VERSION 5.8 ;
BUSBITCHARS "[]" ;
DIVIDERCHAR "/" ;
UNITS
    DATABASE MICRONS 1000 ;
END UNITS

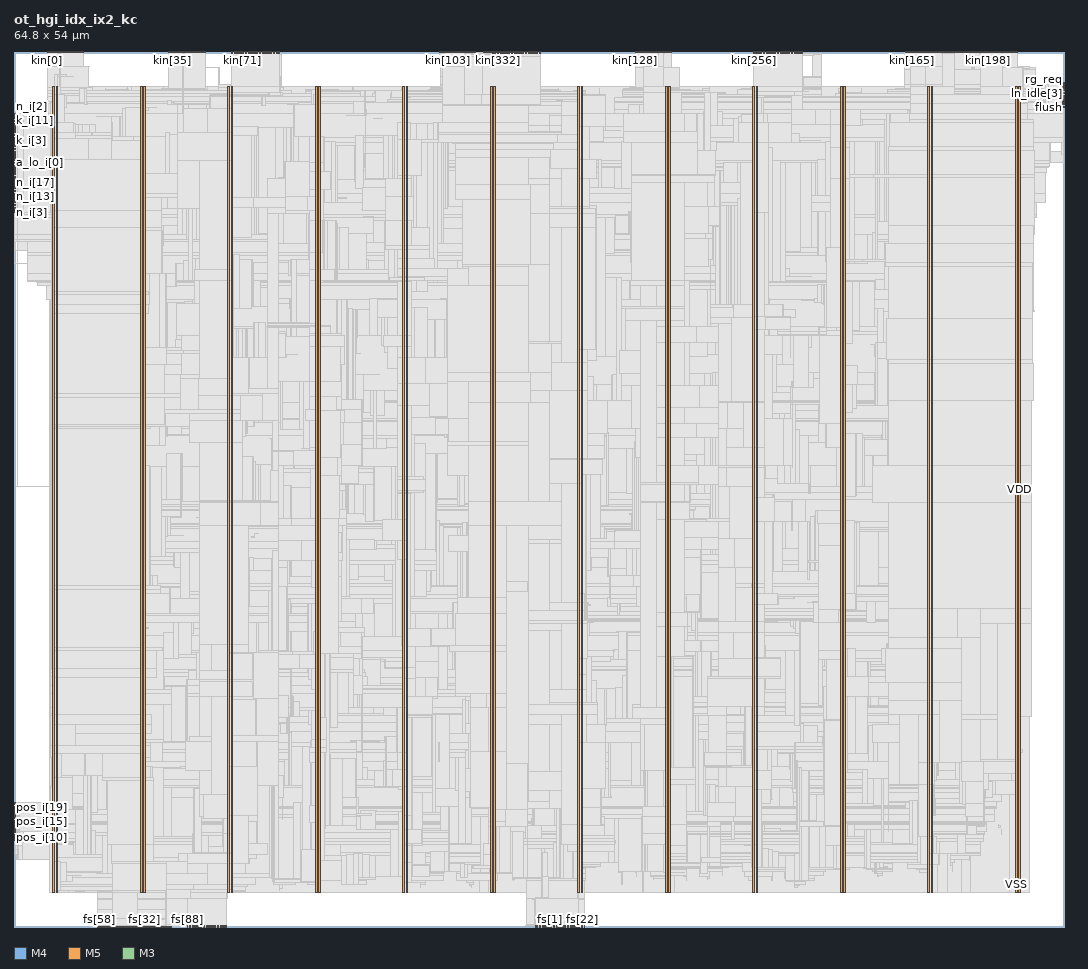
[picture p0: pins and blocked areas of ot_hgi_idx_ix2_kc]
MACRO ot_hgi_idx_ix2_kc
  FOREIGN ot_hgi_idx_ix2_kc 0 0 ;
  CLASS BLOCK ;
  SIZE 64.8 BY 54 ;
  PIN a_lo_i[0]
    DIRECTION INPUT ;
    USE SIGNAL ;
    PORT
      LAYER M4 ;
        RECT  0 47.184 0.084 47.208 ;
    END
  END a_lo_i[0]
  PIN a_lo_i[1]
    DIRECTION INPUT ;
    USE SIGNAL ;
    PORT
      LAYER M4 ;
        RECT  0 47.28 0.084 47.304 ;
    END
  END a_lo_i[1]
  PIN a_lo_i[2]
    DIRECTION INPUT ;
    USE SIGNAL ;
    PORT
      LAYER M4 ;
        RECT  0 47.376 0.084 47.4 ;
    END
  END a_lo_i[2]
  PIN c_done[0]
    DIRECTION INPUT ;
    USE SIGNAL ;
    PORT
      LAYER M5 ;
        RECT  32.208 0 32.232 0.084 ;
    END
  END c_done[0]
  PIN c_done[1]
    DIRECTION INPUT ;
    USE SIGNAL ;
    PORT
      LAYER M5 ;
        RECT  32.304 0 32.328 0.084 ;
    END
  END c_done[1]
  PIN c_done[2]
    DIRECTION INPUT ;
    USE SIGNAL ;
    PORT
      LAYER M5 ;
        RECT  32.4 0 32.424 0.084 ;
    END
  END c_done[2]
  PIN c_done[3]
    DIRECTION INPUT ;
    USE SIGNAL ;
    PORT
      LAYER M5 ;
        RECT  32.496 0 32.52 0.084 ;
    END
  END c_done[3]
  PIN c_done[4]
    DIRECTION INPUT ;
    USE SIGNAL ;
    PORT
      LAYER M5 ;
        RECT  32.592 0 32.616 0.084 ;
    END
  END c_done[4]
  PIN c_done[5]
    DIRECTION INPUT ;
    USE SIGNAL ;
    PORT
      LAYER M5 ;
        RECT  32.688 0 32.712 0.084 ;
    END
  END c_done[5]
  PIN c_done[6]
    DIRECTION INPUT ;
    USE SIGNAL ;
    PORT
      LAYER M5 ;
        RECT  32.784 0 32.808 0.084 ;
    END
  END c_done[6]
  PIN c_done[7]
    DIRECTION INPUT ;
    USE SIGNAL ;
    PORT
      LAYER M5 ;
        RECT  32.88 0 32.904 0.084 ;
    END
  END c_done[7]
  PIN cand_en_i
    DIRECTION INPUT ;
    USE SIGNAL ;
    PORT
      LAYER M4 ;
        RECT  0 47.472 0.084 47.496 ;
    END
  END cand_en_i
  PIN clk
    DIRECTION INPUT ;
    USE SIGNAL ;
    PORT
      LAYER M4 ;
        RECT  0 47.568 0.084 47.592 ;
    END
  END clk
  PIN cs_lo_i[0]
    DIRECTION INPUT ;
    USE SIGNAL ;
    PORT
      LAYER M4 ;
        RECT  0 47.664 0.084 47.688 ;
    END
  END cs_lo_i[0]
  PIN cs_lo_i[1]
    DIRECTION INPUT ;
    USE SIGNAL ;
    PORT
      LAYER M4 ;
        RECT  0 47.76 0.084 47.784 ;
    END
  END cs_lo_i[1]
  PIN cs_lo_i[2]
    DIRECTION INPUT ;
    USE SIGNAL ;
    PORT
      LAYER M4 ;
        RECT  0 47.856 0.084 47.88 ;
    END
  END cs_lo_i[2]
  PIN cs_lo_i[3]
    DIRECTION INPUT ;
    USE SIGNAL ;
    PORT
      LAYER M4 ;
        RECT  0 47.952 0.084 47.976 ;
    END
  END cs_lo_i[3]
  PIN cs_lo_i[4]
    DIRECTION INPUT ;
    USE SIGNAL ;
    PORT
      LAYER M4 ;
        RECT  0 48.048 0.084 48.072 ;
    END
  END cs_lo_i[4]
  PIN cs_lo_i[5]
    DIRECTION INPUT ;
    USE SIGNAL ;
    PORT
      LAYER M4 ;
        RECT  0 48.144 0.084 48.168 ;
    END
  END cs_lo_i[5]
  PIN done
    DIRECTION OUTPUT ;
    USE SIGNAL ;
    PORT
      LAYER M4 ;
        RECT  0 48.24 0.084 48.264 ;
    END
  END done
  PIN ev[0]
    DIRECTION INPUT ;
    USE SIGNAL ;
    PORT
      LAYER M4 ;
        RECT  0 48.336 0.084 48.36 ;
    END
  END ev[0]
  PIN ev[1]
    DIRECTION INPUT ;
    USE SIGNAL ;
    PORT
      LAYER M4 ;
        RECT  0 48.432 0.084 48.456 ;
    END
  END ev[1]
  PIN fault
    DIRECTION OUTPUT ;
    USE SIGNAL ;
    PORT
      LAYER M4 ;
        RECT  0 48.528 0.084 48.552 ;
    END
  END fault
  PIN flush
    DIRECTION OUTPUT ;
    USE SIGNAL ;
    PORT
      LAYER M4 ;
        RECT  64.716 50.544 64.8 50.568 ;
    END
  END flush
  PIN fs[0]
    DIRECTION OUTPUT ;
    USE SIGNAL ;
    PORT
      LAYER M5 ;
        RECT  32.976 0 33 0.084 ;
    END
  END fs[0]
  PIN fs[10]
    DIRECTION OUTPUT ;
    USE SIGNAL ;
    PORT
      LAYER M5 ;
        RECT  33.936 0 33.96 0.084 ;
    END
  END fs[10]
  PIN fs[11]
    DIRECTION OUTPUT ;
    USE SIGNAL ;
    PORT
      LAYER M5 ;
        RECT  34.032 0 34.056 0.084 ;
    END
  END fs[11]
  PIN fs[12]
    DIRECTION OUTPUT ;
    USE SIGNAL ;
    PORT
      LAYER M5 ;
        RECT  34.128 0 34.152 0.084 ;
    END
  END fs[12]
  PIN fs[13]
    DIRECTION OUTPUT ;
    USE SIGNAL ;
    PORT
      LAYER M5 ;
        RECT  34.224 0 34.248 0.084 ;
    END
  END fs[13]
  PIN fs[14]
    DIRECTION OUTPUT ;
    USE SIGNAL ;
    PORT
      LAYER M5 ;
        RECT  34.32 0 34.344 0.084 ;
    END
  END fs[14]
  PIN fs[15]
    DIRECTION OUTPUT ;
    USE SIGNAL ;
    PORT
      LAYER M5 ;
        RECT  34.416 0 34.44 0.084 ;
    END
  END fs[15]
  PIN fs[16]
    DIRECTION OUTPUT ;
    USE SIGNAL ;
    PORT
      LAYER M5 ;
        RECT  34.512 0 34.536 0.084 ;
    END
  END fs[16]
  PIN fs[17]
    DIRECTION OUTPUT ;
    USE SIGNAL ;
    PORT
      LAYER M5 ;
        RECT  34.608 0 34.632 0.084 ;
    END
  END fs[17]
  PIN fs[18]
    DIRECTION OUTPUT ;
    USE SIGNAL ;
    PORT
      LAYER M5 ;
        RECT  34.704 0 34.728 0.084 ;
    END
  END fs[18]
  PIN fs[19]
    DIRECTION OUTPUT ;
    USE SIGNAL ;
    PORT
      LAYER M5 ;
        RECT  34.8 0 34.824 0.084 ;
    END
  END fs[19]
  PIN fs[1]
    DIRECTION OUTPUT ;
    USE SIGNAL ;
    PORT
      LAYER M5 ;
        RECT  33.072 0 33.096 0.084 ;
    END
  END fs[1]
  PIN fs[20]
    DIRECTION OUTPUT ;
    USE SIGNAL ;
    PORT
      LAYER M5 ;
        RECT  34.896 0 34.92 0.084 ;
    END
  END fs[20]
  PIN fs[21]
    DIRECTION OUTPUT ;
    USE SIGNAL ;
    PORT
      LAYER M5 ;
        RECT  34.992 0 35.016 0.084 ;
    END
  END fs[21]
  PIN fs[22]
    DIRECTION OUTPUT ;
    USE SIGNAL ;
    PORT
      LAYER M5 ;
        RECT  35.088 0 35.112 0.084 ;
    END
  END fs[22]
  PIN fs[23]
    DIRECTION OUTPUT ;
    USE SIGNAL ;
    PORT
      LAYER M5 ;
        RECT  35.184 0 35.208 0.084 ;
    END
  END fs[23]
  PIN fs[24]
    DIRECTION OUTPUT ;
    USE SIGNAL ;
    PORT
      LAYER M3 ;
        RECT  7.452 0 7.47 0.037 ;
    END
  END fs[24]
  PIN fs[25]
    DIRECTION OUTPUT ;
    USE SIGNAL ;
    PORT
      LAYER M3 ;
        RECT  7.524 0 7.542 0.037 ;
    END
  END fs[25]
  PIN fs[26]
    DIRECTION OUTPUT ;
    USE SIGNAL ;
    PORT
      LAYER M3 ;
        RECT  7.596 0 7.614 0.037 ;
    END
  END fs[26]
  PIN fs[27]
    DIRECTION OUTPUT ;
    USE SIGNAL ;
    PORT
      LAYER M3 ;
        RECT  7.668 0 7.686 0.037 ;
    END
  END fs[27]
  PIN fs[28]
    DIRECTION OUTPUT ;
    USE SIGNAL ;
    PORT
      LAYER M3 ;
        RECT  7.74 0 7.758 0.037 ;
    END
  END fs[28]
  PIN fs[29]
    DIRECTION OUTPUT ;
    USE SIGNAL ;
    PORT
      LAYER M3 ;
        RECT  7.812 0 7.83 0.037 ;
    END
  END fs[29]
  PIN fs[2]
    DIRECTION OUTPUT ;
    USE SIGNAL ;
    PORT
      LAYER M5 ;
        RECT  33.168 0 33.192 0.084 ;
    END
  END fs[2]
  PIN fs[30]
    DIRECTION OUTPUT ;
    USE SIGNAL ;
    PORT
      LAYER M3 ;
        RECT  7.884 0 7.902 0.037 ;
    END
  END fs[30]
  PIN fs[31]
    DIRECTION OUTPUT ;
    USE SIGNAL ;
    PORT
      LAYER M3 ;
        RECT  7.956 0 7.974 0.037 ;
    END
  END fs[31]
  PIN fs[32]
    DIRECTION OUTPUT ;
    USE SIGNAL ;
    PORT
      LAYER M3 ;
        RECT  8.028 0 8.046 0.037 ;
    END
  END fs[32]
  PIN fs[33]
    DIRECTION OUTPUT ;
    USE SIGNAL ;
    PORT
      LAYER M3 ;
        RECT  8.1 0 8.118 0.037 ;
    END
  END fs[33]
  PIN fs[34]
    DIRECTION OUTPUT ;
    USE SIGNAL ;
    PORT
      LAYER M3 ;
        RECT  8.172 0 8.19 0.037 ;
    END
  END fs[34]
  PIN fs[35]
    DIRECTION OUTPUT ;
    USE SIGNAL ;
    PORT
      LAYER M3 ;
        RECT  8.244 0 8.262 0.037 ;
    END
  END fs[35]
  PIN fs[36]
    DIRECTION OUTPUT ;
    USE SIGNAL ;
    PORT
      LAYER M3 ;
        RECT  8.316 0 8.334 0.037 ;
    END
  END fs[36]
  PIN fs[37]
    DIRECTION OUTPUT ;
    USE SIGNAL ;
    PORT
      LAYER M3 ;
        RECT  8.388 0 8.406 0.037 ;
    END
  END fs[37]
  PIN fs[38]
    DIRECTION OUTPUT ;
    USE SIGNAL ;
    PORT
      LAYER M3 ;
        RECT  8.46 0 8.478 0.037 ;
    END
  END fs[38]
  PIN fs[39]
    DIRECTION OUTPUT ;
    USE SIGNAL ;
    PORT
      LAYER M3 ;
        RECT  8.532 0 8.55 0.037 ;
    END
  END fs[39]
  PIN fs[3]
    DIRECTION OUTPUT ;
    USE SIGNAL ;
    PORT
      LAYER M5 ;
        RECT  33.264 0 33.288 0.084 ;
    END
  END fs[3]
  PIN fs[40]
    DIRECTION OUTPUT ;
    USE SIGNAL ;
    PORT
      LAYER M3 ;
        RECT  8.604 0 8.622 0.037 ;
    END
  END fs[40]
  PIN fs[41]
    DIRECTION OUTPUT ;
    USE SIGNAL ;
    PORT
      LAYER M3 ;
        RECT  8.676 0 8.694 0.037 ;
    END
  END fs[41]
  PIN fs[42]
    DIRECTION OUTPUT ;
    USE SIGNAL ;
    PORT
      LAYER M3 ;
        RECT  8.748 0 8.766 0.037 ;
    END
  END fs[42]
  PIN fs[43]
    DIRECTION OUTPUT ;
    USE SIGNAL ;
    PORT
      LAYER M3 ;
        RECT  8.82 0 8.838 0.037 ;
    END
  END fs[43]
  PIN fs[44]
    DIRECTION OUTPUT ;
    USE SIGNAL ;
    PORT
      LAYER M3 ;
        RECT  8.892 0 8.91 0.037 ;
    END
  END fs[44]
  PIN fs[45]
    DIRECTION OUTPUT ;
    USE SIGNAL ;
    PORT
      LAYER M3 ;
        RECT  8.964 0 8.982 0.037 ;
    END
  END fs[45]
  PIN fs[46]
    DIRECTION OUTPUT ;
    USE SIGNAL ;
    PORT
      LAYER M3 ;
        RECT  9.036 0 9.054 0.037 ;
    END
  END fs[46]
  PIN fs[47]
    DIRECTION OUTPUT ;
    USE SIGNAL ;
    PORT
      LAYER M3 ;
        RECT  9.108 0 9.126 0.037 ;
    END
  END fs[47]
  PIN fs[48]
    DIRECTION OUTPUT ;
    USE SIGNAL ;
    PORT
      LAYER M3 ;
        RECT  9.18 0 9.198 0.037 ;
    END
  END fs[48]
  PIN fs[49]
    DIRECTION OUTPUT ;
    USE SIGNAL ;
    PORT
      LAYER M3 ;
        RECT  9.252 0 9.27 0.037 ;
    END
  END fs[49]
  PIN fs[4]
    DIRECTION OUTPUT ;
    USE SIGNAL ;
    PORT
      LAYER M5 ;
        RECT  33.36 0 33.384 0.084 ;
    END
  END fs[4]
  PIN fs[50]
    DIRECTION OUTPUT ;
    USE SIGNAL ;
    PORT
      LAYER M3 ;
        RECT  9.324 0 9.342 0.037 ;
    END
  END fs[50]
  PIN fs[51]
    DIRECTION OUTPUT ;
    USE SIGNAL ;
    PORT
      LAYER M3 ;
        RECT  9.396 0 9.414 0.037 ;
    END
  END fs[51]
  PIN fs[52]
    DIRECTION OUTPUT ;
    USE SIGNAL ;
    PORT
      LAYER M3 ;
        RECT  9.468 0 9.486 0.037 ;
    END
  END fs[52]
  PIN fs[53]
    DIRECTION OUTPUT ;
    USE SIGNAL ;
    PORT
      LAYER M3 ;
        RECT  9.54 0 9.558 0.037 ;
    END
  END fs[53]
  PIN fs[54]
    DIRECTION OUTPUT ;
    USE SIGNAL ;
    PORT
      LAYER M3 ;
        RECT  9.612 0 9.63 0.037 ;
    END
  END fs[54]
  PIN fs[55]
    DIRECTION OUTPUT ;
    USE SIGNAL ;
    PORT
      LAYER M3 ;
        RECT  9.684 0 9.702 0.037 ;
    END
  END fs[55]
  PIN fs[56]
    DIRECTION OUTPUT ;
    USE SIGNAL ;
    PORT
      LAYER M3 ;
        RECT  5.148 0 5.166 0.037 ;
    END
  END fs[56]
  PIN fs[57]
    DIRECTION OUTPUT ;
    USE SIGNAL ;
    PORT
      LAYER M3 ;
        RECT  5.22 0 5.238 0.037 ;
    END
  END fs[57]
  PIN fs[58]
    DIRECTION OUTPUT ;
    USE SIGNAL ;
    PORT
      LAYER M3 ;
        RECT  5.292 0 5.31 0.037 ;
    END
  END fs[58]
  PIN fs[59]
    DIRECTION OUTPUT ;
    USE SIGNAL ;
    PORT
      LAYER M3 ;
        RECT  5.364 0 5.382 0.037 ;
    END
  END fs[59]
  PIN fs[5]
    DIRECTION OUTPUT ;
    USE SIGNAL ;
    PORT
      LAYER M5 ;
        RECT  33.456 0 33.48 0.084 ;
    END
  END fs[5]
  PIN fs[60]
    DIRECTION OUTPUT ;
    USE SIGNAL ;
    PORT
      LAYER M3 ;
        RECT  5.436 0 5.454 0.037 ;
    END
  END fs[60]
  PIN fs[61]
    DIRECTION OUTPUT ;
    USE SIGNAL ;
    PORT
      LAYER M3 ;
        RECT  5.508 0 5.526 0.037 ;
    END
  END fs[61]
  PIN fs[62]
    DIRECTION OUTPUT ;
    USE SIGNAL ;
    PORT
      LAYER M3 ;
        RECT  5.58 0 5.598 0.037 ;
    END
  END fs[62]
  PIN fs[63]
    DIRECTION OUTPUT ;
    USE SIGNAL ;
    PORT
      LAYER M3 ;
        RECT  5.652 0 5.67 0.037 ;
    END
  END fs[63]
  PIN fs[64]
    DIRECTION OUTPUT ;
    USE SIGNAL ;
    PORT
      LAYER M3 ;
        RECT  5.724 0 5.742 0.037 ;
    END
  END fs[64]
  PIN fs[65]
    DIRECTION OUTPUT ;
    USE SIGNAL ;
    PORT
      LAYER M3 ;
        RECT  5.796 0 5.814 0.037 ;
    END
  END fs[65]
  PIN fs[66]
    DIRECTION OUTPUT ;
    USE SIGNAL ;
    PORT
      LAYER M3 ;
        RECT  5.868 0 5.886 0.037 ;
    END
  END fs[66]
  PIN fs[67]
    DIRECTION OUTPUT ;
    USE SIGNAL ;
    PORT
      LAYER M3 ;
        RECT  5.94 0 5.958 0.037 ;
    END
  END fs[67]
  PIN fs[68]
    DIRECTION OUTPUT ;
    USE SIGNAL ;
    PORT
      LAYER M3 ;
        RECT  6.012 0 6.03 0.037 ;
    END
  END fs[68]
  PIN fs[69]
    DIRECTION OUTPUT ;
    USE SIGNAL ;
    PORT
      LAYER M3 ;
        RECT  6.084 0 6.102 0.037 ;
    END
  END fs[69]
  PIN fs[6]
    DIRECTION OUTPUT ;
    USE SIGNAL ;
    PORT
      LAYER M5 ;
        RECT  33.552 0 33.576 0.084 ;
    END
  END fs[6]
  PIN fs[70]
    DIRECTION OUTPUT ;
    USE SIGNAL ;
    PORT
      LAYER M3 ;
        RECT  6.156 0 6.174 0.037 ;
    END
  END fs[70]
  PIN fs[71]
    DIRECTION OUTPUT ;
    USE SIGNAL ;
    PORT
      LAYER M3 ;
        RECT  6.228 0 6.246 0.037 ;
    END
  END fs[71]
  PIN fs[72]
    DIRECTION OUTPUT ;
    USE SIGNAL ;
    PORT
      LAYER M3 ;
        RECT  6.3 0 6.318 0.037 ;
    END
  END fs[72]
  PIN fs[73]
    DIRECTION OUTPUT ;
    USE SIGNAL ;
    PORT
      LAYER M3 ;
        RECT  6.372 0 6.39 0.037 ;
    END
  END fs[73]
  PIN fs[74]
    DIRECTION OUTPUT ;
    USE SIGNAL ;
    PORT
      LAYER M3 ;
        RECT  6.444 0 6.462 0.037 ;
    END
  END fs[74]
  PIN fs[75]
    DIRECTION OUTPUT ;
    USE SIGNAL ;
    PORT
      LAYER M3 ;
        RECT  6.516 0 6.534 0.037 ;
    END
  END fs[75]
  PIN fs[76]
    DIRECTION OUTPUT ;
    USE SIGNAL ;
    PORT
      LAYER M3 ;
        RECT  6.588 0 6.606 0.037 ;
    END
  END fs[76]
  PIN fs[77]
    DIRECTION OUTPUT ;
    USE SIGNAL ;
    PORT
      LAYER M3 ;
        RECT  6.66 0 6.678 0.037 ;
    END
  END fs[77]
  PIN fs[78]
    DIRECTION OUTPUT ;
    USE SIGNAL ;
    PORT
      LAYER M3 ;
        RECT  6.732 0 6.75 0.037 ;
    END
  END fs[78]
  PIN fs[79]
    DIRECTION OUTPUT ;
    USE SIGNAL ;
    PORT
      LAYER M3 ;
        RECT  6.804 0 6.822 0.037 ;
    END
  END fs[79]
  PIN fs[7]
    DIRECTION OUTPUT ;
    USE SIGNAL ;
    PORT
      LAYER M5 ;
        RECT  33.648 0 33.672 0.084 ;
    END
  END fs[7]
  PIN fs[80]
    DIRECTION OUTPUT ;
    USE SIGNAL ;
    PORT
      LAYER M3 ;
        RECT  6.876 0 6.894 0.037 ;
    END
  END fs[80]
  PIN fs[81]
    DIRECTION OUTPUT ;
    USE SIGNAL ;
    PORT
      LAYER M3 ;
        RECT  6.948 0 6.966 0.037 ;
    END
  END fs[81]
  PIN fs[82]
    DIRECTION OUTPUT ;
    USE SIGNAL ;
    PORT
      LAYER M3 ;
        RECT  7.02 0 7.038 0.037 ;
    END
  END fs[82]
  PIN fs[83]
    DIRECTION OUTPUT ;
    USE SIGNAL ;
    PORT
      LAYER M3 ;
        RECT  7.092 0 7.11 0.037 ;
    END
  END fs[83]
  PIN fs[84]
    DIRECTION OUTPUT ;
    USE SIGNAL ;
    PORT
      LAYER M3 ;
        RECT  7.164 0 7.182 0.037 ;
    END
  END fs[84]
  PIN fs[85]
    DIRECTION OUTPUT ;
    USE SIGNAL ;
    PORT
      LAYER M3 ;
        RECT  7.236 0 7.254 0.037 ;
    END
  END fs[85]
  PIN fs[86]
    DIRECTION OUTPUT ;
    USE SIGNAL ;
    PORT
      LAYER M3 ;
        RECT  7.308 0 7.326 0.037 ;
    END
  END fs[86]
  PIN fs[87]
    DIRECTION OUTPUT ;
    USE SIGNAL ;
    PORT
      LAYER M3 ;
        RECT  7.38 0 7.398 0.037 ;
    END
  END fs[87]
  PIN fs[88]
    DIRECTION OUTPUT ;
    USE SIGNAL ;
    PORT
      LAYER M5 ;
        RECT  10.704 0 10.728 0.084 ;
    END
  END fs[88]
  PIN fs[89]
    DIRECTION OUTPUT ;
    USE SIGNAL ;
    PORT
      LAYER M5 ;
        RECT  10.8 0 10.824 0.084 ;
    END
  END fs[89]
  PIN fs[8]
    DIRECTION OUTPUT ;
    USE SIGNAL ;
    PORT
      LAYER M5 ;
        RECT  33.744 0 33.768 0.084 ;
    END
  END fs[8]
  PIN fs[9]
    DIRECTION OUTPUT ;
    USE SIGNAL ;
    PORT
      LAYER M5 ;
        RECT  33.84 0 33.864 0.084 ;
    END
  END fs[9]
  PIN go_i
    DIRECTION INPUT ;
    USE SIGNAL ;
    PORT
      LAYER M4 ;
        RECT  0 48.624 0.084 48.648 ;
    END
  END go_i
  PIN k_i[0]
    DIRECTION INPUT ;
    USE SIGNAL ;
    PORT
      LAYER M4 ;
        RECT  0 48.72 0.084 48.744 ;
    END
  END k_i[0]
  PIN k_i[10]
    DIRECTION INPUT ;
    USE SIGNAL ;
    PORT
      LAYER M4 ;
        RECT  0 49.68 0.084 49.704 ;
    END
  END k_i[10]
  PIN k_i[11]
    DIRECTION INPUT ;
    USE SIGNAL ;
    PORT
      LAYER M4 ;
        RECT  0 49.776 0.084 49.8 ;
    END
  END k_i[11]
  PIN k_i[1]
    DIRECTION INPUT ;
    USE SIGNAL ;
    PORT
      LAYER M4 ;
        RECT  0 48.816 0.084 48.84 ;
    END
  END k_i[1]
  PIN k_i[2]
    DIRECTION INPUT ;
    USE SIGNAL ;
    PORT
      LAYER M4 ;
        RECT  0 48.912 0.084 48.936 ;
    END
  END k_i[2]
  PIN k_i[3]
    DIRECTION INPUT ;
    USE SIGNAL ;
    PORT
      LAYER M4 ;
        RECT  0 49.008 0.084 49.032 ;
    END
  END k_i[3]
  PIN k_i[4]
    DIRECTION INPUT ;
    USE SIGNAL ;
    PORT
      LAYER M4 ;
        RECT  0 49.104 0.084 49.128 ;
    END
  END k_i[4]
  PIN k_i[5]
    DIRECTION INPUT ;
    USE SIGNAL ;
    PORT
      LAYER M4 ;
        RECT  0 49.2 0.084 49.224 ;
    END
  END k_i[5]
  PIN k_i[6]
    DIRECTION INPUT ;
    USE SIGNAL ;
    PORT
      LAYER M4 ;
        RECT  0 49.296 0.084 49.32 ;
    END
  END k_i[6]
  PIN k_i[7]
    DIRECTION INPUT ;
    USE SIGNAL ;
    PORT
      LAYER M4 ;
        RECT  0 49.392 0.084 49.416 ;
    END
  END k_i[7]
  PIN k_i[8]
    DIRECTION INPUT ;
    USE SIGNAL ;
    PORT
      LAYER M4 ;
        RECT  0 49.488 0.084 49.512 ;
    END
  END k_i[8]
  PIN k_i[9]
    DIRECTION INPUT ;
    USE SIGNAL ;
    PORT
      LAYER M4 ;
        RECT  0 49.584 0.084 49.608 ;
    END
  END k_i[9]
  PIN keep_en_i
    DIRECTION INPUT ;
    USE SIGNAL ;
    PORT
      LAYER M4 ;
        RECT  0 49.872 0.084 49.896 ;
    END
  END keep_en_i
  PIN kin[0]
    DIRECTION OUTPUT ;
    USE SIGNAL ;
    PORT
      LAYER M3 ;
        RECT  2.052 53.963 2.07 54 ;
    END
  END kin[0]
  PIN kin[100]
    DIRECTION OUTPUT ;
    USE SIGNAL ;
    PORT
      LAYER M3 ;
        RECT  26.532 53.963 26.55 54 ;
    END
  END kin[100]
  PIN kin[101]
    DIRECTION OUTPUT ;
    USE SIGNAL ;
    PORT
      LAYER M3 ;
        RECT  26.604 53.963 26.622 54 ;
    END
  END kin[101]
  PIN kin[102]
    DIRECTION OUTPUT ;
    USE SIGNAL ;
    PORT
      LAYER M3 ;
        RECT  26.676 53.963 26.694 54 ;
    END
  END kin[102]
  PIN kin[103]
    DIRECTION OUTPUT ;
    USE SIGNAL ;
    PORT
      LAYER M3 ;
        RECT  26.748 53.963 26.766 54 ;
    END
  END kin[103]
  PIN kin[104]
    DIRECTION OUTPUT ;
    USE SIGNAL ;
    PORT
      LAYER M3 ;
        RECT  26.82 53.963 26.838 54 ;
    END
  END kin[104]
  PIN kin[105]
    DIRECTION OUTPUT ;
    USE SIGNAL ;
    PORT
      LAYER M3 ;
        RECT  26.892 53.963 26.91 54 ;
    END
  END kin[105]
  PIN kin[106]
    DIRECTION OUTPUT ;
    USE SIGNAL ;
    PORT
      LAYER M3 ;
        RECT  26.964 53.963 26.982 54 ;
    END
  END kin[106]
  PIN kin[107]
    DIRECTION OUTPUT ;
    USE SIGNAL ;
    PORT
      LAYER M3 ;
        RECT  27.036 53.963 27.054 54 ;
    END
  END kin[107]
  PIN kin[108]
    DIRECTION OUTPUT ;
    USE SIGNAL ;
    PORT
      LAYER M3 ;
        RECT  27.108 53.963 27.126 54 ;
    END
  END kin[108]
  PIN kin[109]
    DIRECTION OUTPUT ;
    USE SIGNAL ;
    PORT
      LAYER M3 ;
        RECT  27.18 53.963 27.198 54 ;
    END
  END kin[109]
  PIN kin[10]
    DIRECTION OUTPUT ;
    USE SIGNAL ;
    PORT
      LAYER M3 ;
        RECT  2.772 53.963 2.79 54 ;
    END
  END kin[10]
  PIN kin[110]
    DIRECTION OUTPUT ;
    USE SIGNAL ;
    PORT
      LAYER M3 ;
        RECT  27.252 53.963 27.27 54 ;
    END
  END kin[110]
  PIN kin[111]
    DIRECTION OUTPUT ;
    USE SIGNAL ;
    PORT
      LAYER M3 ;
        RECT  27.324 53.963 27.342 54 ;
    END
  END kin[111]
  PIN kin[112]
    DIRECTION OUTPUT ;
    USE SIGNAL ;
    PORT
      LAYER M3 ;
        RECT  27.396 53.963 27.414 54 ;
    END
  END kin[112]
  PIN kin[113]
    DIRECTION OUTPUT ;
    USE SIGNAL ;
    PORT
      LAYER M3 ;
        RECT  27.468 53.963 27.486 54 ;
    END
  END kin[113]
  PIN kin[114]
    DIRECTION OUTPUT ;
    USE SIGNAL ;
    PORT
      LAYER M3 ;
        RECT  27.54 53.963 27.558 54 ;
    END
  END kin[114]
  PIN kin[115]
    DIRECTION OUTPUT ;
    USE SIGNAL ;
    PORT
      LAYER M3 ;
        RECT  27.612 53.963 27.63 54 ;
    END
  END kin[115]
  PIN kin[116]
    DIRECTION OUTPUT ;
    USE SIGNAL ;
    PORT
      LAYER M3 ;
        RECT  27.684 53.963 27.702 54 ;
    END
  END kin[116]
  PIN kin[117]
    DIRECTION OUTPUT ;
    USE SIGNAL ;
    PORT
      LAYER M3 ;
        RECT  27.756 53.963 27.774 54 ;
    END
  END kin[117]
  PIN kin[118]
    DIRECTION OUTPUT ;
    USE SIGNAL ;
    PORT
      LAYER M3 ;
        RECT  27.828 53.963 27.846 54 ;
    END
  END kin[118]
  PIN kin[119]
    DIRECTION OUTPUT ;
    USE SIGNAL ;
    PORT
      LAYER M3 ;
        RECT  27.9 53.963 27.918 54 ;
    END
  END kin[119]
  PIN kin[11]
    DIRECTION OUTPUT ;
    USE SIGNAL ;
    PORT
      LAYER M3 ;
        RECT  2.844 53.963 2.862 54 ;
    END
  END kin[11]
  PIN kin[120]
    DIRECTION OUTPUT ;
    USE SIGNAL ;
    PORT
      LAYER M3 ;
        RECT  27.972 53.963 27.99 54 ;
    END
  END kin[120]
  PIN kin[121]
    DIRECTION OUTPUT ;
    USE SIGNAL ;
    PORT
      LAYER M3 ;
        RECT  28.044 53.963 28.062 54 ;
    END
  END kin[121]
  PIN kin[122]
    DIRECTION OUTPUT ;
    USE SIGNAL ;
    PORT
      LAYER M3 ;
        RECT  28.116 53.963 28.134 54 ;
    END
  END kin[122]
  PIN kin[123]
    DIRECTION OUTPUT ;
    USE SIGNAL ;
    PORT
      LAYER M3 ;
        RECT  28.188 53.963 28.206 54 ;
    END
  END kin[123]
  PIN kin[124]
    DIRECTION OUTPUT ;
    USE SIGNAL ;
    PORT
      LAYER M3 ;
        RECT  28.26 53.963 28.278 54 ;
    END
  END kin[124]
  PIN kin[125]
    DIRECTION OUTPUT ;
    USE SIGNAL ;
    PORT
      LAYER M3 ;
        RECT  28.332 53.963 28.35 54 ;
    END
  END kin[125]
  PIN kin[126]
    DIRECTION OUTPUT ;
    USE SIGNAL ;
    PORT
      LAYER M3 ;
        RECT  28.404 53.963 28.422 54 ;
    END
  END kin[126]
  PIN kin[127]
    DIRECTION OUTPUT ;
    USE SIGNAL ;
    PORT
      LAYER M3 ;
        RECT  28.476 53.963 28.494 54 ;
    END
  END kin[127]
  PIN kin[128]
    DIRECTION OUTPUT ;
    USE SIGNAL ;
    PORT
      LAYER M3 ;
        RECT  38.34 53.963 38.358 54 ;
    END
  END kin[128]
  PIN kin[129]
    DIRECTION OUTPUT ;
    USE SIGNAL ;
    PORT
      LAYER M3 ;
        RECT  38.412 53.963 38.43 54 ;
    END
  END kin[129]
  PIN kin[12]
    DIRECTION OUTPUT ;
    USE SIGNAL ;
    PORT
      LAYER M3 ;
        RECT  2.916 53.963 2.934 54 ;
    END
  END kin[12]
  PIN kin[130]
    DIRECTION OUTPUT ;
    USE SIGNAL ;
    PORT
      LAYER M3 ;
        RECT  38.484 53.963 38.502 54 ;
    END
  END kin[130]
  PIN kin[131]
    DIRECTION OUTPUT ;
    USE SIGNAL ;
    PORT
      LAYER M3 ;
        RECT  38.556 53.963 38.574 54 ;
    END
  END kin[131]
  PIN kin[132]
    DIRECTION OUTPUT ;
    USE SIGNAL ;
    PORT
      LAYER M3 ;
        RECT  38.628 53.963 38.646 54 ;
    END
  END kin[132]
  PIN kin[133]
    DIRECTION OUTPUT ;
    USE SIGNAL ;
    PORT
      LAYER M3 ;
        RECT  38.7 53.963 38.718 54 ;
    END
  END kin[133]
  PIN kin[134]
    DIRECTION OUTPUT ;
    USE SIGNAL ;
    PORT
      LAYER M3 ;
        RECT  38.772 53.963 38.79 54 ;
    END
  END kin[134]
  PIN kin[135]
    DIRECTION OUTPUT ;
    USE SIGNAL ;
    PORT
      LAYER M3 ;
        RECT  38.844 53.963 38.862 54 ;
    END
  END kin[135]
  PIN kin[136]
    DIRECTION OUTPUT ;
    USE SIGNAL ;
    PORT
      LAYER M3 ;
        RECT  38.916 53.963 38.934 54 ;
    END
  END kin[136]
  PIN kin[137]
    DIRECTION OUTPUT ;
    USE SIGNAL ;
    PORT
      LAYER M3 ;
        RECT  38.988 53.963 39.006 54 ;
    END
  END kin[137]
  PIN kin[138]
    DIRECTION OUTPUT ;
    USE SIGNAL ;
    PORT
      LAYER M3 ;
        RECT  39.06 53.963 39.078 54 ;
    END
  END kin[138]
  PIN kin[139]
    DIRECTION OUTPUT ;
    USE SIGNAL ;
    PORT
      LAYER M3 ;
        RECT  39.132 53.963 39.15 54 ;
    END
  END kin[139]
  PIN kin[13]
    DIRECTION OUTPUT ;
    USE SIGNAL ;
    PORT
      LAYER M3 ;
        RECT  2.988 53.963 3.006 54 ;
    END
  END kin[13]
  PIN kin[140]
    DIRECTION OUTPUT ;
    USE SIGNAL ;
    PORT
      LAYER M3 ;
        RECT  39.204 53.963 39.222 54 ;
    END
  END kin[140]
  PIN kin[141]
    DIRECTION OUTPUT ;
    USE SIGNAL ;
    PORT
      LAYER M3 ;
        RECT  39.276 53.963 39.294 54 ;
    END
  END kin[141]
  PIN kin[142]
    DIRECTION OUTPUT ;
    USE SIGNAL ;
    PORT
      LAYER M3 ;
        RECT  39.348 53.963 39.366 54 ;
    END
  END kin[142]
  PIN kin[143]
    DIRECTION OUTPUT ;
    USE SIGNAL ;
    PORT
      LAYER M3 ;
        RECT  39.42 53.963 39.438 54 ;
    END
  END kin[143]
  PIN kin[144]
    DIRECTION OUTPUT ;
    USE SIGNAL ;
    PORT
      LAYER M3 ;
        RECT  39.492 53.963 39.51 54 ;
    END
  END kin[144]
  PIN kin[145]
    DIRECTION OUTPUT ;
    USE SIGNAL ;
    PORT
      LAYER M3 ;
        RECT  39.564 53.963 39.582 54 ;
    END
  END kin[145]
  PIN kin[146]
    DIRECTION OUTPUT ;
    USE SIGNAL ;
    PORT
      LAYER M3 ;
        RECT  39.636 53.963 39.654 54 ;
    END
  END kin[146]
  PIN kin[147]
    DIRECTION OUTPUT ;
    USE SIGNAL ;
    PORT
      LAYER M3 ;
        RECT  39.708 53.963 39.726 54 ;
    END
  END kin[147]
  PIN kin[148]
    DIRECTION OUTPUT ;
    USE SIGNAL ;
    PORT
      LAYER M3 ;
        RECT  39.78 53.963 39.798 54 ;
    END
  END kin[148]
  PIN kin[149]
    DIRECTION OUTPUT ;
    USE SIGNAL ;
    PORT
      LAYER M3 ;
        RECT  39.852 53.963 39.87 54 ;
    END
  END kin[149]
  PIN kin[14]
    DIRECTION OUTPUT ;
    USE SIGNAL ;
    PORT
      LAYER M3 ;
        RECT  3.06 53.963 3.078 54 ;
    END
  END kin[14]
  PIN kin[150]
    DIRECTION OUTPUT ;
    USE SIGNAL ;
    PORT
      LAYER M3 ;
        RECT  39.924 53.963 39.942 54 ;
    END
  END kin[150]
  PIN kin[151]
    DIRECTION OUTPUT ;
    USE SIGNAL ;
    PORT
      LAYER M3 ;
        RECT  39.996 53.963 40.014 54 ;
    END
  END kin[151]
  PIN kin[152]
    DIRECTION OUTPUT ;
    USE SIGNAL ;
    PORT
      LAYER M3 ;
        RECT  40.068 53.963 40.086 54 ;
    END
  END kin[152]
  PIN kin[153]
    DIRECTION OUTPUT ;
    USE SIGNAL ;
    PORT
      LAYER M3 ;
        RECT  40.14 53.963 40.158 54 ;
    END
  END kin[153]
  PIN kin[154]
    DIRECTION OUTPUT ;
    USE SIGNAL ;
    PORT
      LAYER M3 ;
        RECT  40.212 53.963 40.23 54 ;
    END
  END kin[154]
  PIN kin[155]
    DIRECTION OUTPUT ;
    USE SIGNAL ;
    PORT
      LAYER M3 ;
        RECT  40.284 53.963 40.302 54 ;
    END
  END kin[155]
  PIN kin[156]
    DIRECTION OUTPUT ;
    USE SIGNAL ;
    PORT
      LAYER M3 ;
        RECT  40.356 53.963 40.374 54 ;
    END
  END kin[156]
  PIN kin[157]
    DIRECTION OUTPUT ;
    USE SIGNAL ;
    PORT
      LAYER M3 ;
        RECT  40.428 53.963 40.446 54 ;
    END
  END kin[157]
  PIN kin[158]
    DIRECTION OUTPUT ;
    USE SIGNAL ;
    PORT
      LAYER M3 ;
        RECT  40.5 53.963 40.518 54 ;
    END
  END kin[158]
  PIN kin[159]
    DIRECTION OUTPUT ;
    USE SIGNAL ;
    PORT
      LAYER M3 ;
        RECT  40.572 53.963 40.59 54 ;
    END
  END kin[159]
  PIN kin[15]
    DIRECTION OUTPUT ;
    USE SIGNAL ;
    PORT
      LAYER M3 ;
        RECT  3.132 53.963 3.15 54 ;
    END
  END kin[15]
  PIN kin[160]
    DIRECTION OUTPUT ;
    USE SIGNAL ;
    PORT
      LAYER M3 ;
        RECT  55.044 53.963 55.062 54 ;
    END
  END kin[160]
  PIN kin[161]
    DIRECTION OUTPUT ;
    USE SIGNAL ;
    PORT
      LAYER M3 ;
        RECT  55.116 53.963 55.134 54 ;
    END
  END kin[161]
  PIN kin[162]
    DIRECTION OUTPUT ;
    USE SIGNAL ;
    PORT
      LAYER M3 ;
        RECT  55.188 53.963 55.206 54 ;
    END
  END kin[162]
  PIN kin[163]
    DIRECTION OUTPUT ;
    USE SIGNAL ;
    PORT
      LAYER M3 ;
        RECT  55.26 53.963 55.278 54 ;
    END
  END kin[163]
  PIN kin[164]
    DIRECTION OUTPUT ;
    USE SIGNAL ;
    PORT
      LAYER M3 ;
        RECT  55.332 53.963 55.35 54 ;
    END
  END kin[164]
  PIN kin[165]
    DIRECTION OUTPUT ;
    USE SIGNAL ;
    PORT
      LAYER M3 ;
        RECT  55.404 53.963 55.422 54 ;
    END
  END kin[165]
  PIN kin[166]
    DIRECTION OUTPUT ;
    USE SIGNAL ;
    PORT
      LAYER M3 ;
        RECT  55.476 53.963 55.494 54 ;
    END
  END kin[166]
  PIN kin[167]
    DIRECTION OUTPUT ;
    USE SIGNAL ;
    PORT
      LAYER M3 ;
        RECT  55.548 53.963 55.566 54 ;
    END
  END kin[167]
  PIN kin[168]
    DIRECTION OUTPUT ;
    USE SIGNAL ;
    PORT
      LAYER M3 ;
        RECT  55.62 53.963 55.638 54 ;
    END
  END kin[168]
  PIN kin[169]
    DIRECTION OUTPUT ;
    USE SIGNAL ;
    PORT
      LAYER M3 ;
        RECT  55.692 53.963 55.71 54 ;
    END
  END kin[169]
  PIN kin[16]
    DIRECTION OUTPUT ;
    USE SIGNAL ;
    PORT
      LAYER M3 ;
        RECT  3.204 53.963 3.222 54 ;
    END
  END kin[16]
  PIN kin[170]
    DIRECTION OUTPUT ;
    USE SIGNAL ;
    PORT
      LAYER M3 ;
        RECT  55.764 53.963 55.782 54 ;
    END
  END kin[170]
  PIN kin[171]
    DIRECTION OUTPUT ;
    USE SIGNAL ;
    PORT
      LAYER M3 ;
        RECT  55.836 53.963 55.854 54 ;
    END
  END kin[171]
  PIN kin[172]
    DIRECTION OUTPUT ;
    USE SIGNAL ;
    PORT
      LAYER M3 ;
        RECT  55.908 53.963 55.926 54 ;
    END
  END kin[172]
  PIN kin[173]
    DIRECTION OUTPUT ;
    USE SIGNAL ;
    PORT
      LAYER M3 ;
        RECT  55.98 53.963 55.998 54 ;
    END
  END kin[173]
  PIN kin[174]
    DIRECTION OUTPUT ;
    USE SIGNAL ;
    PORT
      LAYER M3 ;
        RECT  56.052 53.963 56.07 54 ;
    END
  END kin[174]
  PIN kin[175]
    DIRECTION OUTPUT ;
    USE SIGNAL ;
    PORT
      LAYER M3 ;
        RECT  56.124 53.963 56.142 54 ;
    END
  END kin[175]
  PIN kin[176]
    DIRECTION OUTPUT ;
    USE SIGNAL ;
    PORT
      LAYER M3 ;
        RECT  56.196 53.963 56.214 54 ;
    END
  END kin[176]
  PIN kin[177]
    DIRECTION OUTPUT ;
    USE SIGNAL ;
    PORT
      LAYER M3 ;
        RECT  56.268 53.963 56.286 54 ;
    END
  END kin[177]
  PIN kin[178]
    DIRECTION OUTPUT ;
    USE SIGNAL ;
    PORT
      LAYER M3 ;
        RECT  56.34 53.963 56.358 54 ;
    END
  END kin[178]
  PIN kin[179]
    DIRECTION OUTPUT ;
    USE SIGNAL ;
    PORT
      LAYER M3 ;
        RECT  56.412 53.963 56.43 54 ;
    END
  END kin[179]
  PIN kin[17]
    DIRECTION OUTPUT ;
    USE SIGNAL ;
    PORT
      LAYER M3 ;
        RECT  3.276 53.963 3.294 54 ;
    END
  END kin[17]
  PIN kin[180]
    DIRECTION OUTPUT ;
    USE SIGNAL ;
    PORT
      LAYER M3 ;
        RECT  56.484 53.963 56.502 54 ;
    END
  END kin[180]
  PIN kin[181]
    DIRECTION OUTPUT ;
    USE SIGNAL ;
    PORT
      LAYER M3 ;
        RECT  56.556 53.963 56.574 54 ;
    END
  END kin[181]
  PIN kin[182]
    DIRECTION OUTPUT ;
    USE SIGNAL ;
    PORT
      LAYER M3 ;
        RECT  56.628 53.963 56.646 54 ;
    END
  END kin[182]
  PIN kin[183]
    DIRECTION OUTPUT ;
    USE SIGNAL ;
    PORT
      LAYER M3 ;
        RECT  56.7 53.963 56.718 54 ;
    END
  END kin[183]
  PIN kin[184]
    DIRECTION OUTPUT ;
    USE SIGNAL ;
    PORT
      LAYER M3 ;
        RECT  56.772 53.963 56.79 54 ;
    END
  END kin[184]
  PIN kin[185]
    DIRECTION OUTPUT ;
    USE SIGNAL ;
    PORT
      LAYER M3 ;
        RECT  56.844 53.963 56.862 54 ;
    END
  END kin[185]
  PIN kin[186]
    DIRECTION OUTPUT ;
    USE SIGNAL ;
    PORT
      LAYER M3 ;
        RECT  56.916 53.963 56.934 54 ;
    END
  END kin[186]
  PIN kin[187]
    DIRECTION OUTPUT ;
    USE SIGNAL ;
    PORT
      LAYER M3 ;
        RECT  56.988 53.963 57.006 54 ;
    END
  END kin[187]
  PIN kin[188]
    DIRECTION OUTPUT ;
    USE SIGNAL ;
    PORT
      LAYER M3 ;
        RECT  57.06 53.963 57.078 54 ;
    END
  END kin[188]
  PIN kin[189]
    DIRECTION OUTPUT ;
    USE SIGNAL ;
    PORT
      LAYER M3 ;
        RECT  57.132 53.963 57.15 54 ;
    END
  END kin[189]
  PIN kin[18]
    DIRECTION OUTPUT ;
    USE SIGNAL ;
    PORT
      LAYER M3 ;
        RECT  3.348 53.963 3.366 54 ;
    END
  END kin[18]
  PIN kin[190]
    DIRECTION OUTPUT ;
    USE SIGNAL ;
    PORT
      LAYER M3 ;
        RECT  57.204 53.963 57.222 54 ;
    END
  END kin[190]
  PIN kin[191]
    DIRECTION OUTPUT ;
    USE SIGNAL ;
    PORT
      LAYER M3 ;
        RECT  57.276 53.963 57.294 54 ;
    END
  END kin[191]
  PIN kin[192]
    DIRECTION OUTPUT ;
    USE SIGNAL ;
    PORT
      LAYER M3 ;
        RECT  59.652 53.963 59.67 54 ;
    END
  END kin[192]
  PIN kin[193]
    DIRECTION OUTPUT ;
    USE SIGNAL ;
    PORT
      LAYER M3 ;
        RECT  59.724 53.963 59.742 54 ;
    END
  END kin[193]
  PIN kin[194]
    DIRECTION OUTPUT ;
    USE SIGNAL ;
    PORT
      LAYER M3 ;
        RECT  59.796 53.963 59.814 54 ;
    END
  END kin[194]
  PIN kin[195]
    DIRECTION OUTPUT ;
    USE SIGNAL ;
    PORT
      LAYER M3 ;
        RECT  59.868 53.963 59.886 54 ;
    END
  END kin[195]
  PIN kin[196]
    DIRECTION OUTPUT ;
    USE SIGNAL ;
    PORT
      LAYER M3 ;
        RECT  59.94 53.963 59.958 54 ;
    END
  END kin[196]
  PIN kin[197]
    DIRECTION OUTPUT ;
    USE SIGNAL ;
    PORT
      LAYER M3 ;
        RECT  60.012 53.963 60.03 54 ;
    END
  END kin[197]
  PIN kin[198]
    DIRECTION OUTPUT ;
    USE SIGNAL ;
    PORT
      LAYER M3 ;
        RECT  60.084 53.963 60.102 54 ;
    END
  END kin[198]
  PIN kin[199]
    DIRECTION OUTPUT ;
    USE SIGNAL ;
    PORT
      LAYER M3 ;
        RECT  60.156 53.963 60.174 54 ;
    END
  END kin[199]
  PIN kin[19]
    DIRECTION OUTPUT ;
    USE SIGNAL ;
    PORT
      LAYER M3 ;
        RECT  3.42 53.963 3.438 54 ;
    END
  END kin[19]
  PIN kin[1]
    DIRECTION OUTPUT ;
    USE SIGNAL ;
    PORT
      LAYER M3 ;
        RECT  2.124 53.963 2.142 54 ;
    END
  END kin[1]
  PIN kin[200]
    DIRECTION OUTPUT ;
    USE SIGNAL ;
    PORT
      LAYER M3 ;
        RECT  60.228 53.963 60.246 54 ;
    END
  END kin[200]
  PIN kin[201]
    DIRECTION OUTPUT ;
    USE SIGNAL ;
    PORT
      LAYER M3 ;
        RECT  60.3 53.963 60.318 54 ;
    END
  END kin[201]
  PIN kin[202]
    DIRECTION OUTPUT ;
    USE SIGNAL ;
    PORT
      LAYER M3 ;
        RECT  60.372 53.963 60.39 54 ;
    END
  END kin[202]
  PIN kin[203]
    DIRECTION OUTPUT ;
    USE SIGNAL ;
    PORT
      LAYER M3 ;
        RECT  60.444 53.963 60.462 54 ;
    END
  END kin[203]
  PIN kin[204]
    DIRECTION OUTPUT ;
    USE SIGNAL ;
    PORT
      LAYER M3 ;
        RECT  60.516 53.963 60.534 54 ;
    END
  END kin[204]
  PIN kin[205]
    DIRECTION OUTPUT ;
    USE SIGNAL ;
    PORT
      LAYER M3 ;
        RECT  60.588 53.963 60.606 54 ;
    END
  END kin[205]
  PIN kin[206]
    DIRECTION OUTPUT ;
    USE SIGNAL ;
    PORT
      LAYER M3 ;
        RECT  60.66 53.963 60.678 54 ;
    END
  END kin[206]
  PIN kin[207]
    DIRECTION OUTPUT ;
    USE SIGNAL ;
    PORT
      LAYER M3 ;
        RECT  60.732 53.963 60.75 54 ;
    END
  END kin[207]
  PIN kin[208]
    DIRECTION OUTPUT ;
    USE SIGNAL ;
    PORT
      LAYER M3 ;
        RECT  60.804 53.963 60.822 54 ;
    END
  END kin[208]
  PIN kin[209]
    DIRECTION OUTPUT ;
    USE SIGNAL ;
    PORT
      LAYER M3 ;
        RECT  60.876 53.963 60.894 54 ;
    END
  END kin[209]
  PIN kin[20]
    DIRECTION OUTPUT ;
    USE SIGNAL ;
    PORT
      LAYER M3 ;
        RECT  3.492 53.963 3.51 54 ;
    END
  END kin[20]
  PIN kin[210]
    DIRECTION OUTPUT ;
    USE SIGNAL ;
    PORT
      LAYER M3 ;
        RECT  60.948 53.963 60.966 54 ;
    END
  END kin[210]
  PIN kin[211]
    DIRECTION OUTPUT ;
    USE SIGNAL ;
    PORT
      LAYER M3 ;
        RECT  61.02 53.963 61.038 54 ;
    END
  END kin[211]
  PIN kin[212]
    DIRECTION OUTPUT ;
    USE SIGNAL ;
    PORT
      LAYER M3 ;
        RECT  61.092 53.963 61.11 54 ;
    END
  END kin[212]
  PIN kin[213]
    DIRECTION OUTPUT ;
    USE SIGNAL ;
    PORT
      LAYER M3 ;
        RECT  61.164 53.963 61.182 54 ;
    END
  END kin[213]
  PIN kin[214]
    DIRECTION OUTPUT ;
    USE SIGNAL ;
    PORT
      LAYER M3 ;
        RECT  61.236 53.963 61.254 54 ;
    END
  END kin[214]
  PIN kin[215]
    DIRECTION OUTPUT ;
    USE SIGNAL ;
    PORT
      LAYER M3 ;
        RECT  61.308 53.963 61.326 54 ;
    END
  END kin[215]
  PIN kin[216]
    DIRECTION OUTPUT ;
    USE SIGNAL ;
    PORT
      LAYER M3 ;
        RECT  61.38 53.963 61.398 54 ;
    END
  END kin[216]
  PIN kin[217]
    DIRECTION OUTPUT ;
    USE SIGNAL ;
    PORT
      LAYER M3 ;
        RECT  61.452 53.963 61.47 54 ;
    END
  END kin[217]
  PIN kin[218]
    DIRECTION OUTPUT ;
    USE SIGNAL ;
    PORT
      LAYER M3 ;
        RECT  61.524 53.963 61.542 54 ;
    END
  END kin[218]
  PIN kin[219]
    DIRECTION OUTPUT ;
    USE SIGNAL ;
    PORT
      LAYER M3 ;
        RECT  61.596 53.963 61.614 54 ;
    END
  END kin[219]
  PIN kin[21]
    DIRECTION OUTPUT ;
    USE SIGNAL ;
    PORT
      LAYER M3 ;
        RECT  3.564 53.963 3.582 54 ;
    END
  END kin[21]
  PIN kin[220]
    DIRECTION OUTPUT ;
    USE SIGNAL ;
    PORT
      LAYER M3 ;
        RECT  61.668 53.963 61.686 54 ;
    END
  END kin[220]
  PIN kin[221]
    DIRECTION OUTPUT ;
    USE SIGNAL ;
    PORT
      LAYER M3 ;
        RECT  61.74 53.963 61.758 54 ;
    END
  END kin[221]
  PIN kin[222]
    DIRECTION OUTPUT ;
    USE SIGNAL ;
    PORT
      LAYER M3 ;
        RECT  61.812 53.963 61.83 54 ;
    END
  END kin[222]
  PIN kin[223]
    DIRECTION OUTPUT ;
    USE SIGNAL ;
    PORT
      LAYER M3 ;
        RECT  61.884 53.963 61.902 54 ;
    END
  END kin[223]
  PIN kin[224]
    DIRECTION OUTPUT ;
    USE SIGNAL ;
    PORT
      LAYER M3 ;
        RECT  57.348 53.963 57.366 54 ;
    END
  END kin[224]
  PIN kin[225]
    DIRECTION OUTPUT ;
    USE SIGNAL ;
    PORT
      LAYER M3 ;
        RECT  57.42 53.963 57.438 54 ;
    END
  END kin[225]
  PIN kin[226]
    DIRECTION OUTPUT ;
    USE SIGNAL ;
    PORT
      LAYER M3 ;
        RECT  57.492 53.963 57.51 54 ;
    END
  END kin[226]
  PIN kin[227]
    DIRECTION OUTPUT ;
    USE SIGNAL ;
    PORT
      LAYER M3 ;
        RECT  57.564 53.963 57.582 54 ;
    END
  END kin[227]
  PIN kin[228]
    DIRECTION OUTPUT ;
    USE SIGNAL ;
    PORT
      LAYER M3 ;
        RECT  57.636 53.963 57.654 54 ;
    END
  END kin[228]
  PIN kin[229]
    DIRECTION OUTPUT ;
    USE SIGNAL ;
    PORT
      LAYER M3 ;
        RECT  57.708 53.963 57.726 54 ;
    END
  END kin[229]
  PIN kin[22]
    DIRECTION OUTPUT ;
    USE SIGNAL ;
    PORT
      LAYER M3 ;
        RECT  3.636 53.963 3.654 54 ;
    END
  END kin[22]
  PIN kin[230]
    DIRECTION OUTPUT ;
    USE SIGNAL ;
    PORT
      LAYER M3 ;
        RECT  57.78 53.963 57.798 54 ;
    END
  END kin[230]
  PIN kin[231]
    DIRECTION OUTPUT ;
    USE SIGNAL ;
    PORT
      LAYER M3 ;
        RECT  57.852 53.963 57.87 54 ;
    END
  END kin[231]
  PIN kin[232]
    DIRECTION OUTPUT ;
    USE SIGNAL ;
    PORT
      LAYER M3 ;
        RECT  57.924 53.963 57.942 54 ;
    END
  END kin[232]
  PIN kin[233]
    DIRECTION OUTPUT ;
    USE SIGNAL ;
    PORT
      LAYER M3 ;
        RECT  57.996 53.963 58.014 54 ;
    END
  END kin[233]
  PIN kin[234]
    DIRECTION OUTPUT ;
    USE SIGNAL ;
    PORT
      LAYER M3 ;
        RECT  58.068 53.963 58.086 54 ;
    END
  END kin[234]
  PIN kin[235]
    DIRECTION OUTPUT ;
    USE SIGNAL ;
    PORT
      LAYER M3 ;
        RECT  58.14 53.963 58.158 54 ;
    END
  END kin[235]
  PIN kin[236]
    DIRECTION OUTPUT ;
    USE SIGNAL ;
    PORT
      LAYER M3 ;
        RECT  58.212 53.963 58.23 54 ;
    END
  END kin[236]
  PIN kin[237]
    DIRECTION OUTPUT ;
    USE SIGNAL ;
    PORT
      LAYER M3 ;
        RECT  58.284 53.963 58.302 54 ;
    END
  END kin[237]
  PIN kin[238]
    DIRECTION OUTPUT ;
    USE SIGNAL ;
    PORT
      LAYER M3 ;
        RECT  58.356 53.963 58.374 54 ;
    END
  END kin[238]
  PIN kin[239]
    DIRECTION OUTPUT ;
    USE SIGNAL ;
    PORT
      LAYER M3 ;
        RECT  58.428 53.963 58.446 54 ;
    END
  END kin[239]
  PIN kin[23]
    DIRECTION OUTPUT ;
    USE SIGNAL ;
    PORT
      LAYER M3 ;
        RECT  3.708 53.963 3.726 54 ;
    END
  END kin[23]
  PIN kin[240]
    DIRECTION OUTPUT ;
    USE SIGNAL ;
    PORT
      LAYER M3 ;
        RECT  58.5 53.963 58.518 54 ;
    END
  END kin[240]
  PIN kin[241]
    DIRECTION OUTPUT ;
    USE SIGNAL ;
    PORT
      LAYER M3 ;
        RECT  58.572 53.963 58.59 54 ;
    END
  END kin[241]
  PIN kin[242]
    DIRECTION OUTPUT ;
    USE SIGNAL ;
    PORT
      LAYER M3 ;
        RECT  58.644 53.963 58.662 54 ;
    END
  END kin[242]
  PIN kin[243]
    DIRECTION OUTPUT ;
    USE SIGNAL ;
    PORT
      LAYER M3 ;
        RECT  58.716 53.963 58.734 54 ;
    END
  END kin[243]
  PIN kin[244]
    DIRECTION OUTPUT ;
    USE SIGNAL ;
    PORT
      LAYER M3 ;
        RECT  58.788 53.963 58.806 54 ;
    END
  END kin[244]
  PIN kin[245]
    DIRECTION OUTPUT ;
    USE SIGNAL ;
    PORT
      LAYER M3 ;
        RECT  58.86 53.963 58.878 54 ;
    END
  END kin[245]
  PIN kin[246]
    DIRECTION OUTPUT ;
    USE SIGNAL ;
    PORT
      LAYER M3 ;
        RECT  58.932 53.963 58.95 54 ;
    END
  END kin[246]
  PIN kin[247]
    DIRECTION OUTPUT ;
    USE SIGNAL ;
    PORT
      LAYER M3 ;
        RECT  59.004 53.963 59.022 54 ;
    END
  END kin[247]
  PIN kin[248]
    DIRECTION OUTPUT ;
    USE SIGNAL ;
    PORT
      LAYER M3 ;
        RECT  59.076 53.963 59.094 54 ;
    END
  END kin[248]
  PIN kin[249]
    DIRECTION OUTPUT ;
    USE SIGNAL ;
    PORT
      LAYER M3 ;
        RECT  59.148 53.963 59.166 54 ;
    END
  END kin[249]
  PIN kin[24]
    DIRECTION OUTPUT ;
    USE SIGNAL ;
    PORT
      LAYER M3 ;
        RECT  3.78 53.963 3.798 54 ;
    END
  END kin[24]
  PIN kin[250]
    DIRECTION OUTPUT ;
    USE SIGNAL ;
    PORT
      LAYER M3 ;
        RECT  59.22 53.963 59.238 54 ;
    END
  END kin[250]
  PIN kin[251]
    DIRECTION OUTPUT ;
    USE SIGNAL ;
    PORT
      LAYER M3 ;
        RECT  59.292 53.963 59.31 54 ;
    END
  END kin[251]
  PIN kin[252]
    DIRECTION OUTPUT ;
    USE SIGNAL ;
    PORT
      LAYER M3 ;
        RECT  59.364 53.963 59.382 54 ;
    END
  END kin[252]
  PIN kin[253]
    DIRECTION OUTPUT ;
    USE SIGNAL ;
    PORT
      LAYER M3 ;
        RECT  59.436 53.963 59.454 54 ;
    END
  END kin[253]
  PIN kin[254]
    DIRECTION OUTPUT ;
    USE SIGNAL ;
    PORT
      LAYER M3 ;
        RECT  59.508 53.963 59.526 54 ;
    END
  END kin[254]
  PIN kin[255]
    DIRECTION OUTPUT ;
    USE SIGNAL ;
    PORT
      LAYER M3 ;
        RECT  59.58 53.963 59.598 54 ;
    END
  END kin[255]
  PIN kin[256]
    DIRECTION OUTPUT ;
    USE SIGNAL ;
    PORT
      LAYER M5 ;
        RECT  45.648 53.916 45.672 54 ;
    END
  END kin[256]
  PIN kin[257]
    DIRECTION OUTPUT ;
    USE SIGNAL ;
    PORT
      LAYER M5 ;
        RECT  45.744 53.916 45.768 54 ;
    END
  END kin[257]
  PIN kin[258]
    DIRECTION OUTPUT ;
    USE SIGNAL ;
    PORT
      LAYER M5 ;
        RECT  45.84 53.916 45.864 54 ;
    END
  END kin[258]
  PIN kin[259]
    DIRECTION OUTPUT ;
    USE SIGNAL ;
    PORT
      LAYER M5 ;
        RECT  45.936 53.916 45.96 54 ;
    END
  END kin[259]
  PIN kin[25]
    DIRECTION OUTPUT ;
    USE SIGNAL ;
    PORT
      LAYER M3 ;
        RECT  3.852 53.963 3.87 54 ;
    END
  END kin[25]
  PIN kin[260]
    DIRECTION OUTPUT ;
    USE SIGNAL ;
    PORT
      LAYER M5 ;
        RECT  46.032 53.916 46.056 54 ;
    END
  END kin[260]
  PIN kin[261]
    DIRECTION OUTPUT ;
    USE SIGNAL ;
    PORT
      LAYER M5 ;
        RECT  46.128 53.916 46.152 54 ;
    END
  END kin[261]
  PIN kin[262]
    DIRECTION OUTPUT ;
    USE SIGNAL ;
    PORT
      LAYER M5 ;
        RECT  46.224 53.916 46.248 54 ;
    END
  END kin[262]
  PIN kin[263]
    DIRECTION OUTPUT ;
    USE SIGNAL ;
    PORT
      LAYER M5 ;
        RECT  46.32 53.916 46.344 54 ;
    END
  END kin[263]
  PIN kin[264]
    DIRECTION OUTPUT ;
    USE SIGNAL ;
    PORT
      LAYER M5 ;
        RECT  46.416 53.916 46.44 54 ;
    END
  END kin[264]
  PIN kin[265]
    DIRECTION OUTPUT ;
    USE SIGNAL ;
    PORT
      LAYER M5 ;
        RECT  46.512 53.916 46.536 54 ;
    END
  END kin[265]
  PIN kin[266]
    DIRECTION OUTPUT ;
    USE SIGNAL ;
    PORT
      LAYER M5 ;
        RECT  46.608 53.916 46.632 54 ;
    END
  END kin[266]
  PIN kin[267]
    DIRECTION OUTPUT ;
    USE SIGNAL ;
    PORT
      LAYER M5 ;
        RECT  46.704 53.916 46.728 54 ;
    END
  END kin[267]
  PIN kin[268]
    DIRECTION OUTPUT ;
    USE SIGNAL ;
    PORT
      LAYER M5 ;
        RECT  46.8 53.916 46.824 54 ;
    END
  END kin[268]
  PIN kin[269]
    DIRECTION OUTPUT ;
    USE SIGNAL ;
    PORT
      LAYER M5 ;
        RECT  46.896 53.916 46.92 54 ;
    END
  END kin[269]
  PIN kin[26]
    DIRECTION OUTPUT ;
    USE SIGNAL ;
    PORT
      LAYER M3 ;
        RECT  3.924 53.963 3.942 54 ;
    END
  END kin[26]
  PIN kin[270]
    DIRECTION OUTPUT ;
    USE SIGNAL ;
    PORT
      LAYER M5 ;
        RECT  46.992 53.916 47.016 54 ;
    END
  END kin[270]
  PIN kin[271]
    DIRECTION OUTPUT ;
    USE SIGNAL ;
    PORT
      LAYER M5 ;
        RECT  47.088 53.916 47.112 54 ;
    END
  END kin[271]
  PIN kin[272]
    DIRECTION OUTPUT ;
    USE SIGNAL ;
    PORT
      LAYER M5 ;
        RECT  47.184 53.916 47.208 54 ;
    END
  END kin[272]
  PIN kin[273]
    DIRECTION OUTPUT ;
    USE SIGNAL ;
    PORT
      LAYER M5 ;
        RECT  47.28 53.916 47.304 54 ;
    END
  END kin[273]
  PIN kin[274]
    DIRECTION OUTPUT ;
    USE SIGNAL ;
    PORT
      LAYER M5 ;
        RECT  47.376 53.916 47.4 54 ;
    END
  END kin[274]
  PIN kin[275]
    DIRECTION OUTPUT ;
    USE SIGNAL ;
    PORT
      LAYER M5 ;
        RECT  47.472 53.916 47.496 54 ;
    END
  END kin[275]
  PIN kin[276]
    DIRECTION OUTPUT ;
    USE SIGNAL ;
    PORT
      LAYER M5 ;
        RECT  47.568 53.916 47.592 54 ;
    END
  END kin[276]
  PIN kin[277]
    DIRECTION OUTPUT ;
    USE SIGNAL ;
    PORT
      LAYER M5 ;
        RECT  47.664 53.916 47.688 54 ;
    END
  END kin[277]
  PIN kin[278]
    DIRECTION OUTPUT ;
    USE SIGNAL ;
    PORT
      LAYER M5 ;
        RECT  47.76 53.916 47.784 54 ;
    END
  END kin[278]
  PIN kin[279]
    DIRECTION OUTPUT ;
    USE SIGNAL ;
    PORT
      LAYER M5 ;
        RECT  47.856 53.916 47.88 54 ;
    END
  END kin[279]
  PIN kin[27]
    DIRECTION OUTPUT ;
    USE SIGNAL ;
    PORT
      LAYER M3 ;
        RECT  3.996 53.963 4.014 54 ;
    END
  END kin[27]
  PIN kin[280]
    DIRECTION OUTPUT ;
    USE SIGNAL ;
    PORT
      LAYER M5 ;
        RECT  47.952 53.916 47.976 54 ;
    END
  END kin[280]
  PIN kin[281]
    DIRECTION OUTPUT ;
    USE SIGNAL ;
    PORT
      LAYER M5 ;
        RECT  48.048 53.916 48.072 54 ;
    END
  END kin[281]
  PIN kin[282]
    DIRECTION OUTPUT ;
    USE SIGNAL ;
    PORT
      LAYER M5 ;
        RECT  48.144 53.916 48.168 54 ;
    END
  END kin[282]
  PIN kin[283]
    DIRECTION OUTPUT ;
    USE SIGNAL ;
    PORT
      LAYER M5 ;
        RECT  48.24 53.916 48.264 54 ;
    END
  END kin[283]
  PIN kin[284]
    DIRECTION OUTPUT ;
    USE SIGNAL ;
    PORT
      LAYER M5 ;
        RECT  48.336 53.916 48.36 54 ;
    END
  END kin[284]
  PIN kin[285]
    DIRECTION OUTPUT ;
    USE SIGNAL ;
    PORT
      LAYER M5 ;
        RECT  48.432 53.916 48.456 54 ;
    END
  END kin[285]
  PIN kin[286]
    DIRECTION OUTPUT ;
    USE SIGNAL ;
    PORT
      LAYER M5 ;
        RECT  48.528 53.916 48.552 54 ;
    END
  END kin[286]
  PIN kin[287]
    DIRECTION OUTPUT ;
    USE SIGNAL ;
    PORT
      LAYER M5 ;
        RECT  48.624 53.916 48.648 54 ;
    END
  END kin[287]
  PIN kin[288]
    DIRECTION OUTPUT ;
    USE SIGNAL ;
    PORT
      LAYER M5 ;
        RECT  29.52 53.916 29.544 54 ;
    END
  END kin[288]
  PIN kin[289]
    DIRECTION OUTPUT ;
    USE SIGNAL ;
    PORT
      LAYER M5 ;
        RECT  29.616 53.916 29.64 54 ;
    END
  END kin[289]
  PIN kin[28]
    DIRECTION OUTPUT ;
    USE SIGNAL ;
    PORT
      LAYER M3 ;
        RECT  4.068 53.963 4.086 54 ;
    END
  END kin[28]
  PIN kin[290]
    DIRECTION OUTPUT ;
    USE SIGNAL ;
    PORT
      LAYER M5 ;
        RECT  29.712 53.916 29.736 54 ;
    END
  END kin[290]
  PIN kin[291]
    DIRECTION OUTPUT ;
    USE SIGNAL ;
    PORT
      LAYER M5 ;
        RECT  29.808 53.916 29.832 54 ;
    END
  END kin[291]
  PIN kin[292]
    DIRECTION OUTPUT ;
    USE SIGNAL ;
    PORT
      LAYER M5 ;
        RECT  29.904 53.916 29.928 54 ;
    END
  END kin[292]
  PIN kin[293]
    DIRECTION OUTPUT ;
    USE SIGNAL ;
    PORT
      LAYER M5 ;
        RECT  30 53.916 30.024 54 ;
    END
  END kin[293]
  PIN kin[294]
    DIRECTION OUTPUT ;
    USE SIGNAL ;
    PORT
      LAYER M5 ;
        RECT  30.096 53.916 30.12 54 ;
    END
  END kin[294]
  PIN kin[295]
    DIRECTION OUTPUT ;
    USE SIGNAL ;
    PORT
      LAYER M5 ;
        RECT  30.192 53.916 30.216 54 ;
    END
  END kin[295]
  PIN kin[296]
    DIRECTION OUTPUT ;
    USE SIGNAL ;
    PORT
      LAYER M5 ;
        RECT  30.288 53.916 30.312 54 ;
    END
  END kin[296]
  PIN kin[297]
    DIRECTION OUTPUT ;
    USE SIGNAL ;
    PORT
      LAYER M5 ;
        RECT  30.384 53.916 30.408 54 ;
    END
  END kin[297]
  PIN kin[298]
    DIRECTION OUTPUT ;
    USE SIGNAL ;
    PORT
      LAYER M5 ;
        RECT  30.48 53.916 30.504 54 ;
    END
  END kin[298]
  PIN kin[299]
    DIRECTION OUTPUT ;
    USE SIGNAL ;
    PORT
      LAYER M5 ;
        RECT  30.576 53.916 30.6 54 ;
    END
  END kin[299]
  PIN kin[29]
    DIRECTION OUTPUT ;
    USE SIGNAL ;
    PORT
      LAYER M3 ;
        RECT  4.14 53.963 4.158 54 ;
    END
  END kin[29]
  PIN kin[2]
    DIRECTION OUTPUT ;
    USE SIGNAL ;
    PORT
      LAYER M3 ;
        RECT  2.196 53.963 2.214 54 ;
    END
  END kin[2]
  PIN kin[300]
    DIRECTION OUTPUT ;
    USE SIGNAL ;
    PORT
      LAYER M5 ;
        RECT  30.672 53.916 30.696 54 ;
    END
  END kin[300]
  PIN kin[301]
    DIRECTION OUTPUT ;
    USE SIGNAL ;
    PORT
      LAYER M5 ;
        RECT  30.768 53.916 30.792 54 ;
    END
  END kin[301]
  PIN kin[302]
    DIRECTION OUTPUT ;
    USE SIGNAL ;
    PORT
      LAYER M5 ;
        RECT  30.864 53.916 30.888 54 ;
    END
  END kin[302]
  PIN kin[303]
    DIRECTION OUTPUT ;
    USE SIGNAL ;
    PORT
      LAYER M5 ;
        RECT  30.96 53.916 30.984 54 ;
    END
  END kin[303]
  PIN kin[304]
    DIRECTION OUTPUT ;
    USE SIGNAL ;
    PORT
      LAYER M5 ;
        RECT  31.056 53.916 31.08 54 ;
    END
  END kin[304]
  PIN kin[305]
    DIRECTION OUTPUT ;
    USE SIGNAL ;
    PORT
      LAYER M5 ;
        RECT  31.152 53.916 31.176 54 ;
    END
  END kin[305]
  PIN kin[306]
    DIRECTION OUTPUT ;
    USE SIGNAL ;
    PORT
      LAYER M5 ;
        RECT  31.248 53.916 31.272 54 ;
    END
  END kin[306]
  PIN kin[307]
    DIRECTION OUTPUT ;
    USE SIGNAL ;
    PORT
      LAYER M5 ;
        RECT  31.344 53.916 31.368 54 ;
    END
  END kin[307]
  PIN kin[308]
    DIRECTION OUTPUT ;
    USE SIGNAL ;
    PORT
      LAYER M5 ;
        RECT  31.44 53.916 31.464 54 ;
    END
  END kin[308]
  PIN kin[309]
    DIRECTION OUTPUT ;
    USE SIGNAL ;
    PORT
      LAYER M5 ;
        RECT  31.536 53.916 31.56 54 ;
    END
  END kin[309]
  PIN kin[30]
    DIRECTION OUTPUT ;
    USE SIGNAL ;
    PORT
      LAYER M3 ;
        RECT  4.212 53.963 4.23 54 ;
    END
  END kin[30]
  PIN kin[310]
    DIRECTION OUTPUT ;
    USE SIGNAL ;
    PORT
      LAYER M5 ;
        RECT  31.632 53.916 31.656 54 ;
    END
  END kin[310]
  PIN kin[311]
    DIRECTION OUTPUT ;
    USE SIGNAL ;
    PORT
      LAYER M5 ;
        RECT  31.728 53.916 31.752 54 ;
    END
  END kin[311]
  PIN kin[312]
    DIRECTION OUTPUT ;
    USE SIGNAL ;
    PORT
      LAYER M5 ;
        RECT  31.824 53.916 31.848 54 ;
    END
  END kin[312]
  PIN kin[313]
    DIRECTION OUTPUT ;
    USE SIGNAL ;
    PORT
      LAYER M5 ;
        RECT  31.92 53.916 31.944 54 ;
    END
  END kin[313]
  PIN kin[314]
    DIRECTION OUTPUT ;
    USE SIGNAL ;
    PORT
      LAYER M5 ;
        RECT  32.016 53.916 32.04 54 ;
    END
  END kin[314]
  PIN kin[315]
    DIRECTION OUTPUT ;
    USE SIGNAL ;
    PORT
      LAYER M5 ;
        RECT  32.112 53.916 32.136 54 ;
    END
  END kin[315]
  PIN kin[316]
    DIRECTION OUTPUT ;
    USE SIGNAL ;
    PORT
      LAYER M5 ;
        RECT  32.208 53.916 32.232 54 ;
    END
  END kin[316]
  PIN kin[317]
    DIRECTION OUTPUT ;
    USE SIGNAL ;
    PORT
      LAYER M5 ;
        RECT  32.304 53.916 32.328 54 ;
    END
  END kin[317]
  PIN kin[318]
    DIRECTION OUTPUT ;
    USE SIGNAL ;
    PORT
      LAYER M5 ;
        RECT  32.4 53.916 32.424 54 ;
    END
  END kin[318]
  PIN kin[319]
    DIRECTION OUTPUT ;
    USE SIGNAL ;
    PORT
      LAYER M5 ;
        RECT  32.496 53.916 32.52 54 ;
    END
  END kin[319]
  PIN kin[31]
    DIRECTION OUTPUT ;
    USE SIGNAL ;
    PORT
      LAYER M3 ;
        RECT  4.284 53.963 4.302 54 ;
    END
  END kin[31]
  PIN kin[320]
    DIRECTION OUTPUT ;
    USE SIGNAL ;
    PORT
      LAYER M3 ;
        RECT  28.98 53.963 28.998 54 ;
    END
  END kin[320]
  PIN kin[321]
    DIRECTION OUTPUT ;
    USE SIGNAL ;
    PORT
      LAYER M3 ;
        RECT  29.052 53.963 29.07 54 ;
    END
  END kin[321]
  PIN kin[322]
    DIRECTION OUTPUT ;
    USE SIGNAL ;
    PORT
      LAYER M3 ;
        RECT  29.124 53.963 29.142 54 ;
    END
  END kin[322]
  PIN kin[323]
    DIRECTION OUTPUT ;
    USE SIGNAL ;
    PORT
      LAYER M3 ;
        RECT  29.196 53.963 29.214 54 ;
    END
  END kin[323]
  PIN kin[324]
    DIRECTION OUTPUT ;
    USE SIGNAL ;
    PORT
      LAYER M3 ;
        RECT  29.268 53.963 29.286 54 ;
    END
  END kin[324]
  PIN kin[325]
    DIRECTION OUTPUT ;
    USE SIGNAL ;
    PORT
      LAYER M3 ;
        RECT  29.34 53.963 29.358 54 ;
    END
  END kin[325]
  PIN kin[326]
    DIRECTION OUTPUT ;
    USE SIGNAL ;
    PORT
      LAYER M3 ;
        RECT  29.412 53.963 29.43 54 ;
    END
  END kin[326]
  PIN kin[327]
    DIRECTION OUTPUT ;
    USE SIGNAL ;
    PORT
      LAYER M3 ;
        RECT  29.484 53.963 29.502 54 ;
    END
  END kin[327]
  PIN kin[328]
    DIRECTION OUTPUT ;
    USE SIGNAL ;
    PORT
      LAYER M3 ;
        RECT  29.556 53.963 29.574 54 ;
    END
  END kin[328]
  PIN kin[329]
    DIRECTION OUTPUT ;
    USE SIGNAL ;
    PORT
      LAYER M3 ;
        RECT  29.628 53.963 29.646 54 ;
    END
  END kin[329]
  PIN kin[32]
    DIRECTION OUTPUT ;
    USE SIGNAL ;
    PORT
      LAYER M3 ;
        RECT  9.54 53.963 9.558 54 ;
    END
  END kin[32]
  PIN kin[330]
    DIRECTION OUTPUT ;
    USE SIGNAL ;
    PORT
      LAYER M3 ;
        RECT  29.7 53.963 29.718 54 ;
    END
  END kin[330]
  PIN kin[331]
    DIRECTION OUTPUT ;
    USE SIGNAL ;
    PORT
      LAYER M3 ;
        RECT  29.772 53.963 29.79 54 ;
    END
  END kin[331]
  PIN kin[332]
    DIRECTION OUTPUT ;
    USE SIGNAL ;
    PORT
      LAYER M3 ;
        RECT  29.844 53.963 29.862 54 ;
    END
  END kin[332]
  PIN kin[333]
    DIRECTION OUTPUT ;
    USE SIGNAL ;
    PORT
      LAYER M3 ;
        RECT  29.916 53.963 29.934 54 ;
    END
  END kin[333]
  PIN kin[334]
    DIRECTION OUTPUT ;
    USE SIGNAL ;
    PORT
      LAYER M3 ;
        RECT  29.988 53.963 30.006 54 ;
    END
  END kin[334]
  PIN kin[335]
    DIRECTION OUTPUT ;
    USE SIGNAL ;
    PORT
      LAYER M3 ;
        RECT  30.06 53.963 30.078 54 ;
    END
  END kin[335]
  PIN kin[336]
    DIRECTION OUTPUT ;
    USE SIGNAL ;
    PORT
      LAYER M3 ;
        RECT  30.132 53.963 30.15 54 ;
    END
  END kin[336]
  PIN kin[337]
    DIRECTION OUTPUT ;
    USE SIGNAL ;
    PORT
      LAYER M3 ;
        RECT  30.204 53.963 30.222 54 ;
    END
  END kin[337]
  PIN kin[338]
    DIRECTION OUTPUT ;
    USE SIGNAL ;
    PORT
      LAYER M3 ;
        RECT  30.276 53.963 30.294 54 ;
    END
  END kin[338]
  PIN kin[339]
    DIRECTION OUTPUT ;
    USE SIGNAL ;
    PORT
      LAYER M3 ;
        RECT  30.348 53.963 30.366 54 ;
    END
  END kin[339]
  PIN kin[33]
    DIRECTION OUTPUT ;
    USE SIGNAL ;
    PORT
      LAYER M3 ;
        RECT  9.612 53.963 9.63 54 ;
    END
  END kin[33]
  PIN kin[340]
    DIRECTION OUTPUT ;
    USE SIGNAL ;
    PORT
      LAYER M3 ;
        RECT  30.42 53.963 30.438 54 ;
    END
  END kin[340]
  PIN kin[341]
    DIRECTION OUTPUT ;
    USE SIGNAL ;
    PORT
      LAYER M3 ;
        RECT  30.492 53.963 30.51 54 ;
    END
  END kin[341]
  PIN kin[342]
    DIRECTION OUTPUT ;
    USE SIGNAL ;
    PORT
      LAYER M3 ;
        RECT  30.564 53.963 30.582 54 ;
    END
  END kin[342]
  PIN kin[343]
    DIRECTION OUTPUT ;
    USE SIGNAL ;
    PORT
      LAYER M3 ;
        RECT  30.636 53.963 30.654 54 ;
    END
  END kin[343]
  PIN kin[344]
    DIRECTION OUTPUT ;
    USE SIGNAL ;
    PORT
      LAYER M3 ;
        RECT  30.708 53.963 30.726 54 ;
    END
  END kin[344]
  PIN kin[34]
    DIRECTION OUTPUT ;
    USE SIGNAL ;
    PORT
      LAYER M3 ;
        RECT  9.684 53.963 9.702 54 ;
    END
  END kin[34]
  PIN kin[35]
    DIRECTION OUTPUT ;
    USE SIGNAL ;
    PORT
      LAYER M3 ;
        RECT  9.756 53.963 9.774 54 ;
    END
  END kin[35]
  PIN kin[36]
    DIRECTION OUTPUT ;
    USE SIGNAL ;
    PORT
      LAYER M3 ;
        RECT  9.828 53.963 9.846 54 ;
    END
  END kin[36]
  PIN kin[37]
    DIRECTION OUTPUT ;
    USE SIGNAL ;
    PORT
      LAYER M3 ;
        RECT  9.9 53.963 9.918 54 ;
    END
  END kin[37]
  PIN kin[38]
    DIRECTION OUTPUT ;
    USE SIGNAL ;
    PORT
      LAYER M3 ;
        RECT  9.972 53.963 9.99 54 ;
    END
  END kin[38]
  PIN kin[39]
    DIRECTION OUTPUT ;
    USE SIGNAL ;
    PORT
      LAYER M3 ;
        RECT  10.044 53.963 10.062 54 ;
    END
  END kin[39]
  PIN kin[3]
    DIRECTION OUTPUT ;
    USE SIGNAL ;
    PORT
      LAYER M3 ;
        RECT  2.268 53.963 2.286 54 ;
    END
  END kin[3]
  PIN kin[40]
    DIRECTION OUTPUT ;
    USE SIGNAL ;
    PORT
      LAYER M3 ;
        RECT  10.116 53.963 10.134 54 ;
    END
  END kin[40]
  PIN kin[41]
    DIRECTION OUTPUT ;
    USE SIGNAL ;
    PORT
      LAYER M3 ;
        RECT  10.188 53.963 10.206 54 ;
    END
  END kin[41]
  PIN kin[42]
    DIRECTION OUTPUT ;
    USE SIGNAL ;
    PORT
      LAYER M3 ;
        RECT  10.26 53.963 10.278 54 ;
    END
  END kin[42]
  PIN kin[43]
    DIRECTION OUTPUT ;
    USE SIGNAL ;
    PORT
      LAYER M3 ;
        RECT  10.332 53.963 10.35 54 ;
    END
  END kin[43]
  PIN kin[44]
    DIRECTION OUTPUT ;
    USE SIGNAL ;
    PORT
      LAYER M3 ;
        RECT  10.404 53.963 10.422 54 ;
    END
  END kin[44]
  PIN kin[45]
    DIRECTION OUTPUT ;
    USE SIGNAL ;
    PORT
      LAYER M3 ;
        RECT  10.476 53.963 10.494 54 ;
    END
  END kin[45]
  PIN kin[46]
    DIRECTION OUTPUT ;
    USE SIGNAL ;
    PORT
      LAYER M3 ;
        RECT  10.548 53.963 10.566 54 ;
    END
  END kin[46]
  PIN kin[47]
    DIRECTION OUTPUT ;
    USE SIGNAL ;
    PORT
      LAYER M3 ;
        RECT  10.62 53.963 10.638 54 ;
    END
  END kin[47]
  PIN kin[48]
    DIRECTION OUTPUT ;
    USE SIGNAL ;
    PORT
      LAYER M3 ;
        RECT  10.692 53.963 10.71 54 ;
    END
  END kin[48]
  PIN kin[49]
    DIRECTION OUTPUT ;
    USE SIGNAL ;
    PORT
      LAYER M3 ;
        RECT  10.764 53.963 10.782 54 ;
    END
  END kin[49]
  PIN kin[4]
    DIRECTION OUTPUT ;
    USE SIGNAL ;
    PORT
      LAYER M3 ;
        RECT  2.34 53.963 2.358 54 ;
    END
  END kin[4]
  PIN kin[50]
    DIRECTION OUTPUT ;
    USE SIGNAL ;
    PORT
      LAYER M3 ;
        RECT  10.836 53.963 10.854 54 ;
    END
  END kin[50]
  PIN kin[51]
    DIRECTION OUTPUT ;
    USE SIGNAL ;
    PORT
      LAYER M3 ;
        RECT  10.908 53.963 10.926 54 ;
    END
  END kin[51]
  PIN kin[52]
    DIRECTION OUTPUT ;
    USE SIGNAL ;
    PORT
      LAYER M3 ;
        RECT  10.98 53.963 10.998 54 ;
    END
  END kin[52]
  PIN kin[53]
    DIRECTION OUTPUT ;
    USE SIGNAL ;
    PORT
      LAYER M3 ;
        RECT  11.052 53.963 11.07 54 ;
    END
  END kin[53]
  PIN kin[54]
    DIRECTION OUTPUT ;
    USE SIGNAL ;
    PORT
      LAYER M3 ;
        RECT  11.124 53.963 11.142 54 ;
    END
  END kin[54]
  PIN kin[55]
    DIRECTION OUTPUT ;
    USE SIGNAL ;
    PORT
      LAYER M3 ;
        RECT  11.196 53.963 11.214 54 ;
    END
  END kin[55]
  PIN kin[56]
    DIRECTION OUTPUT ;
    USE SIGNAL ;
    PORT
      LAYER M3 ;
        RECT  11.268 53.963 11.286 54 ;
    END
  END kin[56]
  PIN kin[57]
    DIRECTION OUTPUT ;
    USE SIGNAL ;
    PORT
      LAYER M3 ;
        RECT  11.34 53.963 11.358 54 ;
    END
  END kin[57]
  PIN kin[58]
    DIRECTION OUTPUT ;
    USE SIGNAL ;
    PORT
      LAYER M3 ;
        RECT  11.412 53.963 11.43 54 ;
    END
  END kin[58]
  PIN kin[59]
    DIRECTION OUTPUT ;
    USE SIGNAL ;
    PORT
      LAYER M3 ;
        RECT  11.484 53.963 11.502 54 ;
    END
  END kin[59]
  PIN kin[5]
    DIRECTION OUTPUT ;
    USE SIGNAL ;
    PORT
      LAYER M3 ;
        RECT  2.412 53.963 2.43 54 ;
    END
  END kin[5]
  PIN kin[60]
    DIRECTION OUTPUT ;
    USE SIGNAL ;
    PORT
      LAYER M3 ;
        RECT  11.556 53.963 11.574 54 ;
    END
  END kin[60]
  PIN kin[61]
    DIRECTION OUTPUT ;
    USE SIGNAL ;
    PORT
      LAYER M3 ;
        RECT  11.628 53.963 11.646 54 ;
    END
  END kin[61]
  PIN kin[62]
    DIRECTION OUTPUT ;
    USE SIGNAL ;
    PORT
      LAYER M3 ;
        RECT  11.7 53.963 11.718 54 ;
    END
  END kin[62]
  PIN kin[63]
    DIRECTION OUTPUT ;
    USE SIGNAL ;
    PORT
      LAYER M3 ;
        RECT  11.772 53.963 11.79 54 ;
    END
  END kin[63]
  PIN kin[64]
    DIRECTION OUTPUT ;
    USE SIGNAL ;
    PORT
      LAYER M5 ;
        RECT  13.392 53.916 13.416 54 ;
    END
  END kin[64]
  PIN kin[65]
    DIRECTION OUTPUT ;
    USE SIGNAL ;
    PORT
      LAYER M5 ;
        RECT  13.488 53.916 13.512 54 ;
    END
  END kin[65]
  PIN kin[66]
    DIRECTION OUTPUT ;
    USE SIGNAL ;
    PORT
      LAYER M5 ;
        RECT  13.584 53.916 13.608 54 ;
    END
  END kin[66]
  PIN kin[67]
    DIRECTION OUTPUT ;
    USE SIGNAL ;
    PORT
      LAYER M5 ;
        RECT  13.68 53.916 13.704 54 ;
    END
  END kin[67]
  PIN kin[68]
    DIRECTION OUTPUT ;
    USE SIGNAL ;
    PORT
      LAYER M5 ;
        RECT  13.776 53.916 13.8 54 ;
    END
  END kin[68]
  PIN kin[69]
    DIRECTION OUTPUT ;
    USE SIGNAL ;
    PORT
      LAYER M5 ;
        RECT  13.872 53.916 13.896 54 ;
    END
  END kin[69]
  PIN kin[6]
    DIRECTION OUTPUT ;
    USE SIGNAL ;
    PORT
      LAYER M3 ;
        RECT  2.484 53.963 2.502 54 ;
    END
  END kin[6]
  PIN kin[70]
    DIRECTION OUTPUT ;
    USE SIGNAL ;
    PORT
      LAYER M5 ;
        RECT  13.968 53.916 13.992 54 ;
    END
  END kin[70]
  PIN kin[71]
    DIRECTION OUTPUT ;
    USE SIGNAL ;
    PORT
      LAYER M5 ;
        RECT  14.064 53.916 14.088 54 ;
    END
  END kin[71]
  PIN kin[72]
    DIRECTION OUTPUT ;
    USE SIGNAL ;
    PORT
      LAYER M5 ;
        RECT  14.16 53.916 14.184 54 ;
    END
  END kin[72]
  PIN kin[73]
    DIRECTION OUTPUT ;
    USE SIGNAL ;
    PORT
      LAYER M5 ;
        RECT  14.256 53.916 14.28 54 ;
    END
  END kin[73]
  PIN kin[74]
    DIRECTION OUTPUT ;
    USE SIGNAL ;
    PORT
      LAYER M5 ;
        RECT  14.352 53.916 14.376 54 ;
    END
  END kin[74]
  PIN kin[75]
    DIRECTION OUTPUT ;
    USE SIGNAL ;
    PORT
      LAYER M5 ;
        RECT  14.448 53.916 14.472 54 ;
    END
  END kin[75]
  PIN kin[76]
    DIRECTION OUTPUT ;
    USE SIGNAL ;
    PORT
      LAYER M5 ;
        RECT  14.544 53.916 14.568 54 ;
    END
  END kin[76]
  PIN kin[77]
    DIRECTION OUTPUT ;
    USE SIGNAL ;
    PORT
      LAYER M5 ;
        RECT  14.64 53.916 14.664 54 ;
    END
  END kin[77]
  PIN kin[78]
    DIRECTION OUTPUT ;
    USE SIGNAL ;
    PORT
      LAYER M5 ;
        RECT  14.736 53.916 14.76 54 ;
    END
  END kin[78]
  PIN kin[79]
    DIRECTION OUTPUT ;
    USE SIGNAL ;
    PORT
      LAYER M5 ;
        RECT  14.832 53.916 14.856 54 ;
    END
  END kin[79]
  PIN kin[7]
    DIRECTION OUTPUT ;
    USE SIGNAL ;
    PORT
      LAYER M3 ;
        RECT  2.556 53.963 2.574 54 ;
    END
  END kin[7]
  PIN kin[80]
    DIRECTION OUTPUT ;
    USE SIGNAL ;
    PORT
      LAYER M5 ;
        RECT  14.928 53.916 14.952 54 ;
    END
  END kin[80]
  PIN kin[81]
    DIRECTION OUTPUT ;
    USE SIGNAL ;
    PORT
      LAYER M5 ;
        RECT  15.024 53.916 15.048 54 ;
    END
  END kin[81]
  PIN kin[82]
    DIRECTION OUTPUT ;
    USE SIGNAL ;
    PORT
      LAYER M5 ;
        RECT  15.12 53.916 15.144 54 ;
    END
  END kin[82]
  PIN kin[83]
    DIRECTION OUTPUT ;
    USE SIGNAL ;
    PORT
      LAYER M5 ;
        RECT  15.216 53.916 15.24 54 ;
    END
  END kin[83]
  PIN kin[84]
    DIRECTION OUTPUT ;
    USE SIGNAL ;
    PORT
      LAYER M5 ;
        RECT  15.312 53.916 15.336 54 ;
    END
  END kin[84]
  PIN kin[85]
    DIRECTION OUTPUT ;
    USE SIGNAL ;
    PORT
      LAYER M5 ;
        RECT  15.408 53.916 15.432 54 ;
    END
  END kin[85]
  PIN kin[86]
    DIRECTION OUTPUT ;
    USE SIGNAL ;
    PORT
      LAYER M5 ;
        RECT  15.504 53.916 15.528 54 ;
    END
  END kin[86]
  PIN kin[87]
    DIRECTION OUTPUT ;
    USE SIGNAL ;
    PORT
      LAYER M5 ;
        RECT  15.6 53.916 15.624 54 ;
    END
  END kin[87]
  PIN kin[88]
    DIRECTION OUTPUT ;
    USE SIGNAL ;
    PORT
      LAYER M5 ;
        RECT  15.696 53.916 15.72 54 ;
    END
  END kin[88]
  PIN kin[89]
    DIRECTION OUTPUT ;
    USE SIGNAL ;
    PORT
      LAYER M5 ;
        RECT  15.792 53.916 15.816 54 ;
    END
  END kin[89]
  PIN kin[8]
    DIRECTION OUTPUT ;
    USE SIGNAL ;
    PORT
      LAYER M3 ;
        RECT  2.628 53.963 2.646 54 ;
    END
  END kin[8]
  PIN kin[90]
    DIRECTION OUTPUT ;
    USE SIGNAL ;
    PORT
      LAYER M5 ;
        RECT  15.888 53.916 15.912 54 ;
    END
  END kin[90]
  PIN kin[91]
    DIRECTION OUTPUT ;
    USE SIGNAL ;
    PORT
      LAYER M5 ;
        RECT  15.984 53.916 16.008 54 ;
    END
  END kin[91]
  PIN kin[92]
    DIRECTION OUTPUT ;
    USE SIGNAL ;
    PORT
      LAYER M5 ;
        RECT  16.08 53.916 16.104 54 ;
    END
  END kin[92]
  PIN kin[93]
    DIRECTION OUTPUT ;
    USE SIGNAL ;
    PORT
      LAYER M5 ;
        RECT  16.176 53.916 16.2 54 ;
    END
  END kin[93]
  PIN kin[94]
    DIRECTION OUTPUT ;
    USE SIGNAL ;
    PORT
      LAYER M5 ;
        RECT  16.272 53.916 16.296 54 ;
    END
  END kin[94]
  PIN kin[95]
    DIRECTION OUTPUT ;
    USE SIGNAL ;
    PORT
      LAYER M5 ;
        RECT  16.368 53.916 16.392 54 ;
    END
  END kin[95]
  PIN kin[96]
    DIRECTION OUTPUT ;
    USE SIGNAL ;
    PORT
      LAYER M3 ;
        RECT  26.244 53.963 26.262 54 ;
    END
  END kin[96]
  PIN kin[97]
    DIRECTION OUTPUT ;
    USE SIGNAL ;
    PORT
      LAYER M3 ;
        RECT  26.316 53.963 26.334 54 ;
    END
  END kin[97]
  PIN kin[98]
    DIRECTION OUTPUT ;
    USE SIGNAL ;
    PORT
      LAYER M3 ;
        RECT  26.388 53.963 26.406 54 ;
    END
  END kin[98]
  PIN kin[99]
    DIRECTION OUTPUT ;
    USE SIGNAL ;
    PORT
      LAYER M3 ;
        RECT  26.46 53.963 26.478 54 ;
    END
  END kin[99]
  PIN kin[9]
    DIRECTION OUTPUT ;
    USE SIGNAL ;
    PORT
      LAYER M3 ;
        RECT  2.7 53.963 2.718 54 ;
    END
  END kin[9]
  PIN kin_sent
    DIRECTION OUTPUT ;
    USE SIGNAL ;
    PORT
      LAYER M3 ;
        RECT  30.78 53.963 30.798 54 ;
    END
  END kin_sent
  PIN ks_ord[0]
    DIRECTION INPUT ;
    USE SIGNAL ;
    PORT
      LAYER M5 ;
        RECT  10.896 0 10.92 0.084 ;
    END
  END ks_ord[0]
  PIN ks_ord[10]
    DIRECTION INPUT ;
    USE SIGNAL ;
    PORT
      LAYER M5 ;
        RECT  11.856 0 11.88 0.084 ;
    END
  END ks_ord[10]
  PIN ks_ord[11]
    DIRECTION INPUT ;
    USE SIGNAL ;
    PORT
      LAYER M5 ;
        RECT  11.952 0 11.976 0.084 ;
    END
  END ks_ord[11]
  PIN ks_ord[12]
    DIRECTION INPUT ;
    USE SIGNAL ;
    PORT
      LAYER M5 ;
        RECT  12.048 0 12.072 0.084 ;
    END
  END ks_ord[12]
  PIN ks_ord[13]
    DIRECTION INPUT ;
    USE SIGNAL ;
    PORT
      LAYER M5 ;
        RECT  12.144 0 12.168 0.084 ;
    END
  END ks_ord[13]
  PIN ks_ord[14]
    DIRECTION INPUT ;
    USE SIGNAL ;
    PORT
      LAYER M5 ;
        RECT  12.24 0 12.264 0.084 ;
    END
  END ks_ord[14]
  PIN ks_ord[15]
    DIRECTION INPUT ;
    USE SIGNAL ;
    PORT
      LAYER M5 ;
        RECT  12.336 0 12.36 0.084 ;
    END
  END ks_ord[15]
  PIN ks_ord[16]
    DIRECTION INPUT ;
    USE SIGNAL ;
    PORT
      LAYER M5 ;
        RECT  12.432 0 12.456 0.084 ;
    END
  END ks_ord[16]
  PIN ks_ord[17]
    DIRECTION INPUT ;
    USE SIGNAL ;
    PORT
      LAYER M5 ;
        RECT  12.528 0 12.552 0.084 ;
    END
  END ks_ord[17]
  PIN ks_ord[18]
    DIRECTION INPUT ;
    USE SIGNAL ;
    PORT
      LAYER M5 ;
        RECT  12.624 0 12.648 0.084 ;
    END
  END ks_ord[18]
  PIN ks_ord[19]
    DIRECTION INPUT ;
    USE SIGNAL ;
    PORT
      LAYER M5 ;
        RECT  12.72 0 12.744 0.084 ;
    END
  END ks_ord[19]
  PIN ks_ord[1]
    DIRECTION INPUT ;
    USE SIGNAL ;
    PORT
      LAYER M5 ;
        RECT  10.992 0 11.016 0.084 ;
    END
  END ks_ord[1]
  PIN ks_ord[20]
    DIRECTION INPUT ;
    USE SIGNAL ;
    PORT
      LAYER M5 ;
        RECT  12.816 0 12.84 0.084 ;
    END
  END ks_ord[20]
  PIN ks_ord[21]
    DIRECTION INPUT ;
    USE SIGNAL ;
    PORT
      LAYER M5 ;
        RECT  12.912 0 12.936 0.084 ;
    END
  END ks_ord[21]
  PIN ks_ord[2]
    DIRECTION INPUT ;
    USE SIGNAL ;
    PORT
      LAYER M5 ;
        RECT  11.088 0 11.112 0.084 ;
    END
  END ks_ord[2]
  PIN ks_ord[3]
    DIRECTION INPUT ;
    USE SIGNAL ;
    PORT
      LAYER M5 ;
        RECT  11.184 0 11.208 0.084 ;
    END
  END ks_ord[3]
  PIN ks_ord[4]
    DIRECTION INPUT ;
    USE SIGNAL ;
    PORT
      LAYER M5 ;
        RECT  11.28 0 11.304 0.084 ;
    END
  END ks_ord[4]
  PIN ks_ord[5]
    DIRECTION INPUT ;
    USE SIGNAL ;
    PORT
      LAYER M5 ;
        RECT  11.376 0 11.4 0.084 ;
    END
  END ks_ord[5]
  PIN ks_ord[6]
    DIRECTION INPUT ;
    USE SIGNAL ;
    PORT
      LAYER M5 ;
        RECT  11.472 0 11.496 0.084 ;
    END
  END ks_ord[6]
  PIN ks_ord[7]
    DIRECTION INPUT ;
    USE SIGNAL ;
    PORT
      LAYER M5 ;
        RECT  11.568 0 11.592 0.084 ;
    END
  END ks_ord[7]
  PIN ks_ord[8]
    DIRECTION INPUT ;
    USE SIGNAL ;
    PORT
      LAYER M5 ;
        RECT  11.664 0 11.688 0.084 ;
    END
  END ks_ord[8]
  PIN ks_ord[9]
    DIRECTION INPUT ;
    USE SIGNAL ;
    PORT
      LAYER M5 ;
        RECT  11.76 0 11.784 0.084 ;
    END
  END ks_ord[9]
  PIN ks_v[0]
    DIRECTION INPUT ;
    USE SIGNAL ;
    PORT
      LAYER M5 ;
        RECT  13.008 0 13.032 0.084 ;
    END
  END ks_v[0]
  PIN ks_v[1]
    DIRECTION INPUT ;
    USE SIGNAL ;
    PORT
      LAYER M5 ;
        RECT  13.104 0 13.128 0.084 ;
    END
  END ks_v[1]
  PIN ln_idle[0]
    DIRECTION INPUT ;
    USE SIGNAL ;
    PORT
      LAYER M4 ;
        RECT  64.716 50.64 64.8 50.664 ;
    END
  END ln_idle[0]
  PIN ln_idle[1]
    DIRECTION INPUT ;
    USE SIGNAL ;
    PORT
      LAYER M4 ;
        RECT  64.716 50.736 64.8 50.76 ;
    END
  END ln_idle[1]
  PIN ln_idle[2]
    DIRECTION INPUT ;
    USE SIGNAL ;
    PORT
      LAYER M4 ;
        RECT  64.716 50.832 64.8 50.856 ;
    END
  END ln_idle[2]
  PIN ln_idle[3]
    DIRECTION INPUT ;
    USE SIGNAL ;
    PORT
      LAYER M4 ;
        RECT  64.716 50.928 64.8 50.952 ;
    END
  END ln_idle[3]
  PIN ln_idle[4]
    DIRECTION INPUT ;
    USE SIGNAL ;
    PORT
      LAYER M4 ;
        RECT  64.716 51.024 64.8 51.048 ;
    END
  END ln_idle[4]
  PIN ln_idle[5]
    DIRECTION INPUT ;
    USE SIGNAL ;
    PORT
      LAYER M4 ;
        RECT  64.716 51.12 64.8 51.144 ;
    END
  END ln_idle[5]
  PIN ln_idle[6]
    DIRECTION INPUT ;
    USE SIGNAL ;
    PORT
      LAYER M4 ;
        RECT  64.716 51.216 64.8 51.24 ;
    END
  END ln_idle[6]
  PIN ln_idle[7]
    DIRECTION INPUT ;
    USE SIGNAL ;
    PORT
      LAYER M4 ;
        RECT  64.716 51.312 64.8 51.336 ;
    END
  END ln_idle[7]
  PIN n_i[0]
    DIRECTION INPUT ;
    USE SIGNAL ;
    PORT
      LAYER M4 ;
        RECT  0 49.968 0.084 49.992 ;
    END
  END n_i[0]
  PIN n_i[10]
    DIRECTION INPUT ;
    USE SIGNAL ;
    PORT
      LAYER M4 ;
        RECT  0 44.784 0.084 44.808 ;
    END
  END n_i[10]
  PIN n_i[11]
    DIRECTION INPUT ;
    USE SIGNAL ;
    PORT
      LAYER M4 ;
        RECT  0 44.88 0.084 44.904 ;
    END
  END n_i[11]
  PIN n_i[12]
    DIRECTION INPUT ;
    USE SIGNAL ;
    PORT
      LAYER M4 ;
        RECT  0 44.976 0.084 45 ;
    END
  END n_i[12]
  PIN n_i[13]
    DIRECTION INPUT ;
    USE SIGNAL ;
    PORT
      LAYER M4 ;
        RECT  0 45.072 0.084 45.096 ;
    END
  END n_i[13]
  PIN n_i[14]
    DIRECTION INPUT ;
    USE SIGNAL ;
    PORT
      LAYER M4 ;
        RECT  0 45.168 0.084 45.192 ;
    END
  END n_i[14]
  PIN n_i[15]
    DIRECTION INPUT ;
    USE SIGNAL ;
    PORT
      LAYER M4 ;
        RECT  0 45.264 0.084 45.288 ;
    END
  END n_i[15]
  PIN n_i[16]
    DIRECTION INPUT ;
    USE SIGNAL ;
    PORT
      LAYER M4 ;
        RECT  0 45.36 0.084 45.384 ;
    END
  END n_i[16]
  PIN n_i[17]
    DIRECTION INPUT ;
    USE SIGNAL ;
    PORT
      LAYER M4 ;
        RECT  0 45.456 0.084 45.48 ;
    END
  END n_i[17]
  PIN n_i[18]
    DIRECTION INPUT ;
    USE SIGNAL ;
    PORT
      LAYER M4 ;
        RECT  0 45.552 0.084 45.576 ;
    END
  END n_i[18]
  PIN n_i[19]
    DIRECTION INPUT ;
    USE SIGNAL ;
    PORT
      LAYER M4 ;
        RECT  0 45.648 0.084 45.672 ;
    END
  END n_i[19]
  PIN n_i[1]
    DIRECTION INPUT ;
    USE SIGNAL ;
    PORT
      LAYER M4 ;
        RECT  0 50.064 0.084 50.088 ;
    END
  END n_i[1]
  PIN n_i[20]
    DIRECTION INPUT ;
    USE SIGNAL ;
    PORT
      LAYER M4 ;
        RECT  0 45.744 0.084 45.768 ;
    END
  END n_i[20]
  PIN n_i[21]
    DIRECTION INPUT ;
    USE SIGNAL ;
    PORT
      LAYER M4 ;
        RECT  0 45.84 0.084 45.864 ;
    END
  END n_i[21]
  PIN n_i[22]
    DIRECTION INPUT ;
    USE SIGNAL ;
    PORT
      LAYER M4 ;
        RECT  0 45.936 0.084 45.96 ;
    END
  END n_i[22]
  PIN n_i[23]
    DIRECTION INPUT ;
    USE SIGNAL ;
    PORT
      LAYER M4 ;
        RECT  0 46.032 0.084 46.056 ;
    END
  END n_i[23]
  PIN n_i[24]
    DIRECTION INPUT ;
    USE SIGNAL ;
    PORT
      LAYER M4 ;
        RECT  0 46.128 0.084 46.152 ;
    END
  END n_i[24]
  PIN n_i[25]
    DIRECTION INPUT ;
    USE SIGNAL ;
    PORT
      LAYER M4 ;
        RECT  0 46.224 0.084 46.248 ;
    END
  END n_i[25]
  PIN n_i[26]
    DIRECTION INPUT ;
    USE SIGNAL ;
    PORT
      LAYER M4 ;
        RECT  0 46.32 0.084 46.344 ;
    END
  END n_i[26]
  PIN n_i[27]
    DIRECTION INPUT ;
    USE SIGNAL ;
    PORT
      LAYER M4 ;
        RECT  0 46.416 0.084 46.44 ;
    END
  END n_i[27]
  PIN n_i[28]
    DIRECTION INPUT ;
    USE SIGNAL ;
    PORT
      LAYER M4 ;
        RECT  0 46.512 0.084 46.536 ;
    END
  END n_i[28]
  PIN n_i[29]
    DIRECTION INPUT ;
    USE SIGNAL ;
    PORT
      LAYER M4 ;
        RECT  0 46.608 0.084 46.632 ;
    END
  END n_i[29]
  PIN n_i[2]
    DIRECTION INPUT ;
    USE SIGNAL ;
    PORT
      LAYER M4 ;
        RECT  0 50.16 0.084 50.184 ;
    END
  END n_i[2]
  PIN n_i[30]
    DIRECTION INPUT ;
    USE SIGNAL ;
    PORT
      LAYER M4 ;
        RECT  0 46.704 0.084 46.728 ;
    END
  END n_i[30]
  PIN n_i[31]
    DIRECTION INPUT ;
    USE SIGNAL ;
    PORT
      LAYER M4 ;
        RECT  0 46.8 0.084 46.824 ;
    END
  END n_i[31]
  PIN n_i[3]
    DIRECTION INPUT ;
    USE SIGNAL ;
    PORT
      LAYER M4 ;
        RECT  0 44.112 0.084 44.136 ;
    END
  END n_i[3]
  PIN n_i[4]
    DIRECTION INPUT ;
    USE SIGNAL ;
    PORT
      LAYER M4 ;
        RECT  0 44.208 0.084 44.232 ;
    END
  END n_i[4]
  PIN n_i[5]
    DIRECTION INPUT ;
    USE SIGNAL ;
    PORT
      LAYER M4 ;
        RECT  0 44.304 0.084 44.328 ;
    END
  END n_i[5]
  PIN n_i[6]
    DIRECTION INPUT ;
    USE SIGNAL ;
    PORT
      LAYER M4 ;
        RECT  0 44.4 0.084 44.424 ;
    END
  END n_i[6]
  PIN n_i[7]
    DIRECTION INPUT ;
    USE SIGNAL ;
    PORT
      LAYER M4 ;
        RECT  0 44.496 0.084 44.52 ;
    END
  END n_i[7]
  PIN n_i[8]
    DIRECTION INPUT ;
    USE SIGNAL ;
    PORT
      LAYER M4 ;
        RECT  0 44.592 0.084 44.616 ;
    END
  END n_i[8]
  PIN n_i[9]
    DIRECTION INPUT ;
    USE SIGNAL ;
    PORT
      LAYER M4 ;
        RECT  0 44.688 0.084 44.712 ;
    END
  END n_i[9]
  PIN pk_bad
    DIRECTION INPUT ;
    USE SIGNAL ;
    PORT
      LAYER M4 ;
        RECT  64.716 51.408 64.8 51.432 ;
    END
  END pk_bad
  PIN pk_done
    DIRECTION INPUT ;
    USE SIGNAL ;
    PORT
      LAYER M4 ;
        RECT  64.716 51.504 64.8 51.528 ;
    END
  END pk_done
  PIN pos_i[0]
    DIRECTION INPUT ;
    USE SIGNAL ;
    PORT
      LAYER M4 ;
        RECT  0 46.896 0.084 46.92 ;
    END
  END pos_i[0]
  PIN pos_i[10]
    DIRECTION INPUT ;
    USE SIGNAL ;
    PORT
      LAYER M4 ;
        RECT  0 6 0.084 6.024 ;
    END
  END pos_i[10]
  PIN pos_i[11]
    DIRECTION INPUT ;
    USE SIGNAL ;
    PORT
      LAYER M4 ;
        RECT  0 6.096 0.084 6.12 ;
    END
  END pos_i[11]
  PIN pos_i[12]
    DIRECTION INPUT ;
    USE SIGNAL ;
    PORT
      LAYER M4 ;
        RECT  0 6.192 0.084 6.216 ;
    END
  END pos_i[12]
  PIN pos_i[13]
    DIRECTION INPUT ;
    USE SIGNAL ;
    PORT
      LAYER M4 ;
        RECT  0 6.288 0.084 6.312 ;
    END
  END pos_i[13]
  PIN pos_i[14]
    DIRECTION INPUT ;
    USE SIGNAL ;
    PORT
      LAYER M4 ;
        RECT  0 6.384 0.084 6.408 ;
    END
  END pos_i[14]
  PIN pos_i[15]
    DIRECTION INPUT ;
    USE SIGNAL ;
    PORT
      LAYER M4 ;
        RECT  0 6.48 0.084 6.504 ;
    END
  END pos_i[15]
  PIN pos_i[16]
    DIRECTION INPUT ;
    USE SIGNAL ;
    PORT
      LAYER M4 ;
        RECT  0 6.576 0.084 6.6 ;
    END
  END pos_i[16]
  PIN pos_i[17]
    DIRECTION INPUT ;
    USE SIGNAL ;
    PORT
      LAYER M4 ;
        RECT  0 6.672 0.084 6.696 ;
    END
  END pos_i[17]
  PIN pos_i[18]
    DIRECTION INPUT ;
    USE SIGNAL ;
    PORT
      LAYER M4 ;
        RECT  0 6.768 0.084 6.792 ;
    END
  END pos_i[18]
  PIN pos_i[19]
    DIRECTION INPUT ;
    USE SIGNAL ;
    PORT
      LAYER M4 ;
        RECT  0 6.864 0.084 6.888 ;
    END
  END pos_i[19]
  PIN pos_i[1]
    DIRECTION INPUT ;
    USE SIGNAL ;
    PORT
      LAYER M4 ;
        RECT  0 46.992 0.084 47.016 ;
    END
  END pos_i[1]
  PIN pos_i[2]
    DIRECTION INPUT ;
    USE SIGNAL ;
    PORT
      LAYER M4 ;
        RECT  0 47.088 0.084 47.112 ;
    END
  END pos_i[2]
  PIN pos_i[3]
    DIRECTION INPUT ;
    USE SIGNAL ;
    PORT
      LAYER M4 ;
        RECT  0 5.328 0.084 5.352 ;
    END
  END pos_i[3]
  PIN pos_i[4]
    DIRECTION INPUT ;
    USE SIGNAL ;
    PORT
      LAYER M4 ;
        RECT  0 5.424 0.084 5.448 ;
    END
  END pos_i[4]
  PIN pos_i[5]
    DIRECTION INPUT ;
    USE SIGNAL ;
    PORT
      LAYER M4 ;
        RECT  0 5.52 0.084 5.544 ;
    END
  END pos_i[5]
  PIN pos_i[6]
    DIRECTION INPUT ;
    USE SIGNAL ;
    PORT
      LAYER M4 ;
        RECT  0 5.616 0.084 5.64 ;
    END
  END pos_i[6]
  PIN pos_i[7]
    DIRECTION INPUT ;
    USE SIGNAL ;
    PORT
      LAYER M4 ;
        RECT  0 5.712 0.084 5.736 ;
    END
  END pos_i[7]
  PIN pos_i[8]
    DIRECTION INPUT ;
    USE SIGNAL ;
    PORT
      LAYER M4 ;
        RECT  0 5.808 0.084 5.832 ;
    END
  END pos_i[8]
  PIN pos_i[9]
    DIRECTION INPUT ;
    USE SIGNAL ;
    PORT
      LAYER M4 ;
        RECT  0 5.904 0.084 5.928 ;
    END
  END pos_i[9]
  PIN qa_bad
    DIRECTION INPUT ;
    USE SIGNAL ;
    PORT
      LAYER M4 ;
        RECT  64.716 51.6 64.8 51.624 ;
    END
  END qa_bad
  PIN qa_done
    DIRECTION INPUT ;
    USE SIGNAL ;
    PORT
      LAYER M4 ;
        RECT  64.716 51.696 64.8 51.72 ;
    END
  END qa_done
  PIN rank_i[0]
    DIRECTION INPUT ;
    USE SIGNAL ;
    PORT
      LAYER M4 ;
        RECT  0 6.96 0.084 6.984 ;
    END
  END rank_i[0]
  PIN rank_i[1]
    DIRECTION INPUT ;
    USE SIGNAL ;
    PORT
      LAYER M4 ;
        RECT  0 7.056 0.084 7.08 ;
    END
  END rank_i[1]
  PIN rank_i[2]
    DIRECTION INPUT ;
    USE SIGNAL ;
    PORT
      LAYER M4 ;
        RECT  0 7.152 0.084 7.176 ;
    END
  END rank_i[2]
  PIN rank_i[3]
    DIRECTION INPUT ;
    USE SIGNAL ;
    PORT
      LAYER M4 ;
        RECT  0 7.248 0.084 7.272 ;
    END
  END rank_i[3]
  PIN rank_i[4]
    DIRECTION INPUT ;
    USE SIGNAL ;
    PORT
      LAYER M4 ;
        RECT  0 7.344 0.084 7.368 ;
    END
  END rank_i[4]
  PIN rank_i[5]
    DIRECTION INPUT ;
    USE SIGNAL ;
    PORT
      LAYER M4 ;
        RECT  0 7.44 0.084 7.464 ;
    END
  END rank_i[5]
  PIN rank_i[6]
    DIRECTION INPUT ;
    USE SIGNAL ;
    PORT
      LAYER M4 ;
        RECT  0 7.536 0.084 7.56 ;
    END
  END rank_i[6]
  PIN rg_req
    DIRECTION OUTPUT ;
    USE SIGNAL ;
    PORT
      LAYER M4 ;
        RECT  64.716 51.792 64.8 51.816 ;
    END
  END rg_req
  PIN rst_n
    DIRECTION INPUT ;
    USE SIGNAL ;
    PORT
      LAYER M4 ;
        RECT  0 7.632 0.084 7.656 ;
    END
  END rst_n
  PIN run
    DIRECTION OUTPUT ;
    USE SIGNAL ;
    PORT
      LAYER M4 ;
        RECT  64.716 51.888 64.8 51.912 ;
    END
  END run
  PIN start
    DIRECTION OUTPUT ;
    USE SIGNAL ;
    PORT
      LAYER M4 ;
        RECT  64.716 51.984 64.8 52.008 ;
    END
  END start
  PIN wp_idle
    DIRECTION INPUT ;
    USE SIGNAL ;
    PORT
      LAYER M4 ;
        RECT  64.716 52.08 64.8 52.104 ;
    END
  END wp_idle
  PIN VDD
    DIRECTION INOUT ;
    USE POWER ;
    PORT
      LAYER M5 ;
        RECT  61.992 2.151 62.112 51.849 ;
        RECT  56.592 2.151 56.712 51.849 ;
        RECT  51.192 2.151 51.312 51.849 ;
        RECT  45.792 2.151 45.912 51.849 ;
        RECT  40.392 2.151 40.512 51.849 ;
        RECT  34.992 2.151 35.112 51.849 ;
        RECT  29.592 2.151 29.712 51.849 ;
        RECT  24.192 2.151 24.312 51.849 ;
        RECT  18.792 2.151 18.912 51.849 ;
        RECT  13.392 2.151 13.512 51.849 ;
        RECT  7.992 2.151 8.112 51.849 ;
        RECT  2.592 2.151 2.712 51.849 ;
    END
  END VDD
  PIN VSS
    DIRECTION INOUT ;
    USE GROUND ;
    PORT
      LAYER M5 ;
        RECT  61.8 2.137 61.92 51.863 ;
        RECT  56.4 2.137 56.52 51.863 ;
        RECT  51 2.137 51.12 51.863 ;
        RECT  45.6 2.137 45.72 51.863 ;
        RECT  40.2 2.137 40.32 51.863 ;
        RECT  34.8 2.137 34.92 51.863 ;
        RECT  29.4 2.137 29.52 51.863 ;
        RECT  24 2.137 24.12 51.863 ;
        RECT  18.6 2.137 18.72 51.863 ;
        RECT  13.2 2.137 13.32 51.863 ;
        RECT  7.8 2.137 7.92 51.863 ;
        RECT  2.4 2.137 2.52 51.863 ;
    END
  END VSS
  # OT_OBS_CLOSED layer=M5 d_um=1.536 added=272
  OBS
    LAYER RVTN ;
     RECT  2.16 2.16 62.64 2.295 ;
     RECT  2.16 2.565 62.64 2.835 ;
     RECT  2.16 3.105 62.64 3.375 ;
     RECT  2.16 3.645 62.64 3.915 ;
     RECT  2.16 4.185 62.64 4.455 ;
     RECT  2.16 4.725 62.64 4.995 ;
     RECT  2.16 5.265 62.64 5.535 ;
     RECT  2.16 5.805 62.64 6.075 ;
     RECT  2.16 6.345 62.64 6.615 ;
     RECT  2.16 6.885 62.64 7.155 ;
     RECT  2.16 7.425 62.64 7.695 ;
     RECT  2.16 7.965 62.64 8.235 ;
     RECT  2.16 8.505 62.64 8.775 ;
     RECT  2.16 9.045 62.64 9.315 ;
     RECT  2.16 9.585 62.64 9.855 ;
     RECT  2.16 10.125 62.64 10.395 ;
     RECT  2.16 10.665 62.64 10.935 ;
     RECT  2.16 11.205 62.64 11.475 ;
     RECT  2.16 11.745 62.64 12.015 ;
     RECT  2.16 12.285 62.64 12.555 ;
     RECT  2.16 12.825 62.64 13.095 ;
     RECT  2.16 13.365 62.64 13.635 ;
     RECT  2.16 13.905 62.64 14.175 ;
     RECT  2.16 14.445 62.64 14.715 ;
     RECT  2.16 14.985 62.64 15.255 ;
     RECT  2.16 15.525 62.64 15.795 ;
     RECT  2.16 16.065 62.64 16.335 ;
     RECT  2.16 16.605 62.64 16.875 ;
     RECT  2.16 17.145 62.64 17.415 ;
     RECT  2.16 17.685 62.64 17.955 ;
     RECT  2.16 18.225 62.64 18.495 ;
     RECT  2.16 18.765 62.64 19.035 ;
     RECT  2.16 19.305 62.64 19.575 ;
     RECT  2.16 19.845 62.64 20.115 ;
     RECT  2.16 20.385 62.64 20.655 ;
     RECT  2.16 20.925 62.64 21.195 ;
     RECT  2.16 21.465 62.64 21.735 ;
     RECT  2.16 22.005 62.64 22.275 ;
     RECT  2.16 22.545 62.64 22.815 ;
     RECT  2.16 23.085 62.64 23.355 ;
     RECT  2.16 23.625 62.64 23.895 ;
     RECT  2.16 24.165 62.64 24.435 ;
     RECT  2.16 24.705 62.64 24.975 ;
     RECT  2.16 25.245 62.64 25.515 ;
     RECT  2.16 25.785 62.64 26.055 ;
     RECT  2.16 26.325 62.64 26.595 ;
     RECT  2.16 26.865 62.64 27.135 ;
     RECT  2.16 27.405 62.64 27.675 ;
     RECT  2.16 27.945 62.64 28.215 ;
     RECT  2.16 28.485 62.64 28.755 ;
     RECT  2.16 29.025 62.64 29.295 ;
     RECT  2.16 29.565 62.64 29.835 ;
     RECT  2.16 30.105 62.64 30.375 ;
     RECT  2.16 30.645 62.64 30.915 ;
     RECT  2.16 31.185 62.64 31.455 ;
     RECT  2.16 31.725 62.64 31.995 ;
     RECT  2.16 32.265 62.64 32.535 ;
     RECT  2.16 32.805 62.64 33.075 ;
     RECT  2.16 33.345 62.64 33.615 ;
     RECT  2.16 33.885 62.64 34.155 ;
     RECT  2.16 34.425 62.64 34.695 ;
     RECT  2.16 34.965 62.64 35.235 ;
     RECT  2.16 35.505 62.64 35.775 ;
     RECT  2.16 36.045 62.64 36.315 ;
     RECT  2.16 36.585 62.64 36.855 ;
     RECT  2.16 37.125 62.64 37.395 ;
     RECT  2.16 37.665 62.64 37.935 ;
     RECT  2.16 38.205 62.64 38.475 ;
     RECT  2.16 38.745 62.64 39.015 ;
     RECT  2.16 39.285 62.64 39.555 ;
     RECT  2.16 39.825 62.64 40.095 ;
     RECT  2.16 40.365 62.64 40.635 ;
     RECT  2.16 40.905 62.64 41.175 ;
     RECT  2.16 41.445 62.64 41.715 ;
     RECT  2.16 41.985 62.64 42.255 ;
     RECT  2.16 42.525 62.64 42.795 ;
     RECT  2.16 43.065 62.64 43.335 ;
     RECT  2.16 43.605 62.64 43.875 ;
     RECT  2.16 44.145 62.64 44.415 ;
     RECT  2.16 44.685 62.64 44.955 ;
     RECT  2.16 45.225 62.64 45.495 ;
     RECT  2.16 45.765 62.64 46.035 ;
     RECT  2.16 46.305 62.64 46.575 ;
     RECT  2.16 46.845 62.64 47.115 ;
     RECT  2.16 47.385 62.64 47.655 ;
     RECT  2.16 47.925 62.64 48.195 ;
     RECT  2.16 48.465 62.64 48.735 ;
     RECT  2.16 49.005 62.64 49.275 ;
     RECT  2.16 49.545 62.64 49.815 ;
     RECT  2.16 50.085 62.64 50.355 ;
     RECT  2.16 50.625 62.64 50.895 ;
     RECT  2.16 51.165 62.64 51.435 ;
     RECT  2.16 51.705 62.64 51.84 ;
    LAYER RVTP ;
     RECT  2.16 2.295 62.64 2.565 ;
     RECT  2.16 2.835 62.64 3.105 ;
     RECT  2.16 3.375 62.64 3.645 ;
     RECT  2.16 3.915 62.64 4.185 ;
     RECT  2.16 4.455 62.64 4.725 ;
     RECT  2.16 4.995 62.64 5.265 ;
     RECT  2.16 5.535 62.64 5.805 ;
     RECT  2.16 6.075 62.64 6.345 ;
     RECT  2.16 6.615 62.64 6.885 ;
     RECT  2.16 7.155 62.64 7.425 ;
     RECT  2.16 7.695 62.64 7.965 ;
     RECT  2.16 8.235 62.64 8.505 ;
     RECT  2.16 8.775 62.64 9.045 ;
     RECT  2.16 9.315 62.64 9.585 ;
     RECT  2.16 9.855 62.64 10.125 ;
     RECT  2.16 10.395 62.64 10.665 ;
     RECT  2.16 10.935 62.64 11.205 ;
     RECT  2.16 11.475 62.64 11.745 ;
     RECT  2.16 12.015 62.64 12.285 ;
     RECT  2.16 12.555 62.64 12.825 ;
     RECT  2.16 13.095 62.64 13.365 ;
     RECT  2.16 13.635 62.64 13.905 ;
     RECT  2.16 14.175 62.64 14.445 ;
     RECT  2.16 14.715 62.64 14.985 ;
     RECT  2.16 15.255 62.64 15.525 ;
     RECT  2.16 15.795 62.64 16.065 ;
     RECT  2.16 16.335 62.64 16.605 ;
     RECT  2.16 16.875 62.64 17.145 ;
     RECT  2.16 17.415 62.64 17.685 ;
     RECT  2.16 17.955 62.64 18.225 ;
     RECT  2.16 18.495 62.64 18.765 ;
     RECT  2.16 19.035 62.64 19.305 ;
     RECT  2.16 19.575 62.64 19.845 ;
     RECT  2.16 20.115 62.64 20.385 ;
     RECT  2.16 20.655 62.64 20.925 ;
     RECT  2.16 21.195 62.64 21.465 ;
     RECT  2.16 21.735 62.64 22.005 ;
     RECT  2.16 22.275 62.64 22.545 ;
     RECT  2.16 22.815 62.64 23.085 ;
     RECT  2.16 23.355 62.64 23.625 ;
     RECT  2.16 23.895 62.64 24.165 ;
     RECT  2.16 24.435 62.64 24.705 ;
     RECT  2.16 24.975 62.64 25.245 ;
     RECT  2.16 25.515 62.64 25.785 ;
     RECT  2.16 26.055 62.64 26.325 ;
     RECT  2.16 26.595 62.64 26.865 ;
     RECT  2.16 27.135 62.64 27.405 ;
     RECT  2.16 27.675 62.64 27.945 ;
     RECT  2.16 28.215 62.64 28.485 ;
     RECT  2.16 28.755 62.64 29.025 ;
     RECT  2.16 29.295 62.64 29.565 ;
     RECT  2.16 29.835 62.64 30.105 ;
     RECT  2.16 30.375 62.64 30.645 ;
     RECT  2.16 30.915 62.64 31.185 ;
     RECT  2.16 31.455 62.64 31.725 ;
     RECT  2.16 31.995 62.64 32.265 ;
     RECT  2.16 32.535 62.64 32.805 ;
     RECT  2.16 33.075 62.64 33.345 ;
     RECT  2.16 33.615 62.64 33.885 ;
     RECT  2.16 34.155 62.64 34.425 ;
     RECT  2.16 34.695 62.64 34.965 ;
     RECT  2.16 35.235 62.64 35.505 ;
     RECT  2.16 35.775 62.64 36.045 ;
     RECT  2.16 36.315 62.64 36.585 ;
     RECT  2.16 36.855 62.64 37.125 ;
     RECT  2.16 37.395 62.64 37.665 ;
     RECT  2.16 37.935 62.64 38.205 ;
     RECT  2.16 38.475 62.64 38.745 ;
     RECT  2.16 39.015 62.64 39.285 ;
     RECT  2.16 39.555 62.64 39.825 ;
     RECT  2.16 40.095 62.64 40.365 ;
     RECT  2.16 40.635 62.64 40.905 ;
     RECT  2.16 41.175 62.64 41.445 ;
     RECT  2.16 41.715 62.64 41.985 ;
     RECT  2.16 42.255 62.64 42.525 ;
     RECT  2.16 42.795 62.64 43.065 ;
     RECT  2.16 43.335 62.64 43.605 ;
     RECT  2.16 43.875 62.64 44.145 ;
     RECT  2.16 44.415 62.64 44.685 ;
     RECT  2.16 44.955 62.64 45.225 ;
     RECT  2.16 45.495 62.64 45.765 ;
     RECT  2.16 46.035 62.64 46.305 ;
     RECT  2.16 46.575 62.64 46.845 ;
     RECT  2.16 47.115 62.64 47.385 ;
     RECT  2.16 47.655 62.64 47.925 ;
     RECT  2.16 48.195 62.64 48.465 ;
     RECT  2.16 48.735 62.64 49.005 ;
     RECT  2.16 49.275 62.64 49.545 ;
     RECT  2.16 49.815 62.64 50.085 ;
     RECT  2.16 50.355 62.64 50.625 ;
     RECT  2.16 50.895 62.64 51.165 ;
     RECT  2.16 51.435 62.64 51.705 ;
    LAYER M1 ;
     RECT  2.16 2.151 62.64 51.849 ;
    LAYER M2 ;
     RECT  0.067 45.468 0.103 45.486 ;
     RECT  0.067 46.656 0.103 46.674 ;
     RECT  0.067 48.24 0.103 48.258 ;
     RECT  0.103 4.464 0.139 4.482 ;
     RECT  0.103 44.352 0.139 44.37 ;
     RECT  0.103 45.468 0.139 45.558 ;
     RECT  0.103 46.656 0.139 48.96 ;
     RECT  0.139 45.468 0.167 49.338 ;
     RECT  0.139 4.464 0.175 4.518 ;
     RECT  0.175 4.194 0.211 4.518 ;
     RECT  0.067 41.76 0.211 41.778 ;
     RECT  0.139 44.352 0.211 44.712 ;
     RECT  0.167 45.468 0.211 48.024 ;
     RECT  0.211 4.194 0.247 4.788 ;
     RECT  0.247 4.194 0.283 5.022 ;
     RECT  0.283 43.11 0.319 43.128 ;
     RECT  0.211 44.352 0.319 48.024 ;
     RECT  0.283 4.194 0.535 5.058 ;
     RECT  0.167 48.816 0.535 49.338 ;
     RECT  0.823 39.87 1.399 39.888 ;
     RECT  1.399 39.798 1.471 39.888 ;
     RECT  0.031 40.95 1.507 40.968 ;
     RECT  2.047 50.796 2.155 51.192 ;
     RECT  0.535 4.194 2.16 5.256 ;
     RECT  0.535 6.696 2.16 6.714 ;
     RECT  1.975 38.718 2.16 38.736 ;
     RECT  1.471 39.6 2.16 39.888 ;
     RECT  1.507 40.68 2.16 40.968 ;
     RECT  0.211 41.76 2.16 42.318 ;
     RECT  0.319 43.11 2.16 48.024 ;
     RECT  0.535 48.816 2.16 49.842 ;
     RECT  2.155 50.598 2.16 51.192 ;
     RECT  2.16 2.151 2.407 51.849 ;
     RECT  2.407 2.151 2.623 52.002 ;
     RECT  2.623 2.151 3.343 52.47 ;
     RECT  3.343 2.151 3.775 53.046 ;
     RECT  3.775 2.106 3.839 53.046 ;
     RECT  3.839 2.106 3.983 51.849 ;
     RECT  3.839 53.028 4.063 53.046 ;
     RECT  4.063 53.028 4.487 53.118 ;
     RECT  4.487 53.1 4.631 53.118 ;
     RECT  5.935 0.036 6.043 0.234 ;
     RECT  6.043 0.036 6.467 0.279 ;
     RECT  6.727 1.152 6.827 1.17 ;
     RECT  3.983 2.151 7.015 51.849 ;
     RECT  6.467 0.036 7.231 0.054 ;
     RECT  7.015 1.728 7.259 51.849 ;
     RECT  7.231 0.036 7.267 0.126 ;
     RECT  7.267 0.036 8.087 0.198 ;
     RECT  7.259 2.106 8.123 51.849 ;
     RECT  8.995 0.036 9.175 0.054 ;
     RECT  8.123 2.151 9.247 51.849 ;
     RECT  9.175 0.036 9.535 0.126 ;
     RECT  9.247 1.728 9.563 51.849 ;
     RECT  9.535 0.036 9.635 0.162 ;
     RECT  9.635 0.036 9.995 0.126 ;
     RECT  9.995 0.108 10.247 0.126 ;
     RECT  10.327 53.874 10.399 53.892 ;
     RECT  10.399 53.874 10.535 53.964 ;
     RECT  10.535 53.874 10.679 53.892 ;
     RECT  9.563 2.151 11.911 51.849 ;
     RECT  10.543 53.028 12.659 53.046 ;
     RECT  11.911 2.106 14.315 51.849 ;
     RECT  26.239 53.874 26.311 53.892 ;
     RECT  26.311 53.874 26.339 53.964 ;
     RECT  26.339 53.946 26.447 53.964 ;
     RECT  27.751 53.028 28.219 53.046 ;
     RECT  28.219 53.028 28.355 53.118 ;
     RECT  14.315 2.151 28.723 51.849 ;
     RECT  28.723 2.151 29.291 51.966 ;
     RECT  28.355 53.028 29.335 53.046 ;
     RECT  29.335 52.956 29.363 53.046 ;
     RECT  29.291 2.151 29.507 51.93 ;
     RECT  29.363 52.956 29.579 52.974 ;
     RECT  29.875 53.946 30.731 53.964 ;
     RECT  30.595 52.992 30.775 53.01 ;
     RECT  30.775 52.956 31.343 53.01 ;
     RECT  31.343 52.992 31.415 53.01 ;
     RECT  29.507 2.151 38.767 51.849 ;
     RECT  38.803 53.946 38.839 53.964 ;
     RECT  38.767 2.151 38.867 51.966 ;
     RECT  38.839 53.874 38.939 53.964 ;
     RECT  38.939 53.874 39.703 53.892 ;
     RECT  39.703 53.874 39.731 53.964 ;
     RECT  39.731 53.946 39.839 53.964 ;
     RECT  38.867 2.151 40.279 51.849 ;
     RECT  40.207 53.028 40.279 53.046 ;
     RECT  40.279 2.151 40.775 53.046 ;
     RECT  40.775 53.028 41.099 53.046 ;
     RECT  56.047 52.911 56.119 52.929 ;
     RECT  54.967 53.946 56.479 53.964 ;
     RECT  56.479 53.874 56.579 53.964 ;
     RECT  56.119 52.911 56.795 53.01 ;
     RECT  56.795 52.992 56.903 53.01 ;
     RECT  40.775 2.151 56.983 51.849 ;
     RECT  56.983 2.151 57.587 51.894 ;
     RECT  57.919 52.911 57.955 52.929 ;
     RECT  57.955 52.911 58.091 53.01 ;
     RECT  57.587 2.151 58.495 51.849 ;
     RECT  58.091 52.992 58.927 53.01 ;
     RECT  58.495 2.151 59.027 51.894 ;
     RECT  58.927 52.911 59.243 53.01 ;
     RECT  59.243 52.992 59.711 53.01 ;
     RECT  60.511 53.028 61.015 53.046 ;
     RECT  61.015 52.992 61.231 53.046 ;
     RECT  59.027 2.151 61.411 51.849 ;
     RECT  61.231 52.956 61.663 53.046 ;
     RECT  61.663 52.911 61.807 53.046 ;
     RECT  61.411 2.151 61.907 51.93 ;
     RECT  61.807 52.911 62.231 53.082 ;
     RECT  61.907 2.151 62.64 51.849 ;
     RECT  62.64 43.614 62.663 51.768 ;
     RECT  62.231 52.956 62.663 53.082 ;
     RECT  62.663 52.956 62.735 53.046 ;
     RECT  62.735 52.992 62.771 53.046 ;
     RECT  62.663 43.614 62.843 43.794 ;
     RECT  62.663 44.622 62.879 51.768 ;
     RECT  62.64 38.016 62.951 38.034 ;
     RECT  62.64 42.732 62.987 42.75 ;
     RECT  62.879 44.694 62.987 51.768 ;
     RECT  62.771 53.028 63.023 53.046 ;
     RECT  62.987 44.694 63.059 49.806 ;
     RECT  62.843 43.776 63.095 43.794 ;
     RECT  62.987 50.634 63.131 51.768 ;
     RECT  63.131 50.634 63.275 51.192 ;
     RECT  63.059 46.584 63.311 49.806 ;
     RECT  63.059 44.694 63.563 45.558 ;
     RECT  63.563 45.54 63.635 45.558 ;
     RECT  63.563 44.694 63.671 44.712 ;
     RECT  63.311 46.584 63.707 49.032 ;
     RECT  63.707 46.854 63.851 49.032 ;
     RECT  63.851 46.926 63.887 48.456 ;
     RECT  63.275 50.634 63.887 51.12 ;
     RECT  63.311 49.788 63.923 49.806 ;
     RECT  63.887 47.16 63.959 48.456 ;
     RECT  63.887 51.102 64.651 51.12 ;
     RECT  64.651 51.102 64.687 51.309 ;
     RECT  63.959 47.16 64.751 47.88 ;
     RECT  64.687 50.832 64.751 51.309 ;
     RECT  64.751 47.16 64.787 47.178 ;
     RECT  64.751 50.832 64.787 50.85 ;
    LAYER M3 ;
     RECT  5.148 0.012 9.702 0.031 ;
     RECT  5.148 0.031 9.99 0.103 ;
     RECT  10.836 0.091 11.142 0.103 ;
     RECT  31.608 0.091 31.626 0.139 ;
     RECT  32.94 0.091 35.01 0.139 ;
     RECT  32.94 0.139 35.154 0.235 ;
     RECT  5.148 0.103 11.142 0.475 ;
     RECT  5.148 0.475 11.646 0.523 ;
     RECT  5.148 0.523 11.862 1.051 ;
     RECT  5.148 1.051 12.402 1.099 ;
     RECT  5.148 1.099 12.618 1.723 ;
     RECT  32.94 0.235 35.19 1.723 ;
     RECT  5.148 1.723 13.05 1.771 ;
     RECT  31.608 0.139 32.13 1.771 ;
     RECT  32.904 1.723 35.19 1.771 ;
     RECT  5.148 1.771 13.122 2.143 ;
     RECT  2.415 2.143 2.505 2.191 ;
     RECT  3.78 2.101 3.978 2.191 ;
     RECT  5.148 2.143 13.305 2.191 ;
     RECT  14.292 2.101 14.31 2.191 ;
     RECT  2.415 2.191 2.754 2.227 ;
     RECT  3.78 2.191 4.374 2.227 ;
     RECT  2.415 2.227 4.374 2.263 ;
     RECT  5.148 2.191 14.31 2.263 ;
     RECT  16.38 2.263 16.398 2.371 ;
     RECT  18.615 2.143 18.705 2.413 ;
     RECT  24.015 2.143 24.105 2.413 ;
     RECT  29.415 2.143 29.505 2.413 ;
     RECT  40.215 2.143 40.305 2.413 ;
     RECT  45.615 2.143 45.705 2.413 ;
     RECT  51.015 2.143 51.105 2.413 ;
     RECT  56.415 2.143 56.505 2.413 ;
     RECT  61.815 2.143 61.905 2.413 ;
     RECT  2.415 2.263 14.31 2.497 ;
     RECT  28.224 2.461 28.242 2.533 ;
     RECT  48.168 2.461 48.33 2.569 ;
     RECT  16.38 2.371 16.542 2.605 ;
     RECT  28.08 2.533 28.242 2.605 ;
     RECT  48.168 2.569 48.474 2.605 ;
     RECT  21.636 2.605 21.654 2.635 ;
     RECT  2.415 2.497 14.382 2.641 ;
     RECT  16.02 2.605 16.542 2.641 ;
     RECT  18.615 2.413 18.897 2.641 ;
     RECT  20.232 2.605 20.25 2.641 ;
     RECT  21.24 2.635 21.654 2.641 ;
     RECT  25.092 2.461 25.11 2.641 ;
     RECT  16.02 2.641 17.37 2.731 ;
     RECT  18.108 2.641 18.897 2.731 ;
     RECT  28.08 2.605 28.35 2.731 ;
     RECT  24.015 2.413 24.297 2.767 ;
     RECT  25.092 2.641 25.398 2.767 ;
     RECT  48.168 2.605 48.834 2.803 ;
     RECT  27.9 2.731 28.35 2.839 ;
     RECT  29.415 2.413 29.697 2.839 ;
     RECT  45.615 2.413 45.897 2.839 ;
     RECT  20.232 2.641 21.762 2.875 ;
     RECT  24.015 2.767 25.398 2.875 ;
     RECT  26.46 2.839 26.478 2.875 ;
     RECT  27.9 2.839 29.697 2.875 ;
     RECT  31.608 1.771 35.19 2.875 ;
     RECT  47.7 2.803 48.834 2.875 ;
     RECT  16.02 2.731 18.897 2.911 ;
     RECT  19.764 2.875 21.762 2.911 ;
     RECT  30.816 2.839 30.834 2.911 ;
     RECT  15.984 2.911 18.954 2.971 ;
     RECT  30.78 2.911 30.87 3.001 ;
     RECT  31.608 2.875 35.298 3.001 ;
     RECT  39.456 2.911 39.474 3.001 ;
     RECT  40.215 2.413 40.497 3.001 ;
     RECT  42.768 2.911 42.786 3.001 ;
     RECT  47.628 2.875 49.41 3.001 ;
     RECT  15.876 2.971 18.954 3.019 ;
     RECT  2.415 2.641 14.922 3.037 ;
     RECT  15.876 3.019 19.026 3.037 ;
     RECT  42.768 3.001 42.93 3.109 ;
     RECT  45.324 2.839 45.897 3.109 ;
     RECT  46.764 2.839 46.782 3.109 ;
     RECT  39.456 3.001 40.497 3.145 ;
     RECT  41.508 2.875 41.526 3.145 ;
     RECT  24.015 2.875 26.478 3.181 ;
     RECT  39.276 3.145 40.497 3.181 ;
     RECT  41.292 3.145 41.526 3.181 ;
     RECT  47.556 3.001 49.41 3.181 ;
     RECT  53.316 3.145 53.334 3.181 ;
     RECT  27.324 2.875 29.826 3.271 ;
     RECT  30.78 3.001 35.298 3.271 ;
     RECT  19.764 2.911 22.302 3.299 ;
     RECT  53.316 3.181 53.586 3.301 ;
     RECT  20.16 3.299 22.302 3.307 ;
     RECT  23.292 3.181 26.478 3.307 ;
     RECT  2.415 3.037 19.026 3.343 ;
     RECT  37.512 2.605 37.53 3.343 ;
     RECT  38.412 3.109 38.43 3.343 ;
     RECT  20.16 3.307 26.478 3.379 ;
     RECT  56.415 2.413 56.697 3.379 ;
     RECT  37.332 3.343 37.53 3.403 ;
     RECT  38.34 3.343 38.43 3.403 ;
     RECT  45.072 3.109 46.782 3.403 ;
     RECT  45 3.403 46.782 3.415 ;
     RECT  47.556 3.181 49.986 3.415 ;
     RECT  53.172 3.301 53.586 3.415 ;
     RECT  2.415 3.343 19.17 3.443 ;
     RECT  42.3 3.109 42.93 3.451 ;
     RECT  43.704 3.181 43.722 3.451 ;
     RECT  52.956 3.415 53.586 3.451 ;
     RECT  37.332 3.403 38.43 3.541 ;
     RECT  39.276 3.181 41.526 3.541 ;
     RECT  45 3.415 50.058 3.541 ;
     RECT  51.015 2.413 51.297 3.541 ;
     RECT  52.956 3.451 54.198 3.541 ;
     RECT  55.908 3.379 56.697 3.541 ;
     RECT  45 3.541 51.297 3.577 ;
     RECT  52.704 3.541 54.198 3.577 ;
     RECT  20.16 3.379 26.55 3.613 ;
     RECT  27.324 3.271 35.298 3.613 ;
     RECT  37.332 3.541 41.526 3.613 ;
     RECT  42.3 3.451 43.722 3.613 ;
     RECT  52.596 3.577 54.198 3.613 ;
     RECT  55.692 3.541 56.697 3.613 ;
     RECT  37.332 3.613 43.722 3.649 ;
     RECT  45 3.577 51.57 3.649 ;
     RECT  20.16 3.613 35.298 3.685 ;
     RECT  20.16 3.685 35.91 3.721 ;
     RECT  37.332 3.649 44.082 3.721 ;
     RECT  45 3.649 51.714 3.721 ;
     RECT  57.924 3.451 57.942 3.811 ;
     RECT  20.16 3.721 36.198 3.875 ;
     RECT  55.152 3.613 56.697 3.877 ;
     RECT  37.332 3.721 51.714 3.931 ;
     RECT  52.452 3.613 54.198 3.931 ;
     RECT  55.152 3.877 57.042 3.955 ;
     RECT  57.78 3.811 57.942 3.955 ;
     RECT  37.332 3.931 54.198 3.979 ;
     RECT  55.044 3.955 57.042 3.979 ;
     RECT  25.38 3.875 36.198 3.991 ;
     RECT  37.044 3.979 57.042 4.189 ;
     RECT  57.78 3.955 58.05 4.189 ;
     RECT  58.968 4.117 58.986 4.189 ;
     RECT  2.415 3.443 19.134 4.261 ;
     RECT  25.38 3.991 36.234 4.351 ;
     RECT  36.972 4.189 57.042 4.351 ;
     RECT  57.78 4.189 58.986 4.423 ;
     RECT  0.18 4.189 0.198 4.459 ;
     RECT  25.38 4.351 57.042 4.507 ;
     RECT  57.78 4.423 59.634 4.507 ;
     RECT  25.38 4.507 59.634 4.531 ;
     RECT  20.16 3.875 24.606 4.621 ;
     RECT  25.38 4.531 59.67 4.621 ;
     RECT  0.108 4.459 0.198 4.765 ;
     RECT  0.108 4.765 0.234 4.999 ;
     RECT  0.108 4.999 0.27 5.035 ;
     RECT  2.376 4.261 19.134 5.071 ;
     RECT  20.16 4.621 59.67 5.071 ;
     RECT  0.108 5.035 0.306 5.233 ;
     RECT  2.376 5.071 59.67 5.305 ;
     RECT  0.108 5.233 0.558 5.357 ;
     RECT  2.376 5.305 59.85 5.431 ;
     RECT  0.144 5.357 0.558 5.453 ;
     RECT  2.34 5.431 59.85 5.459 ;
     RECT  0.18 5.453 0.558 5.549 ;
     RECT  0.216 5.549 0.558 5.645 ;
     RECT  32.544 5.459 59.85 5.701 ;
     RECT  32.544 5.701 59.886 5.773 ;
     RECT  2.34 5.459 31.59 5.845 ;
     RECT  32.544 5.773 59.922 5.881 ;
     RECT  60.912 5.701 60.93 5.999 ;
     RECT  60.768 6.151 60.858 6.269 ;
     RECT  60.768 6.269 60.786 6.305 ;
     RECT  2.304 5.845 31.59 6.313 ;
     RECT  32.544 5.881 60.03 6.313 ;
     RECT  0.252 5.645 0.558 6.379 ;
     RECT  2.304 6.313 60.03 6.385 ;
     RECT  2.268 6.385 60.03 6.475 ;
     RECT  2.232 6.475 60.03 6.511 ;
     RECT  0.144 6.379 0.558 6.893 ;
     RECT  2.232 6.511 60.534 6.917 ;
     RECT  2.268 6.917 60.534 7.321 ;
     RECT  0.144 6.893 0.162 7.373 ;
     RECT  2.268 7.321 60.606 7.393 ;
     RECT  2.268 7.393 60.642 7.421 ;
     RECT  48.096 7.421 60.642 7.771 ;
     RECT  48.096 7.771 60.966 8.311 ;
     RECT  61.815 2.413 62.097 8.311 ;
     RECT  48.06 8.311 62.097 8.545 ;
     RECT  2.268 7.421 47.25 8.581 ;
     RECT  47.988 8.545 62.097 8.581 ;
     RECT  2.268 8.581 62.097 8.735 ;
     RECT  2.304 8.735 62.097 9.113 ;
     RECT  2.34 9.113 62.097 10.193 ;
     RECT  2.34 10.193 8.442 10.471 ;
     RECT  9.18 10.193 62.097 10.741 ;
     RECT  9.18 10.741 62.226 10.931 ;
     RECT  32.148 10.931 62.097 11.165 ;
     RECT  2.268 10.471 8.442 11.171 ;
     RECT  3.636 11.171 8.442 11.371 ;
     RECT  9.18 10.931 31.374 11.371 ;
     RECT  3.636 11.371 31.374 12.091 ;
     RECT  32.256 11.165 62.097 12.091 ;
     RECT  3.636 12.091 62.097 12.631 ;
     RECT  2.268 11.171 2.697 13.027 ;
     RECT  3.6 12.631 62.097 13.027 ;
     RECT  2.268 13.027 62.097 13.147 ;
     RECT  2.268 13.147 62.442 13.171 ;
     RECT  2.268 13.171 62.514 13.559 ;
     RECT  31.788 13.559 62.37 13.631 ;
     RECT  31.932 13.631 62.37 13.829 ;
     RECT  31.932 13.829 62.298 13.865 ;
     RECT  2.268 13.559 30.69 14.413 ;
     RECT  31.932 13.865 62.097 14.449 ;
     RECT  31.716 14.449 62.097 14.747 ;
     RECT  2.268 14.413 30.726 14.909 ;
     RECT  55.908 14.747 57.798 14.909 ;
     RECT  22.644 14.909 30.726 15.025 ;
     RECT  31.716 14.747 33.714 15.025 ;
     RECT  58.608 14.747 62.097 15.331 ;
     RECT  22.644 15.025 33.714 15.389 ;
     RECT  2.268 14.909 21.834 15.449 ;
     RECT  58.608 15.331 62.406 15.521 ;
     RECT  2.268 15.449 21.69 15.719 ;
     RECT  31.932 15.389 33.714 15.799 ;
     RECT  34.488 14.747 55.134 15.799 ;
     RECT  31.932 15.799 55.134 15.863 ;
     RECT  32.22 15.863 55.134 15.871 ;
     RECT  55.908 14.909 57.762 15.871 ;
     RECT  2.268 15.719 21.618 15.899 ;
     RECT  32.22 15.871 57.762 16.069 ;
     RECT  32.22 16.069 57.798 16.105 ;
     RECT  58.608 15.521 62.097 16.105 ;
     RECT  22.644 15.389 30.726 16.411 ;
     RECT  32.22 16.105 62.097 16.6 ;
     RECT  2.268 15.899 21.51 16.645 ;
     RECT  22.644 16.411 30.906 16.645 ;
     RECT  2.268 16.645 31.122 17.041 ;
     RECT  32.148 16.6 62.097 17.041 ;
     RECT  2.268 17.041 62.097 17.981 ;
     RECT  21.996 17.981 62.097 18.149 ;
     RECT  21.996 18.149 27.738 18.185 ;
     RECT  2.268 17.981 21.006 18.811 ;
     RECT  28.476 18.149 62.097 18.841 ;
     RECT  22.14 18.185 27.738 18.931 ;
     RECT  28.476 18.841 62.334 18.931 ;
     RECT  22.14 18.931 62.334 18.967 ;
     RECT  21.96 18.967 62.334 19.031 ;
     RECT  2.268 18.811 21.114 19.201 ;
     RECT  21.96 19.031 62.097 19.229 ;
     RECT  2.268 19.201 21.186 19.345 ;
     RECT  22.176 19.229 62.097 19.499 ;
     RECT  42.3 19.499 62.097 19.679 ;
     RECT  2.268 19.345 21.438 20.281 ;
     RECT  22.176 19.499 41.49 20.281 ;
     RECT  42.3 19.679 57.042 20.425 ;
     RECT  57.816 19.679 62.097 20.425 ;
     RECT  2.268 20.281 41.49 20.539 ;
     RECT  42.3 20.425 62.097 20.539 ;
     RECT  2.268 20.539 62.097 21.001 ;
     RECT  2.268 21.001 62.118 21.191 ;
     RECT  2.268 21.191 62.097 22.351 ;
     RECT  2.268 22.351 62.19 22.613 ;
     RECT  2.268 22.613 62.097 23.357 ;
     RECT  2.268 23.357 41.958 23.819 ;
     RECT  42.84 23.357 62.097 24.241 ;
     RECT  42.84 24.241 62.334 24.379 ;
     RECT  42.768 24.379 62.334 24.512 ;
     RECT  2.268 23.819 41.742 24.601 ;
     RECT  42.912 24.512 62.334 24.629 ;
     RECT  42.912 24.629 62.19 24.665 ;
     RECT  2.268 24.601 42.066 24.701 ;
     RECT  2.268 24.701 41.994 24.845 ;
     RECT  2.268 24.845 41.958 24.899 ;
     RECT  42.912 24.665 62.097 25.043 ;
     RECT  2.268 24.899 41.922 25.717 ;
     RECT  2.268 25.717 41.994 25.789 ;
     RECT  2.268 25.789 42.03 25.951 ;
     RECT  42.912 25.043 48.042 25.951 ;
     RECT  2.268 25.951 48.042 26.051 ;
     RECT  21.276 26.051 48.042 26.401 ;
     RECT  48.816 25.043 62.097 26.401 ;
     RECT  2.268 26.051 20.538 26.833 ;
     RECT  21.276 26.401 62.097 26.833 ;
     RECT  2.268 26.833 62.097 28.021 ;
     RECT  2.268 28.021 62.298 28.283 ;
     RECT  2.268 28.283 62.097 30.335 ;
     RECT  2.268 30.335 35.514 31.225 ;
     RECT  36.252 30.335 62.097 31.225 ;
     RECT  2.268 31.225 62.097 31.261 ;
     RECT  2.268 31.261 62.514 31.379 ;
     RECT  2.268 31.379 62.097 32.341 ;
     RECT  2.268 32.341 62.37 32.459 ;
     RECT  2.268 32.459 62.298 32.495 ;
     RECT  2.268 32.495 62.097 36.589 ;
     RECT  2.268 36.589 62.514 36.779 ;
     RECT  2.268 36.779 62.406 37.049 ;
     RECT  2.268 37.049 62.298 37.085 ;
     RECT  2.268 37.085 62.097 38.713 ;
     RECT  1.98 38.713 62.097 39.595 ;
     RECT  1.476 39.595 62.097 39.793 ;
     RECT  1.404 39.793 62.097 39.865 ;
     RECT  0.828 39.865 62.097 39.901 ;
     RECT  62.928 38.011 62.946 39.901 ;
     RECT  0.828 39.901 62.946 40.361 ;
     RECT  0.828 40.361 62.154 41.449 ;
     RECT  62.928 40.361 62.946 41.449 ;
     RECT  0.828 41.449 62.946 41.639 ;
     RECT  0.036 40.945 0.054 41.755 ;
     RECT  0.036 41.755 0.09 42.295 ;
     RECT  0.828 41.639 19.998 42.295 ;
     RECT  20.772 41.639 62.946 42.427 ;
     RECT  0.036 42.295 19.998 42.457 ;
     RECT  20.736 42.427 62.946 42.457 ;
     RECT  0.036 42.457 62.946 42.727 ;
     RECT  0.036 42.727 62.982 43.771 ;
     RECT  0.036 43.771 63.09 43.949 ;
     RECT  0.072 43.949 63.09 44.689 ;
     RECT  0.072 44.689 63.666 45.293 ;
     RECT  0.072 45.293 0.522 45.491 ;
     RECT  1.26 45.293 63.666 46.579 ;
     RECT  0.108 45.491 0.522 46.651 ;
     RECT  1.26 46.579 63.702 46.849 ;
     RECT  1.26 46.849 63.846 46.921 ;
     RECT  1.26 46.921 63.882 47.117 ;
     RECT  1.44 47.117 63.882 47.309 ;
     RECT  64.764 47.155 64.782 47.695 ;
     RECT  0.072 46.651 0.522 47.731 ;
     RECT  0.072 47.731 0.558 48.263 ;
     RECT  1.476 47.309 63.882 48.433 ;
     RECT  64.656 47.695 64.782 48.433 ;
     RECT  1.476 48.433 64.782 48.749 ;
     RECT  0.108 48.263 0.558 49.517 ;
     RECT  0.144 49.517 0.558 49.901 ;
     RECT  0.432 49.901 0.558 50.093 ;
     RECT  0.54 50.093 0.558 50.189 ;
     RECT  2.124 48.749 64.782 50.189 ;
     RECT  37.044 50.189 64.782 50.459 ;
     RECT  2.124 50.189 20.934 50.791 ;
     RECT  37.08 50.459 64.782 50.855 ;
     RECT  21.672 50.189 36.198 50.891 ;
     RECT  2.052 50.791 20.934 50.935 ;
     RECT  21.672 50.891 22.338 50.935 ;
     RECT  23.076 50.891 36.198 50.935 ;
     RECT  37.08 50.855 64.746 50.957 ;
     RECT  23.076 50.935 36.234 51.089 ;
     RECT  37.08 50.957 63.918 51.197 ;
     RECT  23.22 51.089 36.234 51.241 ;
     RECT  2.052 50.935 22.338 51.269 ;
     RECT  37.548 51.197 63.918 51.269 ;
     RECT  64.656 50.957 64.746 51.314 ;
     RECT  37.548 51.269 49.842 51.359 ;
     RECT  23.22 51.241 36.522 51.395 ;
     RECT  22.104 51.269 22.338 51.431 ;
     RECT  50.724 51.269 63.918 51.431 ;
     RECT  2.052 51.269 21.366 51.467 ;
     RECT  22.212 51.431 22.338 51.467 ;
     RECT  23.22 51.395 35.262 51.467 ;
     RECT  53.532 51.431 63.918 51.467 ;
     RECT  37.548 51.359 43.902 51.503 ;
     RECT  50.904 51.431 52.326 51.503 ;
     RECT  53.928 51.467 63.918 51.533 ;
     RECT  23.292 51.467 35.262 51.539 ;
     RECT  18 51.467 21.366 51.587 ;
     RECT  50.904 51.503 51.297 51.587 ;
     RECT  2.052 51.467 17.154 51.629 ;
     RECT  18 51.587 18.774 51.629 ;
     RECT  19.584 51.587 21.366 51.629 ;
     RECT  22.248 51.467 22.338 51.629 ;
     RECT  23.292 51.539 33.75 51.629 ;
     RECT  34.524 51.539 35.262 51.629 ;
     RECT  37.548 51.503 42.93 51.629 ;
     RECT  52.272 51.503 52.326 51.629 ;
     RECT  22.248 51.629 22.266 51.635 ;
     RECT  23.472 51.629 24.105 51.649 ;
     RECT  5.616 51.629 7.074 51.665 ;
     RECT  7.815 51.629 11.898 51.665 ;
     RECT  18 51.629 18.705 51.665 ;
     RECT  25.56 51.629 33.606 51.665 ;
     RECT  53.928 51.533 63.882 51.665 ;
     RECT  18.396 51.665 18.705 51.677 ;
     RECT  20.016 51.629 20.034 51.677 ;
     RECT  5.616 51.665 6.93 51.701 ;
     RECT  8.784 51.665 11.79 51.701 ;
     RECT  25.704 51.665 33.606 51.701 ;
     RECT  37.548 51.629 41.742 51.701 ;
     RECT  44.64 51.359 49.842 51.701 ;
     RECT  25.704 51.701 32.454 51.737 ;
     RECT  36.144 51.395 36.162 51.737 ;
     RECT  50.904 51.587 51.105 51.737 ;
     RECT  54.396 51.665 63.882 51.737 ;
     RECT  5.616 51.701 5.634 51.773 ;
     RECT  6.912 51.701 6.93 51.773 ;
     RECT  9.108 51.701 11.79 51.773 ;
     RECT  33.588 51.701 33.606 51.773 ;
     RECT  37.584 51.701 41.094 51.773 ;
     RECT  42.48 51.629 42.93 51.773 ;
     RECT  44.892 51.701 49.842 51.773 ;
     RECT  52.272 51.629 52.29 51.773 ;
     RECT  2.052 51.629 4.842 51.809 ;
     RECT  12.636 51.629 16.614 51.809 ;
     RECT  20.916 51.629 20.934 51.809 ;
     RECT  23.94 51.649 24.105 51.809 ;
     RECT  25.704 51.737 32.418 51.809 ;
     RECT  37.98 51.773 41.094 51.809 ;
     RECT  42.912 51.773 42.93 51.809 ;
     RECT  45.432 51.773 49.842 51.809 ;
     RECT  64.656 51.314 64.71 51.821 ;
     RECT  7.815 51.665 7.905 51.857 ;
     RECT  18.615 51.677 18.705 51.857 ;
     RECT  24.015 51.809 24.105 51.857 ;
     RECT  34.815 51.629 34.905 51.857 ;
     RECT  45.615 51.809 49.842 51.857 ;
     RECT  51.015 51.737 51.105 51.857 ;
     RECT  26.316 51.809 32.418 51.917 ;
     RECT  64.692 51.821 64.71 51.917 ;
     RECT  26.316 51.917 32.31 51.965 ;
     RECT  12.636 51.809 16.506 52.013 ;
     RECT  54.972 51.737 63.882 52.013 ;
     RECT  63.864 52.013 63.882 52.109 ;
     RECT  45.756 51.857 49.842 52.445 ;
     RECT  14.04 52.013 16.506 52.493 ;
     RECT  26.316 51.965 32.202 52.493 ;
     RECT  45.756 52.445 47.394 52.493 ;
     RECT  48.276 52.445 49.842 52.493 ;
     RECT  54.972 52.013 63.018 52.934 ;
     RECT  26.316 52.493 31.41 53.015 ;
     RECT  14.04 52.493 15.102 53.021 ;
     RECT  26.316 53.015 31.266 53.021 ;
     RECT  46.368 52.493 47.394 53.021 ;
     RECT  12.636 52.013 12.654 53.051 ;
     RECT  38.34 51.809 41.094 53.051 ;
     RECT  62.64 52.934 63.018 53.051 ;
     RECT  62.64 53.051 62.658 53.087 ;
     RECT  2.052 51.809 4.626 53.123 ;
     RECT  14.22 53.021 15.102 53.741 ;
     RECT  47.016 53.021 47.394 53.789 ;
     RECT  14.22 53.741 15.066 53.837 ;
     RECT  26.316 53.021 31.158 53.837 ;
     RECT  47.052 53.789 47.394 53.837 ;
     RECT  49.284 52.493 49.842 53.837 ;
     RECT  26.316 53.837 30.906 53.869 ;
     RECT  14.436 53.837 14.85 53.885 ;
     RECT  15.84 52.493 16.506 53.885 ;
     RECT  26.244 53.869 30.906 53.885 ;
     RECT  46.116 53.611 46.134 53.885 ;
     RECT  47.052 53.837 47.07 53.885 ;
     RECT  48.276 52.493 48.294 53.885 ;
     RECT  49.824 53.837 49.842 53.885 ;
     RECT  54.972 52.934 61.902 53.969 ;
     RECT  2.052 53.123 4.302 53.981 ;
     RECT  9.54 51.773 11.79 53.981 ;
     RECT  26.244 53.885 30.798 53.981 ;
     RECT  38.34 53.051 40.59 53.981 ;
     RECT  55.044 53.969 61.902 53.981 ;
    LAYER M4 ;
     RECT  0.025 43.92 0.06 43.944 ;
     RECT  0.06 5.328 0.137 7.656 ;
     RECT  0.137 5.424 0.173 7.656 ;
     RECT  0.173 5.52 0.209 7.656 ;
     RECT  0.06 43.92 0.209 50.184 ;
     RECT  0.209 5.616 0.245 7.656 ;
     RECT  0.245 5.712 0.281 7.656 ;
     RECT  0.281 5.808 0.317 7.656 ;
     RECT  0.209 44.112 0.569 50.184 ;
     RECT  0.569 44.112 2.257 49.992 ;
     RECT  0.317 5.904 2.408 7.656 ;
     RECT  2.401 9.6 2.408 9.624 ;
     RECT  2.293 15.984 2.408 16.008 ;
     RECT  0.181 27.168 2.408 27.192 ;
     RECT  2.365 34.176 2.408 34.2 ;
     RECT  2.257 44.112 2.408 50.856 ;
     RECT  2.408 2.148 2.473 51.852 ;
     RECT  2.473 2.148 2.512 52.584 ;
     RECT  2.512 2.256 2.704 52.584 ;
     RECT  2.704 24.576 2.801 27.336 ;
     RECT  2.801 24.576 2.819 26.28 ;
     RECT  2.704 2.256 2.867 4.008 ;
     RECT  2.689 53.904 2.867 53.928 ;
     RECT  2.704 39.072 3.017 51.336 ;
     RECT  2.704 6.384 3.089 11.16 ;
     RECT  2.704 21.648 3.197 23.4 ;
     RECT  2.867 2.784 3.233 4.008 ;
     RECT  3.017 50.592 3.269 51.336 ;
     RECT  2.704 52.464 3.269 52.584 ;
     RECT  3.233 2.784 3.629 3.192 ;
     RECT  2.704 20.112 3.665 20.136 ;
     RECT  3.269 52.464 3.665 52.488 ;
     RECT  2.704 5.184 3.697 5.208 ;
     RECT  2.704 28.464 3.731 34.2 ;
     RECT  2.704 15.216 3.737 16.824 ;
     RECT  3.697 4.464 3.769 5.208 ;
     RECT  3.089 6.384 3.769 7.272 ;
     RECT  3.017 39.072 3.773 49.608 ;
     RECT  2.801 27.312 3.841 27.336 ;
     RECT  3.731 32.304 3.841 34.2 ;
     RECT  3.841 32.304 3.845 34.584 ;
     RECT  2.704 37.056 3.877 37.08 ;
     RECT  3.845 32.448 3.913 34.584 ;
     RECT  3.197 21.648 3.917 23.352 ;
     RECT  3.737 16.8 3.949 16.824 ;
     RECT  3.877 37.008 3.949 37.08 ;
     RECT  3.737 15.216 3.953 15.672 ;
     RECT  3.913 32.448 3.953 35.352 ;
     RECT  2.819 24.576 3.985 25.656 ;
     RECT  3.841 26.736 3.985 27.336 ;
     RECT  3.773 39.072 3.985 49.512 ;
     RECT  2.704 12.48 4.025 13.992 ;
     RECT  3.731 28.464 4.028 28.488 ;
     RECT  3.269 50.88 4.057 51.336 ;
     RECT  3.953 32.448 4.061 33.528 ;
     RECT  3.629 3.168 4.169 3.192 ;
     RECT  3.985 24.576 4.169 27.336 ;
     RECT  3.953 34.56 4.169 35.352 ;
     RECT  3.985 38.64 4.205 49.512 ;
     RECT  3.953 15.648 4.211 15.672 ;
     RECT  4.169 24.576 4.241 25.08 ;
     RECT  3.949 36.624 4.268 37.08 ;
     RECT  3.769 4.464 4.273 7.272 ;
     RECT  3.089 8.256 4.273 11.16 ;
     RECT  4.268 36.48 4.309 37.08 ;
     RECT  4.057 50.88 4.345 51.72 ;
     RECT  4.345 50.736 4.457 51.72 ;
     RECT  4.165 18.768 4.525 18.792 ;
     RECT  4.457 50.736 4.529 50.904 ;
     RECT  4.273 4.464 4.556 11.16 ;
     RECT  4.025 12.48 4.556 12.504 ;
     RECT  4.529 50.736 4.565 50.76 ;
     RECT  4.205 38.736 4.637 49.512 ;
     RECT  3.917 21.648 4.691 22.824 ;
     RECT  3.949 16.8 4.705 17.112 ;
     RECT  4.556 4.464 4.745 12.504 ;
     RECT  3.985 19.776 4.745 19.8 ;
     RECT  4.745 4.464 4.781 12.12 ;
     RECT  4.525 18.24 4.781 18.792 ;
     RECT  4.169 26.256 4.813 27.336 ;
     RECT  4.028 28.416 4.813 28.488 ;
     RECT  4.705 16.8 5.029 17.16 ;
     RECT  4.781 4.464 5.033 5.928 ;
     RECT  4.637 46.368 5.033 49.512 ;
     RECT  4.691 22.464 5.105 22.824 ;
     RECT  4.061 32.448 5.173 32.76 ;
     RECT  4.309 36.48 5.173 37.608 ;
     RECT  4.781 7.056 5.177 12.12 ;
     RECT  4.813 26.256 5.177 28.488 ;
     RECT  5.173 32.448 5.209 33.048 ;
     RECT  3.731 30.144 5.245 30.936 ;
     RECT  5.209 32.448 5.245 33.144 ;
     RECT  5.245 30.144 5.281 33.144 ;
     RECT  4.169 34.656 5.281 35.352 ;
     RECT  5.105 22.464 5.285 22.728 ;
     RECT  4.885 23.904 5.317 23.928 ;
     RECT  4.241 24.912 5.317 25.08 ;
     RECT  5.317 23.904 5.318 25.08 ;
     RECT  5.065 3.312 5.353 3.336 ;
     RECT  4.781 18.288 5.363 18.792 ;
     RECT  5.285 22.464 5.363 22.68 ;
     RECT  5.281 30.144 5.372 33.336 ;
     RECT  5.253 21.408 5.389 21.432 ;
     RECT  4.637 38.736 5.411 45.096 ;
     RECT  5.177 27.312 5.413 28.488 ;
     RECT  5.372 30.144 5.413 33.624 ;
     RECT  5.281 34.608 5.413 35.352 ;
     RECT  5.413 27.312 5.459 28.776 ;
     RECT  5.353 3.312 5.461 3.432 ;
     RECT  5.033 4.464 5.461 5.64 ;
     RECT  5.413 30.144 5.461 35.352 ;
     RECT  5.318 23.952 5.465 25.08 ;
     RECT  5.465 23.952 5.609 25.032 ;
     RECT  5.461 29.808 5.641 35.352 ;
     RECT  5.173 36.336 5.641 37.608 ;
     RECT  5.177 7.248 5.713 12.12 ;
     RECT  5.033 46.368 5.713 49.032 ;
     RECT  4.025 13.968 5.753 13.992 ;
     RECT  5.461 3.312 5.789 5.64 ;
     RECT  5.029 16.08 5.821 17.16 ;
     RECT  5.609 25.008 5.825 25.032 ;
     RECT  5.713 7.248 5.893 12.744 ;
     RECT  5.389 20.592 5.929 21.432 ;
     RECT  5.459 28.368 5.929 28.776 ;
     RECT  5.641 29.808 5.929 37.608 ;
     RECT  5.821 16.08 6.005 17.208 ;
     RECT  5.713 46.32 6.029 49.032 ;
     RECT  5.101 50.016 6.029 50.04 ;
     RECT  5.893 7.248 6.035 13.8 ;
     RECT  6.035 11.136 6.113 13.8 ;
     RECT  5.789 3.312 6.188 5.208 ;
     RECT  6.188 3.216 6.275 5.208 ;
     RECT  5.677 15.024 6.277 15.048 ;
     RECT  6.005 16.08 6.277 17.064 ;
     RECT  5.411 39.552 6.437 45.096 ;
     RECT  6.437 44.448 6.445 45.096 ;
     RECT  6.277 15.024 6.473 17.064 ;
     RECT  6.445 44.496 6.497 45.096 ;
     RECT  6.029 46.32 6.497 50.04 ;
     RECT  5.177 26.256 6.577 26.28 ;
     RECT  6.497 44.496 6.581 50.04 ;
     RECT  5.929 28.368 6.649 37.608 ;
     RECT  6.437 39.552 6.649 43.464 ;
     RECT  6.581 46.32 6.685 50.04 ;
     RECT  6.613 2.256 6.697 2.28 ;
     RECT  6.113 11.232 6.725 13.8 ;
     RECT  5.459 27.312 6.793 27.336 ;
     RECT  6.649 28.368 6.793 43.464 ;
     RECT  6.577 25.776 6.829 26.28 ;
     RECT  6.793 27.312 6.829 43.464 ;
     RECT  5.929 20.592 6.837 21.768 ;
     RECT  5.363 18.288 6.853 18.696 ;
     RECT  6.837 20.592 6.853 21.96 ;
     RECT  5.641 0.048 6.865 0.072 ;
     RECT  5.609 23.952 6.865 23.976 ;
     RECT  6.685 46.32 6.865 50.52 ;
     RECT  6.035 7.248 6.901 10.152 ;
     RECT  6.865 23.856 7.009 23.976 ;
     RECT  6.865 0.048 7.043 0.12 ;
     RECT  6.829 25.776 7.081 43.464 ;
     RECT  6.901 6.864 7.153 10.152 ;
     RECT  6.725 11.232 7.153 13.08 ;
     RECT  6.853 20.448 7.153 21.96 ;
     RECT  7.009 23.28 7.153 23.976 ;
     RECT  7.081 25.056 7.261 43.464 ;
     RECT  6.275 3.456 7.285 5.208 ;
     RECT  7.285 2.832 7.333 5.208 ;
     RECT  7.153 20.16 7.369 23.976 ;
     RECT  7.261 25.008 7.369 43.464 ;
     RECT  7.333 2.832 7.477 5.352 ;
     RECT  7.043 0.096 7.523 0.12 ;
     RECT  7.477 2.832 7.549 5.736 ;
     RECT  7.549 2.832 7.585 5.784 ;
     RECT  7.153 6.864 7.585 13.08 ;
     RECT  7.585 2.832 7.808 13.08 ;
     RECT  6.473 15.024 7.808 15.048 ;
     RECT  6.473 16.032 7.808 17.064 ;
     RECT  6.853 18.288 7.808 18.84 ;
     RECT  7.369 20.16 7.808 43.464 ;
     RECT  6.581 44.496 7.808 45.288 ;
     RECT  6.865 46.32 7.808 50.568 ;
     RECT  7.808 2.148 7.912 51.852 ;
     RECT  7.912 2.256 8.104 51.582 ;
     RECT  8.104 18.432 8.273 18.456 ;
     RECT  8.104 50.4 8.273 50.568 ;
     RECT  8.104 20.4 8.381 28.488 ;
     RECT  7.573 0.528 8.417 0.552 ;
     RECT  8.104 5.088 8.417 9.912 ;
     RECT  8.381 20.4 8.417 28.392 ;
     RECT  8.417 5.616 8.561 9.912 ;
     RECT  8.417 20.4 8.561 21.72 ;
     RECT  8.104 2.256 8.641 2.28 ;
     RECT  8.273 50.544 8.813 50.568 ;
     RECT  8.561 20.592 8.849 21.72 ;
     RECT  8.104 29.712 8.957 41.064 ;
     RECT  8.849 20.592 9.059 21.048 ;
     RECT  8.417 22.848 9.101 28.392 ;
     RECT  8.104 42.288 9.107 45 ;
     RECT  9.107 42.288 9.109 43.32 ;
     RECT  9.109 42.048 9.196 43.32 ;
     RECT  8.104 11.568 9.205 13.704 ;
     RECT  8.561 5.616 9.209 9.816 ;
     RECT  8.104 14.688 9.209 17.208 ;
     RECT  9.209 16.56 9.241 17.208 ;
     RECT  9.209 14.688 9.281 15.432 ;
     RECT  8.104 46.512 9.349 48.792 ;
     RECT  9.101 22.848 9.353 25.32 ;
     RECT  8.957 29.712 9.353 40.344 ;
     RECT  8.521 0.048 9.395 0.072 ;
     RECT  9.101 26.352 9.421 28.392 ;
     RECT  9.353 30.288 9.425 40.344 ;
     RECT  9.353 24.096 9.461 25.32 ;
     RECT  9.107 44.352 9.493 45 ;
     RECT  9.425 30.288 9.497 38.52 ;
     RECT  9.557 19.344 9.589 19.368 ;
     RECT  9.059 20.592 9.589 20.952 ;
     RECT  9.349 46.512 9.605 49.032 ;
     RECT  9.589 19.344 9.641 20.952 ;
     RECT  9.461 24.144 9.677 25.32 ;
     RECT  9.205 11.424 9.709 13.704 ;
     RECT  9.281 14.688 9.709 14.856 ;
     RECT  9.209 5.616 9.749 8.616 ;
     RECT  9.457 50.784 9.749 51 ;
     RECT  9.241 16.56 9.817 18.168 ;
     RECT  9.353 22.848 9.817 23.112 ;
     RECT  9.749 50.784 9.82 50.904 ;
     RECT  9.82 50.736 9.893 50.904 ;
     RECT  9.817 22.224 9.925 23.112 ;
     RECT  9.425 39.552 9.997 40.344 ;
     RECT  9.997 39.552 10.037 40.92 ;
     RECT  9.893 50.736 10.069 50.76 ;
     RECT  9.196 42.72 10.105 43.32 ;
     RECT  9.493 44.352 10.105 45.048 ;
     RECT  9.349 3.984 10.177 4.008 ;
     RECT  9.817 16.56 10.181 18.792 ;
     RECT  9.209 9.792 10.249 9.816 ;
     RECT  9.641 20.304 10.285 20.952 ;
     RECT  9.925 22.176 10.285 23.112 ;
     RECT  9.677 25.296 10.285 25.32 ;
     RECT  9.421 26.352 10.285 29.208 ;
     RECT  9.497 30.384 10.307 38.52 ;
     RECT  10.285 25.296 10.325 29.208 ;
     RECT  10.105 42.72 10.393 45.048 ;
     RECT  9.605 46.512 10.393 48.936 ;
     RECT  10.325 26.256 10.397 29.208 ;
     RECT  10.037 39.888 10.465 40.92 ;
     RECT  9.677 24.144 10.469 24.168 ;
     RECT  10.307 31.92 10.501 38.52 ;
     RECT  10.405 53.904 10.541 53.928 ;
     RECT  10.249 9.792 10.565 9.912 ;
     RECT  9.709 11.424 10.597 14.856 ;
     RECT  10.597 11.136 10.645 14.856 ;
     RECT  10.393 42.72 10.645 48.936 ;
     RECT  10.565 9.648 10.649 9.912 ;
     RECT  10.649 9.888 10.681 9.912 ;
     RECT  10.645 11.136 10.681 15.288 ;
     RECT  10.681 9.888 10.685 15.288 ;
     RECT  10.177 3.984 10.693 4.536 ;
     RECT  10.693 3.312 10.78 4.536 ;
     RECT  10.685 15.264 10.789 15.288 ;
     RECT  10.465 39.888 10.789 41.112 ;
     RECT  10.645 42.432 10.789 48.936 ;
     RECT  10.069 50.16 10.793 50.76 ;
     RECT  10.285 20.304 10.829 23.112 ;
     RECT  10.307 30.384 10.837 30.792 ;
     RECT  10.673 1.728 10.844 1.752 ;
     RECT  10.181 16.848 10.937 18.792 ;
     RECT  10.844 1.728 11.041 2.28 ;
     RECT  10.501 31.92 11.041 38.616 ;
     RECT  10.789 39.888 11.045 48.936 ;
     RECT  9.749 5.616 11.077 7.992 ;
     RECT  10.937 18.144 11.081 18.792 ;
     RECT  10.78 3.936 11.113 4.536 ;
     RECT  11.077 5.616 11.113 8.52 ;
     RECT  11.113 3.936 11.116 8.52 ;
     RECT  11.041 1.728 11.125 2.616 ;
     RECT  10.781 0.096 11.153 0.12 ;
     RECT  11.045 39.888 11.171 41.256 ;
     RECT  10.789 15.264 11.257 15.816 ;
     RECT  10.937 16.848 11.257 16.92 ;
     RECT  11.045 42.432 11.276 48.936 ;
     RECT  10.837 29.904 11.401 30.792 ;
     RECT  11.041 31.92 11.401 38.712 ;
     RECT  10.829 20.688 11.473 23.112 ;
     RECT  11.081 18.432 11.513 18.792 ;
     RECT  11.116 4.56 11.549 8.52 ;
     RECT  11.401 29.904 11.549 38.712 ;
     RECT  10.685 9.888 11.555 14.232 ;
     RECT  11.257 25.248 11.581 25.272 ;
     RECT  10.397 26.256 11.581 28.44 ;
     RECT  11.581 25.248 11.689 28.44 ;
     RECT  11.549 6.72 11.699 8.52 ;
     RECT  11.555 11.424 11.729 12.216 ;
     RECT  11.689 25.104 11.761 28.44 ;
     RECT  11.617 0.48 11.833 0.504 ;
     RECT  11.833 0.48 11.834 0.552 ;
     RECT  10.793 50.496 11.869 50.76 ;
     RECT  11.555 13.92 11.905 14.232 ;
     RECT  11.257 15.264 11.905 16.92 ;
     RECT  11.473 20.688 11.945 23.16 ;
     RECT  11.549 4.56 11.989 5.64 ;
     RECT  11.761 25.104 12.017 29.16 ;
     RECT  11.699 6.864 12.049 8.52 ;
     RECT  11.555 9.888 12.049 10.344 ;
     RECT  11.869 50.4 12.049 50.76 ;
     RECT  11.945 21.648 12.053 23.16 ;
     RECT  11.834 0.528 12.083 0.552 ;
     RECT  12.017 25.104 12.085 29.064 ;
     RECT  11.549 30.288 12.085 38.712 ;
     RECT  12.085 30.288 12.157 38.76 ;
     RECT  11.171 40.56 12.157 41.256 ;
     RECT  12.157 30.288 12.161 38.952 ;
     RECT  12.161 30.336 12.197 38.952 ;
     RECT  12.197 38.448 12.229 38.952 ;
     RECT  11.125 1.728 12.373 2.28 ;
     RECT  12.229 38.448 12.373 39 ;
     RECT  12.157 40.368 12.373 41.256 ;
     RECT  11.513 18.432 12.409 18.504 ;
     RECT  11.905 13.92 12.428 16.92 ;
     RECT  12.409 18.384 12.428 18.504 ;
     RECT  12.085 24.192 12.445 29.064 ;
     RECT  12.373 38.448 12.481 41.256 ;
     RECT  11.276 42.432 12.481 49.032 ;
     RECT  12.428 13.92 12.625 18.504 ;
     RECT  12.589 19.584 12.625 19.608 ;
     RECT  12.445 24.144 12.697 29.064 ;
     RECT  12.049 6.864 12.733 10.344 ;
     RECT  12.373 1.056 12.755 2.28 ;
     RECT  12.755 1.728 12.764 2.28 ;
     RECT  11.989 4.944 12.841 5.64 ;
     RECT  12.733 6.864 12.841 10.776 ;
     RECT  11.729 12.192 12.841 12.216 ;
     RECT  12.625 13.92 12.949 19.608 ;
     RECT  12.841 4.944 12.985 10.776 ;
     RECT  12.841 12.192 12.985 12.312 ;
     RECT  12.764 1.728 13.061 2.376 ;
     RECT  12.985 4.944 13.093 12.312 ;
     RECT  12.697 24.096 13.093 29.064 ;
     RECT  13.061 1.776 13.177 2.376 ;
     RECT  13.093 4.944 13.201 12.504 ;
     RECT  13.177 2.148 13.208 2.376 ;
     RECT  13.201 4.224 13.208 12.504 ;
     RECT  12.949 13.92 13.208 20.424 ;
     RECT  12.053 21.792 13.208 22.776 ;
     RECT  13.093 23.952 13.208 29.064 ;
     RECT  12.197 30.336 13.208 37.464 ;
     RECT  12.481 38.448 13.208 49.032 ;
     RECT  12.049 50.4 13.208 51.336 ;
     RECT  13.208 2.148 13.312 51.852 ;
     RECT  13.312 2.418 13.345 51.852 ;
     RECT  13.345 2.418 13.504 52.008 ;
     RECT  13.504 24.096 13.529 24.216 ;
     RECT  13.504 25.248 13.565 41.496 ;
     RECT  13.529 24.096 13.601 24.12 ;
     RECT  13.565 25.248 13.745 36.936 ;
     RECT  13.504 13.92 13.781 22.776 ;
     RECT  13.745 25.584 13.859 36.936 ;
     RECT  13.565 38.16 13.925 41.496 ;
     RECT  13.504 51.264 13.933 52.008 ;
     RECT  13.859 30.144 14.105 36.936 ;
     RECT  14.029 52.992 14.209 53.016 ;
     RECT  14.209 52.992 14.245 53.832 ;
     RECT  13.781 13.92 14.285 18.792 ;
     RECT  14.105 30.288 14.285 36.936 ;
     RECT  13.504 3.312 14.291 12.552 ;
     RECT  14.285 30.432 14.321 36.936 ;
     RECT  13.933 51.312 14.353 52.008 ;
     RECT  14.245 52.992 14.353 53.88 ;
     RECT  14.321 30.48 14.429 36.936 ;
     RECT  13.781 19.776 14.524 22.776 ;
     RECT  14.524 21.792 14.537 22.776 ;
     RECT  13.504 42.576 14.645 48.936 ;
     RECT  13.925 38.16 14.681 41.208 ;
     RECT  14.353 51.312 14.681 53.88 ;
     RECT  14.681 38.304 14.717 41.208 ;
     RECT  13.859 25.584 14.749 29.064 ;
     RECT  14.717 38.304 14.753 41.016 ;
     RECT  14.681 52.464 14.771 53.88 ;
     RECT  14.749 25.488 14.785 29.064 ;
     RECT  14.429 30.864 14.785 36.936 ;
     RECT  14.537 21.984 14.789 22.776 ;
     RECT  14.785 25.392 14.789 29.064 ;
     RECT  14.677 24.048 14.857 24.072 ;
     RECT  14.645 42.72 14.857 48.936 ;
     RECT  14.857 24.048 14.861 24.312 ;
     RECT  14.785 30.864 14.861 37.32 ;
     RECT  14.789 25.392 14.897 28.728 ;
     RECT  14.285 14.064 14.963 18.792 ;
     RECT  14.857 42.72 14.993 49.32 ;
     RECT  14.291 10.32 15.004 12.552 ;
     RECT  15.004 10.32 15.013 11.448 ;
     RECT  14.861 24.288 15.077 24.312 ;
     RECT  14.993 42.72 15.077 49.416 ;
     RECT  14.963 14.112 15.113 18.792 ;
     RECT  14.861 31.152 15.113 37.32 ;
     RECT  15.077 42.72 15.113 49.32 ;
     RECT  14.771 53.712 15.113 53.88 ;
     RECT  14.897 25.392 15.116 28.536 ;
     RECT  15.113 14.112 15.185 16.056 ;
     RECT  14.753 38.304 15.185 39.912 ;
     RECT  15.116 24.768 15.203 28.536 ;
     RECT  15.004 12.48 15.289 12.552 ;
     RECT  14.681 51.312 15.301 51.432 ;
     RECT  15.185 14.112 15.437 16.008 ;
     RECT  15.301 50.688 15.509 51.432 ;
     RECT  15.113 35.136 15.545 37.32 ;
     RECT  15.509 51.264 15.617 51.432 ;
     RECT  15.185 38.304 15.683 39.48 ;
     RECT  15.113 17.04 15.685 18.792 ;
     RECT  14.524 19.776 15.685 20.76 ;
     RECT  15.545 35.136 15.725 37.08 ;
     RECT  15.617 51.312 15.757 51.432 ;
     RECT  14.771 52.464 15.757 52.488 ;
     RECT  15.289 12.48 15.761 13.032 ;
     RECT  15.683 38.304 15.781 38.76 ;
     RECT  14.291 3.312 15.793 9.096 ;
     RECT  15.793 3.072 15.865 9.096 ;
     RECT  15.793 30.144 15.865 30.168 ;
     RECT  15.781 38.112 15.869 38.76 ;
     RECT  15.203 25.104 15.887 28.536 ;
     RECT  15.865 30.048 15.887 30.168 ;
     RECT  15.685 17.04 15.901 20.76 ;
     RECT  14.789 21.984 15.901 22.728 ;
     RECT  14.753 40.992 15.901 41.016 ;
     RECT  15.901 17.04 15.937 22.728 ;
     RECT  15.013 10.32 15.941 11.256 ;
     RECT  15.865 2.976 15.973 9.096 ;
     RECT  15.973 2.784 16.045 9.096 ;
     RECT  16.045 2.784 16.06 9.336 ;
     RECT  15.901 40.992 16.121 41.736 ;
     RECT  15.113 42.768 16.153 49.32 ;
     RECT  16.06 2.976 16.301 9.336 ;
     RECT  15.113 31.152 16.301 33.864 ;
     RECT  16.301 31.152 16.307 33.768 ;
     RECT  15.887 25.104 16.337 30.168 ;
     RECT  15.757 51.312 16.445 52.488 ;
     RECT  15.761 12.48 16.477 12.552 ;
     RECT  16.307 31.152 16.477 33.672 ;
     RECT  15.113 53.856 16.517 53.88 ;
     RECT  16.477 30.72 16.589 33.672 ;
     RECT  16.445 51.312 16.589 51.528 ;
     RECT  16.301 7.968 16.633 9.336 ;
     RECT  16.337 25.104 16.657 29.4 ;
     RECT  16.657 24.768 16.661 29.4 ;
     RECT  16.153 42.192 16.661 49.32 ;
     RECT  16.633 8.736 16.693 9.336 ;
     RECT  15.941 10.32 16.693 10.344 ;
     RECT  15.725 35.136 16.733 36.6 ;
     RECT  16.733 35.136 16.805 35.352 ;
     RECT  16.661 45.84 16.805 49.32 ;
     RECT  15.937 17.04 16.837 23.256 ;
     RECT  16.733 36.432 16.837 36.6 ;
     RECT  16.477 11.952 16.844 12.552 ;
     RECT  16.837 16.56 16.883 23.256 ;
     RECT  16.844 11.952 16.909 12.936 ;
     RECT  16.693 8.736 16.945 10.344 ;
     RECT  16.909 11.952 16.945 13.032 ;
     RECT  16.121 40.992 16.945 41.16 ;
     RECT  16.883 16.56 16.949 20.184 ;
     RECT  16.883 21.216 16.985 23.256 ;
     RECT  15.869 38.448 17.017 38.76 ;
     RECT  16.945 8.736 17.021 13.032 ;
     RECT  16.837 36.432 17.036 37.08 ;
     RECT  17.021 13.008 17.053 13.032 ;
     RECT  15.437 14.112 17.053 15.48 ;
     RECT  16.949 16.56 17.053 18.216 ;
     RECT  17.017 38.16 17.053 38.76 ;
     RECT  17.036 36.432 17.077 37.176 ;
     RECT  17.053 38.16 17.077 38.808 ;
     RECT  16.985 21.648 17.089 23.256 ;
     RECT  16.661 24.768 17.089 27.24 ;
     RECT  16.945 40.176 17.089 41.16 ;
     RECT  16.949 19.344 17.093 20.184 ;
     RECT  16.805 46.272 17.093 49.32 ;
     RECT  17.089 21.648 17.123 27.24 ;
     RECT  17.077 36.432 17.125 38.808 ;
     RECT  17.089 40.176 17.125 41.208 ;
     RECT  17.021 8.736 17.129 11.976 ;
     RECT  17.053 13.008 17.129 18.216 ;
     RECT  17.093 19.344 17.129 19.944 ;
     RECT  17.123 24.96 17.129 27.24 ;
     RECT  17.093 46.368 17.129 49.32 ;
     RECT  17.129 13.008 17.201 14.28 ;
     RECT  17.129 46.512 17.233 49.32 ;
     RECT  16.661 28.272 17.267 29.4 ;
     RECT  16.301 2.976 17.269 6.744 ;
     RECT  17.233 46.512 17.269 49.608 ;
     RECT  16.873 50.736 17.269 50.76 ;
     RECT  17.201 13.008 17.273 14.232 ;
     RECT  17.267 28.272 17.308 28.488 ;
     RECT  17.125 36.432 17.453 41.208 ;
     RECT  16.805 35.328 17.525 35.352 ;
     RECT  17.269 46.512 17.557 50.76 ;
     RECT  17.273 13.008 17.597 13.896 ;
     RECT  16.589 30.72 17.629 31.32 ;
     RECT  16.589 32.4 17.629 33.672 ;
     RECT  17.269 2.976 17.701 7.656 ;
     RECT  17.701 2.832 17.809 7.656 ;
     RECT  17.129 8.736 17.809 11.16 ;
     RECT  17.773 29.52 17.881 29.544 ;
     RECT  17.629 30.72 17.881 33.672 ;
     RECT  16.661 42.192 18.053 44.712 ;
     RECT  17.129 15.696 18.097 18.216 ;
     RECT  17.129 19.776 18.097 19.944 ;
     RECT  17.597 13.008 18.169 13.368 ;
     RECT  17.453 41.184 18.169 41.208 ;
     RECT  18.053 42.192 18.169 45.048 ;
     RECT  18.097 15.696 18.205 19.944 ;
     RECT  17.809 2.832 18.277 11.16 ;
     RECT  17.129 24.96 18.313 27.144 ;
     RECT  17.308 28.272 18.313 28.296 ;
     RECT  18.277 2.832 18.332 11.496 ;
     RECT  18.169 12.48 18.332 13.368 ;
     RECT  18.205 15.264 18.349 19.944 ;
     RECT  17.881 29.52 18.349 33.672 ;
     RECT  17.123 21.648 18.385 23.88 ;
     RECT  17.557 46.512 18.385 50.856 ;
     RECT  17.453 36.432 18.529 40.2 ;
     RECT  18.169 41.184 18.529 45.048 ;
     RECT  18.332 2.832 18.608 13.368 ;
     RECT  18.349 14.688 18.608 19.944 ;
     RECT  18.385 20.976 18.608 23.88 ;
     RECT  18.313 24.96 18.608 28.296 ;
     RECT  18.349 29.52 18.608 34.104 ;
     RECT  18.529 36.432 18.608 45.048 ;
     RECT  18.385 46.512 18.608 51.672 ;
     RECT  18.608 2.148 18.712 51.852 ;
     RECT  18.712 2.418 18.904 51.672 ;
     RECT  18.904 39.744 19.109 48.792 ;
     RECT  19.109 44.688 19.145 48.792 ;
     RECT  18.904 2.88 19.181 19.032 ;
     RECT  19.109 39.84 19.181 43.656 ;
     RECT  19.181 6.096 19.253 19.032 ;
     RECT  19.181 39.84 19.361 43.608 ;
     RECT  19.253 6.24 19.469 19.032 ;
     RECT  19.469 6.24 19.505 10.632 ;
     RECT  19.469 12.336 19.541 19.032 ;
     RECT  19.145 44.688 19.613 48.456 ;
     RECT  19.361 39.888 19.852 43.608 ;
     RECT  19.613 44.736 19.865 48.456 ;
     RECT  18.904 20.688 19.897 23.88 ;
     RECT  18.904 32.352 19.897 33.672 ;
     RECT  18.904 35.376 19.897 38.712 ;
     RECT  19.852 39.936 19.901 43.608 ;
     RECT  18.904 28.272 19.909 31.176 ;
     RECT  19.897 32.352 19.909 38.712 ;
     RECT  19.541 12.336 19.937 15.72 ;
     RECT  19.901 39.936 19.937 43.416 ;
     RECT  19.865 44.736 19.937 48.216 ;
     RECT  18.904 25.488 19.957 27.24 ;
     RECT  19.909 28.272 19.957 38.712 ;
     RECT  19.957 25.488 19.964 38.712 ;
     RECT  19.937 44.976 19.973 48.216 ;
     RECT  19.897 20.4 20.005 23.88 ;
     RECT  18.904 51.648 20.045 51.672 ;
     RECT  19.541 16.896 20.051 19.032 ;
     RECT  19.937 40.56 20.081 43.176 ;
     RECT  20.051 17.328 20.149 19.032 ;
     RECT  20.005 20.4 20.149 23.928 ;
     RECT  20.149 17.328 20.197 23.928 ;
     RECT  19.964 25.152 20.197 38.712 ;
     RECT  19.181 2.88 20.221 4.44 ;
     RECT  20.197 17.328 20.236 38.712 ;
     RECT  19.505 6.24 20.261 10.392 ;
     RECT  20.236 20.4 20.531 38.712 ;
     RECT  20.221 2.64 20.545 4.44 ;
     RECT  19.973 44.976 20.549 45 ;
     RECT  20.531 25.536 20.585 38.712 ;
     RECT  20.081 40.608 20.621 43.176 ;
     RECT  19.937 13.152 20.657 15.72 ;
     RECT  20.585 25.536 20.657 38.184 ;
     RECT  20.531 20.4 20.693 23.928 ;
     RECT  20.693 20.4 20.765 20.424 ;
     RECT  20.657 29.52 20.873 38.184 ;
     RECT  20.657 13.536 20.945 15.72 ;
     RECT  20.945 13.536 20.963 15.48 ;
     RECT  20.545 2.64 20.977 4.488 ;
     RECT  20.873 29.52 20.981 38.088 ;
     RECT  19.973 46.128 21.013 48.216 ;
     RECT  20.657 25.536 21.017 28.488 ;
     RECT  20.261 7.968 21.053 10.392 ;
     RECT  20.236 17.328 21.085 19.32 ;
     RECT  21.013 45.984 21.085 48.216 ;
     RECT  20.981 31.776 21.089 38.088 ;
     RECT  20.261 6.24 21.109 6.84 ;
     RECT  21.053 9.12 21.109 10.392 ;
     RECT  20.797 11.472 21.109 11.496 ;
     RECT  21.017 28.368 21.125 28.488 ;
     RECT  21.089 35.376 21.125 38.088 ;
     RECT  20.963 13.536 21.197 15.288 ;
     RECT  21.125 36.384 21.197 38.088 ;
     RECT  20.693 21.456 21.233 22.344 ;
     RECT  20.981 29.52 21.233 30.168 ;
     RECT  20.977 2.64 21.269 4.536 ;
     RECT  21.053 7.968 21.277 7.992 ;
     RECT  21.197 13.536 21.347 15.096 ;
     RECT  21.109 6 21.373 6.84 ;
     RECT  21.125 28.416 21.377 28.488 ;
     RECT  21.125 35.376 21.377 35.4 ;
     RECT  21.269 3.072 21.485 4.536 ;
     RECT  21.109 9.12 21.491 11.496 ;
     RECT  21.347 13.536 21.491 14.712 ;
     RECT  21.085 16.512 21.491 19.32 ;
     RECT  21.452 44.256 21.539 44.28 ;
     RECT  21.017 25.536 21.553 27.336 ;
     RECT  21.089 31.776 21.557 34.104 ;
     RECT  21.085 45.6 21.557 48.84 ;
     RECT  20.509 50.064 21.637 50.088 ;
     RECT  21.557 45.6 21.661 47.736 ;
     RECT  21.553 25.44 21.697 27.336 ;
     RECT  21.637 50.064 21.737 50.424 ;
     RECT  21.737 50.064 21.745 50.184 ;
     RECT  20.621 40.608 21.773 42.792 ;
     RECT  21.491 9.12 21.809 9.864 ;
     RECT  21.773 40.608 21.877 41.208 ;
     RECT  21.877 40.56 21.881 41.208 ;
     RECT  21.485 3.072 21.917 4.488 ;
     RECT  21.197 36.48 21.949 38.088 ;
     RECT  21.557 31.776 21.985 33.096 ;
     RECT  21.773 42.24 22.165 42.792 ;
     RECT  21.589 43.824 22.165 43.848 ;
     RECT  21.491 13.536 22.201 13.56 ;
     RECT  21.697 25.008 22.201 27.336 ;
     RECT  21.377 28.416 22.201 28.44 ;
     RECT  21.233 29.52 22.201 30.12 ;
     RECT  21.985 31.536 22.201 33.096 ;
     RECT  22.165 42.24 22.205 43.848 ;
     RECT  21.809 9.12 22.273 9.672 ;
     RECT  21.491 17.904 22.273 19.32 ;
     RECT  20.693 23.328 22.277 23.928 ;
     RECT  22.201 25.008 22.277 28.44 ;
     RECT  21.917 3.072 22.313 4.44 ;
     RECT  21.373 6 22.313 7.176 ;
     RECT  22.313 7.104 22.349 7.176 ;
     RECT  22.277 23.328 22.349 23.88 ;
     RECT  22.201 29.52 22.349 33.096 ;
     RECT  21.949 36.48 22.421 38.76 ;
     RECT  21.491 11.472 22.561 11.496 ;
     RECT  21.557 34.08 22.565 34.104 ;
     RECT  22.421 36.48 22.705 37.608 ;
     RECT  22.201 49.872 22.745 49.896 ;
     RECT  22.201 13.152 22.777 13.56 ;
     RECT  22.273 8.688 22.813 9.672 ;
     RECT  21.661 44.928 22.813 47.736 ;
     RECT  21.557 48.816 22.813 48.84 ;
     RECT  21.881 40.56 22.844 41.16 ;
     RECT  22.205 42.24 22.844 43.608 ;
     RECT  21.233 21.648 22.849 22.344 ;
     RECT  22.561 11.376 22.885 11.496 ;
     RECT  21.491 16.512 22.885 16.536 ;
     RECT  22.705 35.856 22.885 37.608 ;
     RECT  22.349 31.536 22.889 33.096 ;
     RECT  22.885 15.984 22.925 16.536 ;
     RECT  22.813 8.688 22.957 10.296 ;
     RECT  22.885 11.376 22.957 11.736 ;
     RECT  22.957 8.688 22.961 11.736 ;
     RECT  22.349 29.52 22.997 30.12 ;
     RECT  22.885 35.472 23.065 37.608 ;
     RECT  22.813 44.928 23.101 48.84 ;
     RECT  22.844 40.56 23.132 43.608 ;
     RECT  22.313 3.12 23.245 4.44 ;
     RECT  22.313 6 23.245 6.024 ;
     RECT  22.349 23.616 23.317 23.88 ;
     RECT  22.277 25.104 23.317 28.44 ;
     RECT  20.401 51.6 23.317 51.624 ;
     RECT  22.273 17.904 23.389 19.944 ;
     RECT  22.849 21.36 23.389 22.344 ;
     RECT  23.101 44.88 23.389 48.84 ;
     RECT  23.132 39.84 23.461 43.608 ;
     RECT  23.389 44.784 23.461 48.84 ;
     RECT  22.925 15.984 23.533 16.008 ;
     RECT  23.389 17.904 23.569 22.344 ;
     RECT  23.317 23.616 23.569 28.44 ;
     RECT  22.961 10.8 23.612 11.736 ;
     RECT  22.777 13.056 23.612 13.56 ;
     RECT  23.461 39.84 23.653 48.84 ;
     RECT  23.245 3.12 23.713 6.024 ;
     RECT  22.349 7.104 23.713 7.128 ;
     RECT  22.961 8.688 23.713 9.72 ;
     RECT  22.889 32.496 23.893 33.096 ;
     RECT  23.065 34.464 23.893 37.608 ;
     RECT  23.569 17.904 23.929 28.44 ;
     RECT  23.713 3.12 24.008 7.128 ;
     RECT  23.713 8.496 24.008 9.72 ;
     RECT  23.612 10.8 24.008 13.56 ;
     RECT  21.491 14.688 24.008 14.712 ;
     RECT  23.533 15.936 24.008 16.008 ;
     RECT  23.929 17.376 24.008 28.44 ;
     RECT  22.997 29.568 24.008 30.12 ;
     RECT  23.893 32.496 24.008 37.608 ;
     RECT  22.421 38.736 24.008 38.76 ;
     RECT  23.653 39.84 24.008 49.608 ;
     RECT  23.317 51.168 24.008 51.624 ;
     RECT  24.008 2.148 24.112 51.852 ;
     RECT  24.112 2.418 24.304 51.582 ;
     RECT  24.304 14.016 24.473 38.232 ;
     RECT  24.304 51.168 24.473 51.192 ;
     RECT  24.304 2.784 24.515 12.936 ;
     RECT  24.515 3.12 24.581 12.936 ;
     RECT  24.581 5.04 24.617 12.936 ;
     RECT  24.473 20.4 24.725 38.232 ;
     RECT  24.473 14.016 24.803 19.368 ;
     RECT  24.304 39.216 24.833 49.608 ;
     RECT  24.617 5.04 25.229 8.28 ;
     RECT  24.725 23.328 25.373 29.832 ;
     RECT  24.803 14.016 25.409 15.384 ;
     RECT  24.725 20.4 25.445 22.008 ;
     RECT  24.725 31.44 25.517 38.232 ;
     RECT  24.833 39.216 25.517 49.56 ;
     RECT  24.581 3.12 25.661 3.768 ;
     RECT  25.661 3.408 25.693 3.768 ;
     RECT  25.445 20.736 25.697 22.008 ;
     RECT  25.697 20.976 25.769 22.008 ;
     RECT  24.617 9.312 25.772 12.936 ;
     RECT  25.229 7.056 25.837 8.28 ;
     RECT  25.772 9.312 25.837 13.128 ;
     RECT  25.517 39.792 25.873 49.56 ;
     RECT  25.517 31.44 25.981 37.464 ;
     RECT  25.837 7.056 25.985 13.128 ;
     RECT  25.981 31.344 26.005 37.464 ;
     RECT  25.373 23.328 26.017 29.208 ;
     RECT  26.017 23.184 26.057 29.208 ;
     RECT  25.769 21.072 26.089 22.008 ;
     RECT  26.057 23.184 26.089 25.08 ;
     RECT  25.409 14.112 26.129 15.384 ;
     RECT  25.873 39.792 26.129 49.656 ;
     RECT  26.129 14.208 26.165 15.384 ;
     RECT  26.057 26.208 26.165 29.208 ;
     RECT  26.165 14.64 26.197 15.384 ;
     RECT  24.803 16.368 26.197 19.368 ;
     RECT  26.089 21.072 26.237 25.08 ;
     RECT  25.229 5.952 26.305 6.072 ;
     RECT  25.985 7.056 26.305 7.464 ;
     RECT  26.129 42.192 26.381 49.656 ;
     RECT  26.381 42.192 26.489 49.608 ;
     RECT  26.405 53.04 26.489 53.064 ;
     RECT  26.237 21.072 26.525 24.792 ;
     RECT  26.005 30.384 26.557 37.464 ;
     RECT  25.693 3.408 26.561 4.632 ;
     RECT  26.588 50.832 26.629 50.856 ;
     RECT  26.489 44.352 26.633 49.608 ;
     RECT  26.557 30.192 26.701 37.464 ;
     RECT  26.341 38.736 26.701 38.76 ;
     RECT  26.197 14.64 26.741 19.368 ;
     RECT  26.633 44.352 26.741 48.984 ;
     RECT  26.629 50.832 26.773 51.192 ;
     RECT  26.561 3.456 26.809 4.632 ;
     RECT  26.305 5.952 26.809 7.464 ;
     RECT  26.741 44.448 26.813 48.984 ;
     RECT  26.809 3.456 26.849 7.464 ;
     RECT  25.985 8.544 26.885 13.128 ;
     RECT  26.741 15.888 27.061 19.368 ;
     RECT  27.061 15.888 27.065 20.04 ;
     RECT  27.065 18.096 27.101 20.04 ;
     RECT  26.701 30.192 27.101 38.76 ;
     RECT  27.065 15.888 27.173 17.064 ;
     RECT  26.741 14.64 27.241 14.664 ;
     RECT  26.885 8.544 27.277 10.44 ;
     RECT  27.241 14.208 27.281 14.664 ;
     RECT  27.281 14.208 27.325 14.232 ;
     RECT  27.101 18.144 27.349 20.04 ;
     RECT  26.525 21.072 27.349 24.648 ;
     RECT  27.101 31.92 27.349 38.76 ;
     RECT  26.129 39.792 27.349 41.112 ;
     RECT  27.349 18.144 27.353 24.648 ;
     RECT  26.165 26.448 27.385 29.208 ;
     RECT  27.101 30.192 27.385 30.552 ;
     RECT  26.849 5.184 27.421 7.464 ;
     RECT  27.277 8.448 27.421 10.44 ;
     RECT  27.385 26.016 27.497 30.552 ;
     RECT  26.849 3.456 27.529 3.912 ;
     RECT  27.353 18.672 27.529 24.648 ;
     RECT  26.773 50.736 27.539 51.192 ;
     RECT  26.813 47.712 27.601 48.984 ;
     RECT  27.539 50.736 27.605 51.096 ;
     RECT  26.885 11.952 27.673 13.128 ;
     RECT  27.349 31.92 27.677 41.112 ;
     RECT  27.601 47.712 27.685 49.608 ;
     RECT  27.529 18.672 27.709 24.696 ;
     RECT  26.489 42.192 27.709 43.128 ;
     RECT  27.709 42.192 27.781 43.416 ;
     RECT  26.813 44.448 27.781 46.68 ;
     RECT  27.497 26.016 27.785 30.408 ;
     RECT  27.529 3.072 27.821 3.912 ;
     RECT  26.492 53.904 27.827 53.928 ;
     RECT  27.421 5.184 27.889 10.44 ;
     RECT  27.889 5.184 27.893 10.92 ;
     RECT  27.709 18.672 27.923 24.936 ;
     RECT  27.673 11.952 27.929 14.04 ;
     RECT  27.821 3.072 27.965 3.864 ;
     RECT  27.923 19.008 27.965 24.936 ;
     RECT  27.781 42.192 27.989 46.68 ;
     RECT  27.685 47.712 27.989 49.032 ;
     RECT  27.785 26.112 28.037 30.408 ;
     RECT  27.173 15.888 28.069 16.008 ;
     RECT  27.605 50.736 28.069 50.952 ;
     RECT  27.677 31.92 28.165 33.096 ;
     RECT  27.893 5.184 28.204 7.992 ;
     RECT  27.965 3.312 28.217 3.864 ;
     RECT  28.204 5.184 28.249 6.84 ;
     RECT  27.677 34.368 28.325 41.112 ;
     RECT  28.037 30.384 28.609 30.408 ;
     RECT  28.165 31.872 28.609 33.096 ;
     RECT  28.069 15.744 28.645 16.008 ;
     RECT  27.173 17.04 28.645 17.064 ;
     RECT  27.989 42.192 28.681 49.032 ;
     RECT  28.069 50.064 28.681 50.952 ;
     RECT  27.929 13.584 28.717 14.04 ;
     RECT  28.609 30.384 28.717 33.096 ;
     RECT  28.217 3.36 28.789 3.864 ;
     RECT  28.249 5.088 28.789 6.84 ;
     RECT  28.717 13.584 28.825 14.136 ;
     RECT  28.325 38.064 28.825 41.112 ;
     RECT  28.681 42.192 28.825 50.952 ;
     RECT  28.645 15.744 28.861 17.064 ;
     RECT  27.893 9.024 28.897 10.92 ;
     RECT  27.965 19.008 28.933 24.696 ;
     RECT  28.825 13.584 28.981 14.184 ;
     RECT  28.861 15.552 28.981 17.064 ;
     RECT  28.825 38.064 29.029 51.336 ;
     RECT  28.897 8.976 29.041 10.92 ;
     RECT  28.981 13.584 29.077 17.064 ;
     RECT  28.037 26.112 29.077 28.968 ;
     RECT  29.041 8.976 29.113 10.968 ;
     RECT  27.929 11.952 29.113 11.976 ;
     RECT  28.933 18.816 29.125 24.696 ;
     RECT  29.077 13.584 29.141 17.736 ;
     RECT  29.141 13.536 29.149 17.736 ;
     RECT  29.125 18.816 29.149 24.744 ;
     RECT  29.077 26.112 29.149 29.112 ;
     RECT  28.204 7.968 29.221 7.992 ;
     RECT  28.717 30.384 29.221 33.288 ;
     RECT  29.113 8.976 29.257 11.976 ;
     RECT  29.149 13.344 29.257 17.736 ;
     RECT  28.789 3.36 29.329 6.84 ;
     RECT  29.221 7.92 29.329 7.992 ;
     RECT  29.149 18.816 29.329 29.112 ;
     RECT  29.221 30.384 29.329 33.336 ;
     RECT  29.329 18.768 29.365 29.112 ;
     RECT  29.329 30.144 29.365 33.384 ;
     RECT  29.329 3.36 29.408 7.992 ;
     RECT  29.257 8.976 29.408 17.736 ;
     RECT  29.365 18.768 29.408 33.384 ;
     RECT  28.325 34.368 29.408 37.08 ;
     RECT  29.029 38.064 29.408 51.96 ;
     RECT  29.408 2.148 29.501 51.96 ;
     RECT  29.501 2.148 29.512 52.44 ;
     RECT  29.512 2.418 29.585 52.44 ;
     RECT  28.885 53.712 29.701 53.736 ;
     RECT  29.585 2.418 29.704 51.96 ;
     RECT  29.704 3.36 29.729 24.408 ;
     RECT  29.701 53.664 29.761 53.736 ;
     RECT  29.729 3.36 29.765 24.264 ;
     RECT  29.704 34.416 29.765 51.96 ;
     RECT  29.761 53.04 29.797 53.736 ;
     RECT  29.797 53.04 29.893 53.784 ;
     RECT  29.765 3.36 29.945 14.232 ;
     RECT  29.765 34.416 29.981 51.864 ;
     RECT  29.704 26.88 29.987 31.512 ;
     RECT  29.765 15.264 30.053 24.264 ;
     RECT  29.981 34.416 30.053 51.816 ;
     RECT  30.053 16.8 30.089 24.264 ;
     RECT  29.987 26.88 30.233 30.168 ;
     RECT  30.089 16.8 30.275 19.896 ;
     RECT  30.053 34.416 30.385 51.528 ;
     RECT  30.233 26.88 30.413 29.64 ;
     RECT  30.385 47.712 30.485 51.528 ;
     RECT  30.275 17.472 30.557 19.896 ;
     RECT  29.945 3.36 30.665 14.184 ;
     RECT  29.704 32.496 30.697 33.384 ;
     RECT  30.385 34.416 30.697 46.44 ;
     RECT  30.665 3.36 30.769 5.88 ;
     RECT  30.665 7.44 30.845 14.184 ;
     RECT  29.987 31.296 30.845 31.512 ;
     RECT  29.704 25.872 30.851 25.896 ;
     RECT  29.893 53.04 30.853 53.88 ;
     RECT  30.697 32.496 30.899 46.44 ;
     RECT  30.557 17.664 30.917 19.896 ;
     RECT  30.853 52.992 30.917 53.88 ;
     RECT  30.845 11.136 30.953 14.184 ;
     RECT  30.917 17.712 30.953 19.896 ;
     RECT  30.899 32.496 31.093 46.296 ;
     RECT  30.485 51.312 31.121 51.528 ;
     RECT  30.917 52.992 31.169 53.832 ;
     RECT  30.089 21.072 31.189 24.264 ;
     RECT  30.053 15.264 31.277 15.384 ;
     RECT  31.169 52.992 31.321 53.016 ;
     RECT  30.485 47.712 31.331 50.28 ;
     RECT  31.121 51.312 31.333 51.864 ;
     RECT  30.413 26.88 31.381 29.592 ;
     RECT  30.769 3.072 31.421 5.88 ;
     RECT  31.381 26.208 31.477 29.592 ;
     RECT  31.331 47.712 31.529 49.608 ;
     RECT  30.953 19.344 31.628 19.896 ;
     RECT  31.189 21.072 31.628 24.792 ;
     RECT  30.845 7.776 31.637 10.104 ;
     RECT  30.953 12.384 31.637 14.184 ;
     RECT  31.093 32.064 31.667 46.296 ;
     RECT  31.529 47.712 31.669 49.08 ;
     RECT  31.333 51.312 31.669 52.488 ;
     RECT  31.667 40.608 31.673 46.296 ;
     RECT  31.669 6.288 31.705 6.312 ;
     RECT  31.477 26.208 31.705 29.64 ;
     RECT  31.421 3.072 31.715 5.064 ;
     RECT  31.637 10.08 31.715 10.104 ;
     RECT  31.628 19.344 31.715 24.792 ;
     RECT  31.669 47.664 31.741 49.08 ;
     RECT  31.705 6.288 31.957 6.408 ;
     RECT  31.667 32.064 31.961 39.336 ;
     RECT  31.957 6.288 31.993 6.696 ;
     RECT  31.637 7.776 31.993 9.096 ;
     RECT  30.953 17.712 32.065 18.312 ;
     RECT  31.993 6.288 32.069 9.096 ;
     RECT  31.597 0.096 32.101 0.12 ;
     RECT  32.069 6.288 32.105 9 ;
     RECT  31.715 21.312 32.149 24.792 ;
     RECT  31.705 26.208 32.149 29.688 ;
     RECT  30.953 11.136 32.177 11.16 ;
     RECT  31.715 19.344 32.177 20.04 ;
     RECT  31.993 1.728 32.209 1.752 ;
     RECT  31.669 50.736 32.213 52.488 ;
     RECT  32.149 21.312 32.236 29.688 ;
     RECT  32.137 16.608 32.245 16.632 ;
     RECT  31.637 12.528 32.284 14.184 ;
     RECT  32.213 50.736 32.321 51.96 ;
     RECT  31.673 40.656 32.353 46.296 ;
     RECT  31.277 15.264 32.389 15.288 ;
     RECT  32.245 16.56 32.389 16.632 ;
     RECT  32.321 50.736 32.429 51.912 ;
     RECT  32.429 50.736 32.435 51.72 ;
     RECT  32.435 50.736 32.485 51.336 ;
     RECT  31.669 30.864 32.497 30.888 ;
     RECT  32.485 50.688 32.501 51.336 ;
     RECT  32.209 1.728 32.533 1.8 ;
     RECT  31.715 3.072 32.533 4.824 ;
     RECT  32.065 17.664 32.605 18.312 ;
     RECT  32.177 19.344 32.605 19.896 ;
     RECT  32.533 1.728 32.723 4.824 ;
     RECT  32.236 26.256 32.821 29.688 ;
     RECT  32.497 30.864 32.821 31.56 ;
     RECT  32.353 40.656 32.893 46.344 ;
     RECT  31.741 47.472 32.893 49.08 ;
     RECT  32.389 15.264 32.929 16.632 ;
     RECT  32.893 40.656 33 49.464 ;
     RECT  32.501 50.688 33 50.712 ;
     RECT  32.929 15.264 33.001 16.68 ;
     RECT  32.605 17.664 33.001 19.896 ;
     RECT  32.821 26.256 33.001 31.56 ;
     RECT  31.961 32.544 33.001 39.336 ;
     RECT  33.001 15.264 33.005 19.896 ;
     RECT  32.284 12.864 33.037 14.184 ;
     RECT  33.005 15.264 33.037 19.512 ;
     RECT  32.236 21.312 33.113 25.224 ;
     RECT  33.001 26.256 33.113 39.336 ;
     RECT  32.101 0.096 33.116 0.168 ;
     RECT  33.113 26.592 33.149 39.336 ;
     RECT  33.149 28.464 33.185 39.336 ;
     RECT  33 40.656 33.185 50.712 ;
     RECT  33.116 0.096 33.212 0.552 ;
     RECT  32.723 1.728 33.212 1.752 ;
     RECT  33.061 9.6 33.217 9.624 ;
     RECT  33.037 12.864 33.221 19.512 ;
     RECT  33.212 0.096 33.299 1.752 ;
     RECT  32.723 3.072 33.325 4.824 ;
     RECT  32.105 6.288 33.361 8.424 ;
     RECT  33.217 9.552 33.361 9.624 ;
     RECT  33.221 12.864 33.361 14.808 ;
     RECT  33.185 40.656 33.361 44.472 ;
     RECT  33.361 12.768 33.473 14.808 ;
     RECT  33.325 3.072 33.505 5.208 ;
     RECT  33.361 6.288 33.505 9.624 ;
     RECT  33.185 45.648 33.505 50.712 ;
     RECT  33.185 28.464 33.581 34.152 ;
     RECT  33.113 21.312 33.653 25.128 ;
     RECT  33.299 0.096 33.683 0.552 ;
     RECT  33.505 3.072 33.685 9.624 ;
     RECT  33.073 10.656 33.685 10.68 ;
     RECT  33.685 3.072 33.757 10.68 ;
     RECT  33.149 26.592 33.779 27.48 ;
     RECT  33.185 35.136 33.793 39.336 ;
     RECT  33.361 40.416 33.793 44.472 ;
     RECT  33.505 45.648 33.797 51 ;
     RECT  33.797 45.648 33.827 46.776 ;
     RECT  33.797 47.76 33.833 51 ;
     RECT  33.833 47.76 33.841 50.952 ;
     RECT  33.757 3.024 33.901 11.544 ;
     RECT  33.473 12.768 33.901 14.616 ;
     RECT  33.221 16.08 34.189 19.512 ;
     RECT  33.581 29.04 34.189 34.152 ;
     RECT  33.793 35.136 34.189 44.472 ;
     RECT  34.189 16.08 34.213 19.896 ;
     RECT  34.213 16.08 34.441 19.992 ;
     RECT  33.901 3.024 34.477 14.616 ;
     RECT  34.477 3.024 34.549 14.712 ;
     RECT  33.299 1.728 34.808 1.752 ;
     RECT  34.549 3.024 34.808 15.048 ;
     RECT  34.441 16.032 34.808 19.992 ;
     RECT  33.653 21.312 34.808 25.08 ;
     RECT  33.779 26.64 34.808 27.48 ;
     RECT  34.189 29.04 34.808 44.472 ;
     RECT  33.827 45.648 34.808 46.296 ;
     RECT  33.841 47.76 34.808 49.512 ;
     RECT  33.841 50.688 34.808 50.952 ;
     RECT  34.808 1.728 34.849 51.852 ;
     RECT  33.683 0.096 34.885 0.216 ;
     RECT  34.849 2.148 34.912 51.852 ;
     RECT  34.885 0.096 34.985 0.552 ;
     RECT  34.985 0.096 35.065 0.264 ;
     RECT  34.912 2.418 35.104 51.582 ;
     RECT  35.065 0.144 35.165 0.264 ;
     RECT  35.165 0.24 35.245 0.264 ;
     RECT  35.104 10.752 35.273 30.264 ;
     RECT  35.273 17.904 35.309 30.264 ;
     RECT  35.104 31.392 35.356 44.52 ;
     RECT  35.309 17.904 35.411 20.04 ;
     RECT  35.356 31.392 35.411 33.96 ;
     RECT  35.411 17.904 35.417 18.792 ;
     RECT  35.411 19.824 35.453 20.04 ;
     RECT  35.417 18 35.525 18.792 ;
     RECT  35.453 19.872 35.597 19.896 ;
     RECT  35.309 21.984 35.597 30.264 ;
     RECT  35.273 10.752 35.633 16.68 ;
     RECT  35.597 21.984 35.669 22.824 ;
     RECT  35.525 18.768 35.741 18.792 ;
     RECT  35.411 31.488 35.741 33.96 ;
     RECT  35.633 10.752 35.921 15.24 ;
     RECT  35.741 31.488 35.921 33.48 ;
     RECT  35.356 34.992 35.921 44.52 ;
     RECT  35.921 31.92 35.957 33.48 ;
     RECT  35.921 34.992 35.957 43.8 ;
     RECT  35.104 45.648 36.097 46.2 ;
     RECT  35.104 47.328 36.097 47.352 ;
     RECT  35.597 23.952 36.209 30.264 ;
     RECT  36.097 45.648 36.245 47.352 ;
     RECT  35.104 5.664 36.268 9.048 ;
     RECT  35.104 48.48 36.389 50.184 ;
     RECT  36.268 5.664 36.425 6.84 ;
     RECT  36.209 23.952 36.425 24.696 ;
     RECT  35.921 10.752 36.461 14.712 ;
     RECT  36.268 8.016 36.469 9.048 ;
     RECT  35.957 35.184 36.533 43.8 ;
     RECT  36.389 49.152 36.533 50.184 ;
     RECT  36.449 51.264 36.533 51.288 ;
     RECT  36.461 12.432 36.556 14.712 ;
     RECT  36.425 23.952 36.569 24.504 ;
     RECT  36.209 26.016 36.572 30.264 ;
     RECT  35.669 22.176 36.637 22.824 ;
     RECT  36.572 26.016 36.659 30.504 ;
     RECT  36.469 8.016 36.709 9.768 ;
     RECT  36.461 10.752 36.709 11.4 ;
     RECT  36.637 21.648 36.709 22.824 ;
     RECT  36.659 26.016 36.713 29.544 ;
     RECT  36.709 8.016 36.785 11.4 ;
     RECT  36.601 19.776 36.803 20.328 ;
     RECT  36.709 21.648 36.803 23.352 ;
     RECT  35.633 16.368 36.821 16.68 ;
     RECT  35.957 32.016 36.853 33.48 ;
     RECT  36.785 8.016 36.893 8.04 ;
     RECT  36.853 32.016 36.961 34.056 ;
     RECT  36.821 16.512 36.984 16.68 ;
     RECT  35.104 3.984 37.033 4.68 ;
     RECT  36.425 5.664 37.033 6.696 ;
     RECT  36.245 45.648 37.033 46.872 ;
     RECT  36.533 41.568 37.037 43.8 ;
     RECT  36.556 12.864 37.105 14.712 ;
     RECT  36.569 24.384 37.109 24.504 ;
     RECT  37.037 42.768 37.141 43.8 ;
     RECT  36.961 32.016 37.177 34.104 ;
     RECT  36.533 35.184 37.177 40.056 ;
     RECT  36.803 19.776 37.249 19.992 ;
     RECT  36.984 16.512 37.285 17.112 ;
     RECT  37.177 18.192 37.285 18.216 ;
     RECT  37.033 3.984 37.321 6.696 ;
     RECT  37.249 19.248 37.361 19.992 ;
     RECT  37.361 19.536 37.433 19.992 ;
     RECT  36.533 49.152 37.433 49.176 ;
     RECT  37.033 45.6 37.465 46.872 ;
     RECT  37.177 32.016 37.469 40.056 ;
     RECT  37.469 32.016 37.501 39.912 ;
     RECT  37.105 12.864 37.573 14.76 ;
     RECT  36.533 50.16 37.573 50.184 ;
     RECT  36.803 22.128 37.789 23.352 ;
     RECT  37.573 12.864 37.825 15.528 ;
     RECT  37.285 16.512 37.825 18.216 ;
     RECT  36.713 26.784 37.825 29.544 ;
     RECT  37.825 12.864 37.865 18.216 ;
     RECT  37.141 42.768 37.897 43.896 ;
     RECT  37.573 49.728 37.897 50.184 ;
     RECT  37.897 42.768 37.969 44.136 ;
     RECT  37.501 31.056 38.009 39.912 ;
     RECT  38.009 36.528 38.045 39.912 ;
     RECT  37.037 41.76 38.077 41.784 ;
     RECT  37.969 42.768 38.077 44.184 ;
     RECT  38.045 39.888 38.099 39.912 ;
     RECT  38.009 31.056 38.101 35.496 ;
     RECT  36.785 9.072 38.113 11.4 ;
     RECT  37.109 24.48 38.113 24.504 ;
     RECT  38.005 25.488 38.113 25.512 ;
     RECT  38.113 24.48 38.149 25.512 ;
     RECT  38.149 24.48 38.185 25.656 ;
     RECT  37.825 26.736 38.185 29.544 ;
     RECT  38.101 30.768 38.189 35.496 ;
     RECT  37.789 21.168 38.197 23.352 ;
     RECT  38.185 24.48 38.3 29.544 ;
     RECT  38.3 24.48 38.387 29.976 ;
     RECT  37.433 19.776 38.401 19.992 ;
     RECT  38.197 21.024 38.401 23.352 ;
     RECT  38.387 24.48 38.549 29.544 ;
     RECT  38.077 40.992 38.549 44.184 ;
     RECT  37.465 45.6 38.581 48.456 ;
     RECT  37.897 49.728 38.581 50.76 ;
     RECT  38.189 31.056 38.621 34.872 ;
     RECT  37.321 3.408 38.732 6.696 ;
     RECT  38.732 3.408 38.773 6.84 ;
     RECT  38.401 19.776 38.797 23.352 ;
     RECT  38.549 24.48 38.797 29.112 ;
     RECT  38.581 45.6 38.828 50.76 ;
     RECT  38.797 19.776 38.837 29.112 ;
     RECT  38.113 8.736 38.869 11.4 ;
     RECT  37.865 12.864 38.869 17.064 ;
     RECT  38.828 45.6 38.869 50.856 ;
     RECT  38.549 41.76 38.873 44.184 ;
     RECT  38.869 45.312 38.873 51 ;
     RECT  38.773 3.408 38.941 7.416 ;
     RECT  38.869 8.736 38.941 17.064 ;
     RECT  38.873 41.76 38.945 41.784 ;
     RECT  38.941 3.408 38.956 17.064 ;
     RECT  37.865 18.192 39.085 18.216 ;
     RECT  38.821 53.04 39.089 53.064 ;
     RECT  38.956 3.408 39.125 11.496 ;
     RECT  38.837 21.84 39.125 29.112 ;
     RECT  38.621 31.056 39.125 34.824 ;
     RECT  38.873 42.816 39.157 44.184 ;
     RECT  38.873 45.312 39.157 47.88 ;
     RECT  38.045 36.528 39.253 38.76 ;
     RECT  38.725 40.416 39.253 40.44 ;
     RECT  39.253 36.528 39.301 40.44 ;
     RECT  39.301 36.096 39.445 40.44 ;
     RECT  38.873 48.912 39.553 51 ;
     RECT  39.125 33.024 39.695 34.824 ;
     RECT  39.445 36.048 39.695 40.44 ;
     RECT  39.125 31.056 39.733 32.04 ;
     RECT  38.837 19.776 39.805 20.664 ;
     RECT  39.125 23.328 39.877 29.112 ;
     RECT  39.805 19.584 39.913 20.664 ;
     RECT  39.125 21.84 39.913 22.248 ;
     RECT  39.877 23.328 39.973 29.64 ;
     RECT  39.733 30.864 39.973 32.04 ;
     RECT  39.085 18.048 40.057 18.216 ;
     RECT  39.125 3.408 40.093 11.448 ;
     RECT  39.74 53.904 40.115 53.928 ;
     RECT  40.093 3.36 40.208 11.448 ;
     RECT  38.956 12.528 40.208 17.064 ;
     RECT  40.057 18.048 40.208 18.552 ;
     RECT  39.913 19.584 40.208 22.248 ;
     RECT  39.973 23.328 40.208 32.04 ;
     RECT  39.695 33.024 40.208 40.44 ;
     RECT  39.157 42.816 40.208 47.88 ;
     RECT  39.553 48.912 40.208 51.336 ;
     RECT  40.208 2.148 40.312 51.852 ;
     RECT  40.312 2.418 40.504 51.672 ;
     RECT  40.504 47.712 40.529 51.672 ;
     RECT  40.504 9.84 40.565 16.92 ;
     RECT  40.504 26.928 40.565 39.912 ;
     RECT  40.565 9.84 40.709 16.872 ;
     RECT  40.565 28.752 40.709 39.912 ;
     RECT  40.504 19.584 40.889 25.752 ;
     RECT  40.889 19.584 40.925 22.824 ;
     RECT  40.889 23.856 40.997 25.752 ;
     RECT  40.709 28.752 41.033 29.16 ;
     RECT  40.709 16.704 41.105 16.872 ;
     RECT  40.529 47.712 41.219 51.48 ;
     RECT  40.997 23.952 41.249 25.752 ;
     RECT  40.504 3.36 41.357 3.384 ;
     RECT  40.504 4.512 41.497 8.808 ;
     RECT  41.497 3.984 41.507 8.808 ;
     RECT  40.504 18.528 41.525 18.552 ;
     RECT  41.507 3.984 41.573 5.88 ;
     RECT  40.565 26.928 41.653 27.72 ;
     RECT  40.709 30.24 41.681 39.912 ;
     RECT  41.681 30.24 41.717 39.336 ;
     RECT  41.653 26.208 41.74 27.72 ;
     RECT  41.525 18.528 41.821 19.416 ;
     RECT  40.504 41.136 41.825 46.632 ;
     RECT  40.709 9.84 41.857 15.432 ;
     RECT  41.105 16.704 41.857 16.728 ;
     RECT  41.857 9.84 41.933 16.728 ;
     RECT  41.507 7.104 42.073 8.808 ;
     RECT  41.933 9.84 42.073 13.08 ;
     RECT  41.933 14.208 42.073 16.728 ;
     RECT  41.821 18.288 42.073 19.416 ;
     RECT  41.825 41.616 42.092 46.632 ;
     RECT  41.219 47.712 42.092 50.184 ;
     RECT  41.74 26.736 42.109 27.72 ;
     RECT  41.033 28.8 42.109 29.16 ;
     RECT  42.092 41.616 42.179 50.184 ;
     RECT  42.073 14.208 42.185 19.416 ;
     RECT  42.179 41.616 42.185 46.68 ;
     RECT  42.073 7.104 42.221 13.08 ;
     RECT  40.925 20.544 42.38 22.824 ;
     RECT  41.249 23.952 42.38 25.176 ;
     RECT  41.573 3.984 42.397 5.736 ;
     RECT  42.185 19.056 42.397 19.416 ;
     RECT  42.38 20.544 42.397 25.176 ;
     RECT  42.397 19.056 42.401 25.176 ;
     RECT  42.185 14.208 42.419 17.688 ;
     RECT  42.221 7.104 42.541 11.544 ;
     RECT  42.179 47.904 42.541 50.184 ;
     RECT  42.109 26.736 42.613 29.16 ;
     RECT  41.717 30.24 42.613 34.152 ;
     RECT  42.541 47.904 42.613 50.328 ;
     RECT  41.219 51.456 42.613 51.48 ;
     RECT  42.541 6.912 42.653 11.544 ;
     RECT  42.397 3.312 42.797 5.736 ;
     RECT  41.717 35.184 42.797 39.336 ;
     RECT  42.797 3.744 42.805 5.736 ;
     RECT  42.653 6.912 42.805 8.808 ;
     RECT  42.185 41.616 42.815 43.08 ;
     RECT  42.221 12.528 42.899 13.08 ;
     RECT  42.805 3.744 42.905 8.808 ;
     RECT  42.419 14.208 42.977 17.4 ;
     RECT  42.613 47.904 42.977 51.48 ;
     RECT  42.401 22.992 43.009 25.176 ;
     RECT  42.613 26.736 43.009 34.152 ;
     RECT  42.977 15.12 43.049 17.4 ;
     RECT  43.009 22.992 43.081 34.152 ;
     RECT  42.815 40.8 43.189 43.08 ;
     RECT  42.905 6.672 43.265 8.808 ;
     RECT  43.081 22.992 43.297 34.2 ;
     RECT  42.797 35.328 43.297 39.336 ;
     RECT  43.189 40.8 43.297 43.224 ;
     RECT  42.977 47.904 43.331 48.456 ;
     RECT  42.653 9.84 43.405 11.544 ;
     RECT  42.977 49.488 43.445 51.48 ;
     RECT  43.297 35.328 43.525 43.224 ;
     RECT  42.185 44.448 43.525 46.68 ;
     RECT  42.905 3.744 43.619 5.592 ;
     RECT  43.525 35.328 43.625 46.68 ;
     RECT  43.049 16.512 43.657 17.4 ;
     RECT  43.265 6.672 43.733 8.664 ;
     RECT  43.445 49.488 43.733 50.328 ;
     RECT  43.625 45.936 43.801 46.68 ;
     RECT  43.549 13.2 43.873 13.752 ;
     RECT  43.445 51.456 43.913 51.48 ;
     RECT  43.297 22.992 43.945 34.248 ;
     RECT  43.625 35.328 43.945 44.52 ;
     RECT  43.405 9.84 43.955 12.072 ;
     RECT  42.401 19.056 43.981 21.864 ;
     RECT  43.945 22.992 43.981 44.52 ;
     RECT  43.657 16.512 44.108 17.88 ;
     RECT  43.981 19.056 44.108 44.52 ;
     RECT  44.108 16.512 44.195 44.52 ;
     RECT  43.619 5.376 44.269 5.592 ;
     RECT  43.733 6.672 44.269 7.656 ;
     RECT  44.195 27.264 44.291 44.52 ;
     RECT  43.049 15.12 44.377 15.48 ;
     RECT  43.331 48.432 44.413 48.456 ;
     RECT  43.733 49.488 44.413 49.896 ;
     RECT  44.269 5.376 44.453 7.656 ;
     RECT  44.291 36.288 44.453 44.52 ;
     RECT  44.453 6.672 44.531 7.656 ;
     RECT  43.733 8.64 44.531 8.664 ;
     RECT  44.195 16.512 44.561 26.184 ;
     RECT  44.377 15.024 44.593 15.48 ;
     RECT  44.453 36.336 44.629 44.52 ;
     RECT  43.801 45.936 44.665 47.16 ;
     RECT  44.413 48.432 44.737 49.896 ;
     RECT  44.629 36.336 44.809 44.952 ;
     RECT  44.665 45.936 44.809 47.208 ;
     RECT  43.873 13.104 44.845 13.752 ;
     RECT  44.593 14.736 44.845 15.48 ;
     RECT  43.955 9.84 44.917 10.776 ;
     RECT  44.737 48.432 44.917 49.992 ;
     RECT  43.619 3.984 44.989 4.008 ;
     RECT  44.917 9.84 45.025 10.968 ;
     RECT  43.955 11.952 45.025 12.072 ;
     RECT  45.025 9.84 45.061 12.072 ;
     RECT  44.845 13.104 45.061 15.48 ;
     RECT  45.061 9.024 45.169 15.48 ;
     RECT  44.561 20.976 45.385 26.184 ;
     RECT  44.291 27.264 45.385 35.304 ;
     RECT  45.169 9.024 45.493 15.528 ;
     RECT  44.561 16.512 45.493 19.8 ;
     RECT  44.989 3.408 45.565 4.008 ;
     RECT  45.061 5.04 45.565 5.064 ;
     RECT  44.531 6.672 45.601 7.368 ;
     RECT  45.565 3.408 45.608 5.064 ;
     RECT  45.601 6.288 45.608 7.368 ;
     RECT  45.493 9.024 45.608 19.8 ;
     RECT  45.385 20.976 45.608 35.304 ;
     RECT  44.809 36.336 45.608 47.208 ;
     RECT  44.917 48.432 45.608 50.136 ;
     RECT  45.608 2.148 45.637 51.852 ;
     RECT  45.637 2.148 45.712 52.488 ;
     RECT  45.712 2.418 45.904 52.488 ;
     RECT  45.733 53.616 45.925 53.64 ;
     RECT  45.925 53.52 46.021 53.64 ;
     RECT  46.021 53.52 46.105 53.736 ;
     RECT  45.904 3.696 46.109 8.52 ;
     RECT  45.904 13.056 46.109 18.84 ;
     RECT  46.109 13.056 46.145 17.784 ;
     RECT  45.904 31.2 46.153 52.488 ;
     RECT  46.153 31.2 46.156 35.352 ;
     RECT  46.109 3.696 46.181 6.312 ;
     RECT  46.153 36.336 46.181 52.488 ;
     RECT  46.181 49.296 46.213 52.488 ;
     RECT  46.105 53.52 46.213 53.88 ;
     RECT  46.145 13.056 46.253 17.4 ;
     RECT  46.213 49.296 46.253 53.88 ;
     RECT  46.181 5.904 46.289 6.312 ;
     RECT  46.181 36.336 46.289 48.12 ;
     RECT  46.253 51.216 46.355 53.88 ;
     RECT  46.253 14.688 46.397 17.4 ;
     RECT  45.904 27.696 46.397 30.168 ;
     RECT  46.355 51.312 46.397 53.88 ;
     RECT  46.253 49.296 46.505 50.184 ;
     RECT  46.181 3.696 46.541 4.824 ;
     RECT  46.289 36.48 46.541 48.12 ;
     RECT  46.505 49.296 46.577 49.608 ;
     RECT  46.541 36.48 46.613 38.808 ;
     RECT  46.109 7.632 46.685 8.52 ;
     RECT  46.685 7.872 46.739 8.52 ;
     RECT  46.397 51.312 46.739 52.488 ;
     RECT  45.904 9.648 46.757 10.968 ;
     RECT  46.541 3.696 46.793 4.776 ;
     RECT  46.739 7.872 46.793 7.896 ;
     RECT  45.904 19.92 46.793 26.664 ;
     RECT  46.156 31.2 46.829 35.304 ;
     RECT  46.541 39.84 46.829 48.12 ;
     RECT  46.793 21.936 46.901 26.664 ;
     RECT  46.901 26.256 46.931 26.664 ;
     RECT  46.931 26.256 47.045 26.28 ;
     RECT  46.829 32.976 47.045 35.304 ;
     RECT  46.397 53.76 47.045 53.88 ;
     RECT  46.757 9.888 47.117 10.968 ;
     RECT  46.613 36.48 47.117 38.424 ;
     RECT  46.793 19.92 47.123 20.568 ;
     RECT  46.109 18.816 47.149 18.84 ;
     RECT  46.397 27.696 47.149 29.112 ;
     RECT  47.123 19.92 47.164 20.376 ;
     RECT  46.793 3.696 47.189 4.68 ;
     RECT  46.397 30.144 47.257 30.168 ;
     RECT  46.829 31.2 47.257 31.704 ;
     RECT  46.289 5.904 47.297 6.072 ;
     RECT  46.829 39.84 47.333 47.304 ;
     RECT  47.045 34.704 47.401 35.304 ;
     RECT  47.117 36.48 47.401 36.504 ;
     RECT  46.901 21.936 47.405 25.272 ;
     RECT  47.117 37.632 47.5 38.424 ;
     RECT  47.149 27.36 47.545 29.112 ;
     RECT  47.257 30.144 47.545 31.704 ;
     RECT  47.405 23.376 47.585 25.272 ;
     RECT  47.333 39.84 47.585 47.16 ;
     RECT  47.149 49.2 47.585 49.224 ;
     RECT  47.189 3.696 47.617 4.392 ;
     RECT  46.253 13.056 47.617 13.32 ;
     RECT  46.397 14.688 47.617 17.064 ;
     RECT  47.585 40.128 47.621 47.16 ;
     RECT  47.117 9.888 47.869 10.728 ;
     RECT  47.621 40.128 47.873 40.632 ;
     RECT  47.545 27.36 47.893 31.704 ;
     RECT  47.045 32.976 47.893 33.336 ;
     RECT  47.869 9.696 47.905 10.728 ;
     RECT  47.149 18.816 47.941 18.888 ;
     RECT  47.893 27.36 47.945 33.336 ;
     RECT  46.739 51.312 48.005 51.912 ;
     RECT  47.945 33.312 48.013 33.336 ;
     RECT  47.905 8.976 48.049 10.728 ;
     RECT  48.005 51.312 48.049 52.44 ;
     RECT  47.977 26.208 48.061 26.232 ;
     RECT  47.941 18.528 48.085 18.888 ;
     RECT  48.013 33.312 48.121 33.672 ;
     RECT  47.401 34.704 48.121 36.504 ;
     RECT  47.164 20.304 48.125 20.376 ;
     RECT  48.049 8.544 48.14 10.728 ;
     RECT  48.14 8.544 48.181 10.872 ;
     RECT  47.617 2.88 48.193 4.392 ;
     RECT  47.617 13.056 48.193 17.064 ;
     RECT  48.125 20.304 48.197 20.328 ;
     RECT  48.181 8.544 48.227 11.4 ;
     RECT  48.085 18.432 48.229 18.888 ;
     RECT  47.945 27.36 48.233 32.232 ;
     RECT  47.5 37.632 48.233 38.136 ;
     RECT  47.297 5.904 48.265 5.928 ;
     RECT  48.193 7.344 48.265 7.368 ;
     RECT  48.227 8.544 48.265 10.248 ;
     RECT  48.265 5.904 48.341 10.248 ;
     RECT  47.405 21.936 48.409 22.344 ;
     RECT  47.585 23.376 48.409 25.032 ;
     RECT  47.941 48.432 48.449 48.984 ;
     RECT  48.049 50.544 48.449 52.44 ;
     RECT  48.193 2.88 48.469 4.536 ;
     RECT  48.341 5.904 48.469 9.816 ;
     RECT  48.193 12.432 48.481 17.064 ;
     RECT  48.229 18.144 48.481 18.888 ;
     RECT  48.481 12.432 48.485 18.888 ;
     RECT  48.233 27.36 48.485 30.696 ;
     RECT  48.227 11.376 48.517 11.4 ;
     RECT  48.485 12.432 48.517 18.84 ;
     RECT  48.449 51.552 48.517 52.44 ;
     RECT  47.621 41.664 48.521 47.16 ;
     RECT  48.517 11.376 48.557 18.84 ;
     RECT  48.449 48.432 48.557 48.552 ;
     RECT  48.469 2.88 48.593 9.816 ;
     RECT  48.557 11.376 48.737 12.552 ;
     RECT  48.517 51.552 48.737 52.488 ;
     RECT  48.733 50.4 48.769 50.424 ;
     RECT  48.409 21.936 48.949 25.032 ;
     RECT  48.485 27.36 49.025 30.36 ;
     RECT  48.121 33.312 49.025 36.504 ;
     RECT  48.737 51.552 49.025 51.576 ;
     RECT  49.025 27.36 49.045 28.488 ;
     RECT  48.593 2.88 49.061 9.672 ;
     RECT  49.061 3.648 49.097 9.672 ;
     RECT  48.949 21.456 49.097 25.032 ;
     RECT  49.097 22.032 49.129 25.032 ;
     RECT  49.045 26.736 49.132 28.488 ;
     RECT  49.025 35.76 49.205 36.504 ;
     RECT  47.873 40.128 49.205 40.152 ;
     RECT  48.521 41.904 49.241 47.16 ;
     RECT  48.949 20.016 49.273 20.04 ;
     RECT  49.025 33.312 49.313 34.2 ;
     RECT  47.045 53.808 49.313 53.88 ;
     RECT  49.273 20.016 49.333 20.088 ;
     RECT  49.129 22.032 49.417 25.32 ;
     RECT  48.625 38.64 49.417 38.664 ;
     RECT  49.417 22.032 49.453 25.368 ;
     RECT  49.241 45.168 49.453 47.16 ;
     RECT  49.453 22.032 49.489 25.464 ;
     RECT  49.241 41.904 49.561 44.136 ;
     RECT  49.453 45.168 49.561 47.208 ;
     RECT  49.417 38.544 49.597 38.808 ;
     RECT  48.737 11.376 49.601 12.456 ;
     RECT  49.489 22.032 49.619 25.704 ;
     RECT  48.557 13.824 49.633 18.84 ;
     RECT  49.561 41.472 49.633 44.136 ;
     RECT  49.025 29.904 49.669 30.36 ;
     RECT  48.233 31.872 49.669 32.232 ;
     RECT  49.205 36.48 49.669 36.504 ;
     RECT  49.097 3.696 49.709 8.184 ;
     RECT  49.669 36.48 49.715 37.032 ;
     RECT  48.557 48.528 49.745 48.552 ;
     RECT  49.597 38.544 49.813 39.672 ;
     RECT  49.313 53.856 49.853 53.88 ;
     RECT  49.601 11.376 49.916 11.784 ;
     RECT  49.633 13.68 49.925 18.84 ;
     RECT  49.925 13.68 49.957 14.856 ;
     RECT  49.813 38.448 49.957 39.672 ;
     RECT  49.925 16.08 49.993 18.84 ;
     RECT  49.333 19.968 49.993 20.088 ;
     RECT  49.313 33.84 49.993 34.2 ;
     RECT  49.715 37.008 50.029 37.032 ;
     RECT  49.957 38.4 50.029 39.672 ;
     RECT  49.669 29.904 50.065 32.232 ;
     RECT  49.633 41.424 50.065 44.136 ;
     RECT  49.561 45.168 50.065 47.352 ;
     RECT  49.709 3.696 50.101 6.696 ;
     RECT  50.065 29.568 50.101 32.232 ;
     RECT  50.029 37.008 50.209 39.672 ;
     RECT  49.097 9.264 50.281 9.672 ;
     RECT  50.209 37.008 50.389 40.008 ;
     RECT  50.065 41.04 50.389 44.136 ;
     RECT  48.769 49.536 50.389 50.424 ;
     RECT  49.916 11.28 50.533 11.784 ;
     RECT  50.101 3.648 50.569 6.696 ;
     RECT  50.281 9.264 50.713 9.816 ;
     RECT  50.389 37.008 50.725 44.136 ;
     RECT  49.132 27.168 50.749 28.488 ;
     RECT  50.101 29.568 50.749 32.856 ;
     RECT  49.993 33.84 50.749 35.352 ;
     RECT  50.725 36.816 50.749 44.136 ;
     RECT  49.619 22.032 50.785 25.464 ;
     RECT  50.749 33.84 50.857 44.136 ;
     RECT  50.065 45.168 50.857 48.504 ;
     RECT  49.709 7.68 50.929 8.184 ;
     RECT  50.785 21.936 50.929 25.464 ;
     RECT  50.569 3.6 51.008 6.696 ;
     RECT  50.929 7.68 51.008 8.28 ;
     RECT  50.713 9.264 51.008 9.864 ;
     RECT  50.533 10.896 51.008 11.784 ;
     RECT  49.957 12.768 51.008 14.856 ;
     RECT  49.993 16.08 51.008 20.088 ;
     RECT  50.929 21.792 51.008 25.464 ;
     RECT  50.749 27.168 51.008 32.856 ;
     RECT  50.857 33.84 51.008 48.504 ;
     RECT  50.389 49.488 51.008 50.424 ;
     RECT  51.008 2.148 51.112 51.852 ;
     RECT  51.112 2.418 51.304 51.582 ;
     RECT  51.304 5.568 51.329 6.408 ;
     RECT  51.329 5.568 51.437 6.36 ;
     RECT  51.304 9.552 51.437 17.208 ;
     RECT  51.304 40.944 51.545 48.504 ;
     RECT  51.304 36 51.725 39.864 ;
     RECT  51.304 31.776 51.761 34.632 ;
     RECT  51.437 5.568 51.869 6.312 ;
     RECT  51.304 19.536 51.869 25.08 ;
     RECT  51.545 40.944 51.869 48.456 ;
     RECT  51.437 10.704 51.941 17.208 ;
     RECT  51.304 26.544 51.941 30.456 ;
     RECT  51.761 31.968 51.977 34.632 ;
     RECT  51.869 19.536 52.013 24.936 ;
     RECT  51.941 26.64 52.013 30.456 ;
     RECT  51.977 31.968 52.013 32.328 ;
     RECT  51.977 33.504 52.067 34.632 ;
     RECT  52.013 21.072 52.157 24.936 ;
     RECT  51.725 36.816 52.157 39.864 ;
     RECT  51.304 49.488 52.265 50.424 ;
     RECT  52.013 27.168 52.337 30.456 ;
     RECT  52.265 49.488 52.337 49.848 ;
     RECT  51.304 7.632 52.369 8.28 ;
     RECT  51.437 9.552 52.369 9.72 ;
     RECT  51.304 3.648 52.513 4.44 ;
     RECT  51.869 5.568 52.513 6.024 ;
     RECT  52.337 27.168 52.517 30.216 ;
     RECT  52.513 3.648 52.585 6.024 ;
     RECT  52.013 19.536 52.621 20.088 ;
     RECT  52.369 7.632 52.661 9.72 ;
     RECT  51.941 10.704 52.661 16.392 ;
     RECT  51.869 40.944 52.661 42.744 ;
     RECT  52.661 13.632 52.733 16.392 ;
     RECT  52.661 10.704 52.765 12.456 ;
     RECT  52.585 3.6 52.877 6.024 ;
     RECT  52.733 13.68 52.877 16.392 ;
     RECT  52.517 27.168 52.981 29.112 ;
     RECT  52.661 41.184 52.981 42.744 ;
     RECT  52.661 7.632 53.017 9.144 ;
     RECT  52.765 10.224 53.027 12.456 ;
     RECT  52.981 26.208 53.027 29.112 ;
     RECT  52.873 35.952 53.089 35.976 ;
     RECT  52.157 37.056 53.093 39.864 ;
     RECT  52.013 32.208 53.125 32.328 ;
     RECT  52.067 33.504 53.125 34.2 ;
     RECT  52.877 3.6 53.132 3.96 ;
     RECT  53.125 32.208 53.161 34.2 ;
     RECT  53.089 35.232 53.161 35.976 ;
     RECT  53.093 39.36 53.161 39.864 ;
     RECT  52.981 41.184 53.161 42.888 ;
     RECT  51.869 43.968 53.161 48.456 ;
     RECT  52.621 18.816 53.165 20.088 ;
     RECT  53.161 32.208 53.197 35.976 ;
     RECT  53.132 3.312 53.219 3.96 ;
     RECT  53.197 32.208 53.273 36.072 ;
     RECT  53.161 41.184 53.273 48.456 ;
     RECT  53.273 36.048 53.305 36.072 ;
     RECT  53.093 37.056 53.305 38.184 ;
     RECT  53.027 10.224 53.309 11.976 ;
     RECT  52.877 13.68 53.345 15.24 ;
     RECT  52.157 21.072 53.345 24.408 ;
     RECT  53.273 43.536 53.413 48.456 ;
     RECT  53.219 3.6 53.417 3.96 ;
     RECT  52.877 5.232 53.557 6.024 ;
     RECT  53.017 7.488 53.557 9.144 ;
     RECT  52.877 16.224 53.557 16.392 ;
     RECT  52.517 30.096 53.557 30.216 ;
     RECT  53.557 30.096 53.593 30.408 ;
     RECT  53.593 30.096 53.629 30.84 ;
     RECT  53.305 36.048 53.633 38.184 ;
     RECT  53.417 3.696 53.669 3.96 ;
     RECT  53.557 5.232 53.669 9.144 ;
     RECT  53.413 43.536 53.737 48.504 ;
     RECT  52.337 49.536 53.737 49.848 ;
     RECT  53.161 39.36 53.749 39.96 ;
     RECT  53.273 41.184 53.749 42.312 ;
     RECT  53.629 30.096 53.773 31.176 ;
     RECT  53.557 16.224 53.845 17.208 ;
     RECT  53.737 43.536 53.845 49.848 ;
     RECT  53.345 15.072 53.881 15.24 ;
     RECT  53.845 16.224 53.881 17.496 ;
     RECT  53.027 27.84 53.881 29.112 ;
     RECT  53.773 30.096 53.881 31.224 ;
     RECT  53.669 3.696 53.885 3.72 ;
     RECT  53.881 27.84 53.885 31.224 ;
     RECT  53.273 32.208 53.891 35.064 ;
     RECT  53.669 7.488 53.957 9.144 ;
     RECT  53.027 26.208 53.989 26.664 ;
     RECT  53.309 10.224 54.029 11.784 ;
     RECT  53.989 25.584 54.061 26.664 ;
     RECT  53.345 21.072 54.065 21.096 ;
     RECT  53.845 43.536 54.083 50.184 ;
     RECT  53.957 8.832 54.097 9.144 ;
     RECT  54.029 10.224 54.097 11.736 ;
     RECT  54.097 8.832 54.101 11.736 ;
     RECT  54.101 8.832 54.137 11.496 ;
     RECT  54.137 8.832 54.173 11.304 ;
     RECT  53.749 39.36 54.173 42.312 ;
     RECT  53.669 5.232 54.205 6.024 ;
     RECT  53.345 13.68 54.313 14.088 ;
     RECT  53.881 15.072 54.313 17.496 ;
     RECT  53.885 29.52 54.317 31.224 ;
     RECT  54.313 13.68 54.385 17.496 ;
     RECT  53.345 22.176 54.385 24.408 ;
     RECT  54.061 25.584 54.385 26.808 ;
     RECT  54.083 43.536 54.385 49.608 ;
     RECT  53.165 19.008 54.421 20.088 ;
     RECT  54.385 13.68 54.457 17.784 ;
     RECT  54.421 19.008 54.457 20.952 ;
     RECT  54.317 29.808 54.461 31.224 ;
     RECT  54.457 13.68 54.601 20.952 ;
     RECT  54.385 43.344 54.637 49.608 ;
     RECT  54.601 13.632 54.677 20.952 ;
     RECT  54.173 8.832 54.705 11.16 ;
     RECT  53.891 32.208 54.709 34.872 ;
     RECT  54.173 39.744 54.817 42.312 ;
     RECT  54.637 43.296 54.817 49.608 ;
     RECT  54.677 15.984 54.857 20.952 ;
     RECT  53.957 7.488 54.997 7.656 ;
     RECT  53.633 36.048 55.033 37.992 ;
     RECT  54.709 31.92 55.037 34.872 ;
     RECT  54.817 39.744 55.141 49.608 ;
     RECT  54.857 18.72 55.145 20.952 ;
     RECT  54.461 29.808 55.181 30.84 ;
     RECT  54.677 13.632 55.189 14.712 ;
     RECT  55.033 36.048 55.189 38.04 ;
     RECT  54.205 5.136 55.249 6.024 ;
     RECT  54.997 7.344 55.249 7.656 ;
     RECT  54.705 9.024 55.249 11.16 ;
     RECT  55.189 36.048 55.276 38.664 ;
     RECT  55.141 39.744 55.283 50.376 ;
     RECT  55.249 5.136 55.285 7.656 ;
     RECT  55.249 9.024 55.321 11.976 ;
     RECT  55.189 13.104 55.321 14.712 ;
     RECT  54.385 22.176 55.331 26.808 ;
     RECT  55.321 9.024 55.361 14.712 ;
     RECT  55.285 5.136 55.465 7.8 ;
     RECT  55.393 50.88 55.573 51.336 ;
     RECT  55.361 9.024 55.717 12.504 ;
     RECT  55.037 31.968 55.717 34.872 ;
     RECT  55.276 36.048 55.717 38.04 ;
     RECT  55.331 23.808 55.753 26.808 ;
     RECT  53.885 27.84 55.753 28.488 ;
     RECT  54.673 3.984 55.789 4.008 ;
     RECT  55.465 5.088 55.789 7.8 ;
     RECT  55.283 39.744 55.825 49.608 ;
     RECT  55.753 23.808 55.861 28.488 ;
     RECT  55.181 29.808 55.861 30.408 ;
     RECT  55.789 3.984 55.933 7.8 ;
     RECT  55.361 13.632 56.041 14.712 ;
     RECT  54.857 15.984 56.041 17.688 ;
     RECT  55.331 22.176 56.113 22.824 ;
     RECT  55.573 50.88 56.245 51.384 ;
     RECT  56.041 13.632 56.293 17.688 ;
     RECT  55.861 23.808 56.293 30.408 ;
     RECT  56.293 23.808 56.329 30.888 ;
     RECT  55.717 31.968 56.329 38.04 ;
     RECT  56.329 23.808 56.365 38.04 ;
     RECT  55.825 39.024 56.365 49.608 ;
     RECT  56.245 50.88 56.365 51.96 ;
     RECT  55.933 3.888 56.408 7.8 ;
     RECT  55.717 8.832 56.408 12.504 ;
     RECT  56.293 13.632 56.408 17.928 ;
     RECT  55.145 19.2 56.408 20.952 ;
     RECT  56.113 22.032 56.408 22.824 ;
     RECT  56.365 23.808 56.408 49.608 ;
     RECT  56.365 50.88 56.408 52.008 ;
     RECT  55.333 53.04 56.441 53.064 ;
     RECT  56.408 2.148 56.512 52.008 ;
     RECT  56.512 2.418 56.704 52.008 ;
     RECT  56.704 3.888 56.765 5.784 ;
     RECT  56.704 6.864 56.765 20.616 ;
     RECT  56.765 6.864 56.819 16.296 ;
     RECT  56.704 25.536 56.837 26.808 ;
     RECT  56.819 6.864 56.873 7.944 ;
     RECT  56.765 3.888 56.909 5.592 ;
     RECT  56.819 9.024 56.909 16.296 ;
     RECT  56.704 34.704 56.909 52.008 ;
     RECT  56.909 35.856 56.945 52.008 ;
     RECT  56.837 25.536 56.981 26.664 ;
     RECT  56.909 9.36 57.004 16.296 ;
     RECT  57.004 9.36 57.053 10.344 ;
     RECT  56.909 3.888 57.097 5.304 ;
     RECT  56.909 34.704 57.107 34.728 ;
     RECT  56.704 27.936 57.125 27.96 ;
     RECT  57.004 11.952 57.161 16.296 ;
     RECT  56.945 35.856 57.197 51.528 ;
     RECT  57.197 35.856 57.233 42.264 ;
     RECT  56.765 17.904 57.269 20.616 ;
     RECT  57.197 43.248 57.493 51.528 ;
     RECT  57.161 12.48 57.521 16.296 ;
     RECT  57.26 53.904 57.553 53.928 ;
     RECT  56.704 22.272 57.629 24.312 ;
     RECT  57.269 18.816 57.731 20.616 ;
     RECT  57.731 19.296 57.74 20.616 ;
     RECT  56.704 30 57.773 33.096 ;
     RECT  57.493 43.248 57.809 51.336 ;
     RECT  57.74 19.296 57.827 21.576 ;
     RECT  57.553 53.856 57.827 53.928 ;
     RECT  57.233 35.856 57.845 38.808 ;
     RECT  56.981 25.536 57.989 26.52 ;
     RECT  57.773 31.392 58.021 33.096 ;
     RECT  57.827 53.856 58.067 53.88 ;
     RECT  58.021 31.392 58.108 33.816 ;
     RECT  57.053 9.648 58.129 10.344 ;
     RECT  57.773 30 58.129 30.36 ;
     RECT  57.989 26.496 58.165 26.52 ;
     RECT  57.097 4.512 58.201 5.304 ;
     RECT  57.233 39.888 58.213 42.264 ;
     RECT  57.809 43.248 58.213 45.288 ;
     RECT  56.873 7.632 58.345 7.944 ;
     RECT  58.129 9.12 58.345 10.344 ;
     RECT  57.845 36.72 58.355 38.808 ;
     RECT  58.124 17.616 58.453 17.64 ;
     RECT  58.355 38.16 58.453 38.808 ;
     RECT  58.213 39.888 58.453 45.288 ;
     RECT  57.521 12.48 58.499 14.472 ;
     RECT  57.521 16.08 58.499 16.296 ;
     RECT  58.453 17.616 58.525 17.832 ;
     RECT  57.629 22.56 58.529 24.312 ;
     RECT  58.345 7.632 58.561 10.344 ;
     RECT  58.165 26.496 58.565 26.664 ;
     RECT  58.565 26.64 58.633 26.664 ;
     RECT  58.561 7.584 58.693 10.344 ;
     RECT  58.693 6.816 58.739 10.344 ;
     RECT  58.201 4.512 58.745 5.736 ;
     RECT  58.745 5.712 58.777 5.736 ;
     RECT  58.739 6.816 58.777 6.84 ;
     RECT  58.129 29.616 58.777 30.36 ;
     RECT  58.108 31.392 58.777 33 ;
     RECT  58.529 22.56 58.813 24.12 ;
     RECT  58.777 5.712 58.817 6.84 ;
     RECT  58.789 34.032 58.849 34.056 ;
     RECT  58.129 35.424 58.849 35.448 ;
     RECT  58.739 7.92 58.853 10.344 ;
     RECT  58.525 14.496 58.853 14.568 ;
     RECT  58.633 26.64 58.885 27.672 ;
     RECT  58.885 26.64 58.889 27.912 ;
     RECT  58.499 12.48 58.925 13.176 ;
     RECT  58.453 38.16 58.925 45.288 ;
     RECT  58.777 29.088 58.931 33 ;
     RECT  58.889 27.36 59.125 27.912 ;
     RECT  58.925 38.208 59.137 45.288 ;
     RECT  57.809 46.416 59.137 51.336 ;
     RECT  58.853 7.92 59.141 10.248 ;
     RECT  57.827 19.296 59.173 21.384 ;
     RECT  58.813 22.368 59.173 24.12 ;
     RECT  58.745 4.512 59.213 4.536 ;
     RECT  59.101 52.992 59.249 53.016 ;
     RECT  58.525 17.52 59.281 17.832 ;
     RECT  59.173 19.296 59.281 24.12 ;
     RECT  58.853 14.544 59.321 14.568 ;
     RECT  58.499 16.08 59.321 16.248 ;
     RECT  58.355 36.72 59.321 37.032 ;
     RECT  59.141 7.92 59.357 9 ;
     RECT  59.065 25.296 59.357 25.32 ;
     RECT  58.817 5.712 59.429 6.264 ;
     RECT  59.321 16.08 59.501 16.104 ;
     RECT  59.281 17.52 59.533 24.12 ;
     RECT  58.931 30 59.533 33 ;
     RECT  58.849 34.032 59.533 35.448 ;
     RECT  59.125 27.36 59.537 28.776 ;
     RECT  59.429 6.192 59.825 6.264 ;
     RECT  59.533 17.52 59.825 25.08 ;
     RECT  59.533 30 59.843 35.448 ;
     RECT  59.825 17.52 59.861 23.976 ;
     RECT  59.843 30 59.861 34.968 ;
     RECT  59.825 6.192 59.891 6.216 ;
     RECT  59.537 27.36 59.893 27.912 ;
     RECT  59.861 30 59.893 33.672 ;
     RECT  59.861 17.52 59.897 17.832 ;
     RECT  59.357 7.92 59.969 8.952 ;
     RECT  58.925 12.528 60.001 13.176 ;
     RECT  59.893 29.664 60.005 33.672 ;
     RECT  59.861 34.752 60.041 34.968 ;
     RECT  59.861 19.296 60.077 20.472 ;
     RECT  59.137 38.208 60.113 51.336 ;
     RECT  59.141 10.224 60.145 10.248 ;
     RECT  60.113 38.208 60.145 50.328 ;
     RECT  59.861 22.176 60.149 23.976 ;
     RECT  60.145 38.064 60.181 50.328 ;
     RECT  59.893 26.88 60.221 27.912 ;
     RECT  60.149 23.328 60.227 23.976 ;
     RECT  59.825 25.056 60.227 25.08 ;
     RECT  60.005 29.664 60.275 30.36 ;
     RECT  60.001 12.528 60.325 13.32 ;
     RECT  59.321 36.72 60.325 36.744 ;
     RECT  60.181 37.776 60.325 50.328 ;
     RECT  60.325 12.528 60.361 14.088 ;
     RECT  59.969 7.968 60.397 8.952 ;
     RECT  60.397 7.968 60.401 9.096 ;
     RECT  60.227 23.424 60.473 23.976 ;
     RECT  60.005 31.392 60.509 33.672 ;
     RECT  59.569 53.904 60.562 53.928 ;
     RECT  60.401 8.208 60.565 9.096 ;
     RECT  60.145 10.224 60.565 11.016 ;
     RECT  60.565 8.208 60.581 11.016 ;
     RECT  60.509 31.536 60.689 33.672 ;
     RECT  60.275 29.664 60.721 30.168 ;
     RECT  60.721 29.568 60.757 30.168 ;
     RECT  60.041 34.848 61.009 34.968 ;
     RECT  60.562 53.856 61.021 53.928 ;
     RECT  61.009 34.8 61.045 34.968 ;
     RECT  60.221 27.312 61.052 27.912 ;
     RECT  60.757 29.472 61.052 30.168 ;
     RECT  60.149 22.176 61.189 22.2 ;
     RECT  60.473 23.952 61.189 23.976 ;
     RECT  60.077 19.296 61.297 19.992 ;
     RECT  61.045 34.176 61.325 34.968 ;
     RECT  61.297 19.296 61.369 20.088 ;
     RECT  60.113 51.312 61.369 51.336 ;
     RECT  61.225 26.208 61.388 26.232 ;
     RECT  61.369 18.72 61.436 20.088 ;
     RECT  61.189 21.312 61.436 22.2 ;
     RECT  61.189 23.952 61.532 24.504 ;
     RECT  61.436 18.72 61.549 22.2 ;
     RECT  61.388 25.872 61.549 26.232 ;
     RECT  60.325 36.72 61.669 50.328 ;
     RECT  61.369 51.312 61.669 51.432 ;
     RECT  60.581 8.208 61.808 10.92 ;
     RECT  60.361 12.528 61.808 14.232 ;
     RECT  60.721 15.312 61.808 15.336 ;
     RECT  60.433 17.04 61.808 17.064 ;
     RECT  61.549 18.192 61.808 22.2 ;
     RECT  61.532 23.28 61.808 24.504 ;
     RECT  61.549 25.68 61.808 26.232 ;
     RECT  61.052 27.312 61.808 30.168 ;
     RECT  60.689 31.536 61.808 33.096 ;
     RECT  61.325 34.176 61.808 35.112 ;
     RECT  61.669 36.72 61.808 51.432 ;
     RECT  61.808 2.148 61.912 51.852 ;
     RECT  61.912 2.418 62.104 51.582 ;
     RECT  62.104 44.928 62.165 46.104 ;
     RECT  62.104 41.04 62.237 41.736 ;
     RECT  62.104 20.064 62.243 20.088 ;
     RECT  62.104 47.136 62.291 47.88 ;
     RECT  61.369 52.992 62.291 53.016 ;
     RECT  62.104 48.912 62.381 50.808 ;
     RECT  62.104 13.008 62.453 13.176 ;
     RECT  62.165 45.552 62.483 46.104 ;
     RECT  62.483 45.984 62.489 46.104 ;
     RECT  62.381 48.96 62.525 50.808 ;
     RECT  62.489 45.984 62.531 46.008 ;
     RECT  62.525 50.784 62.531 50.808 ;
     RECT  62.104 18.192 62.771 18.888 ;
     RECT  62.453 13.008 62.819 13.032 ;
     RECT  62.771 18.768 62.819 18.888 ;
     RECT  62.104 22.704 62.819 22.824 ;
     RECT  62.104 26.736 62.819 26.856 ;
     RECT  62.104 30.72 62.819 30.84 ;
     RECT  62.104 34.656 62.819 34.872 ;
     RECT  62.525 48.96 62.819 49.8 ;
     RECT  62.291 47.568 62.857 47.88 ;
     RECT  62.819 34.752 62.867 34.872 ;
     RECT  62.104 38.592 62.867 38.808 ;
     RECT  62.104 43.296 62.867 43.944 ;
     RECT  62.819 49.248 62.867 49.8 ;
     RECT  62.104 32.496 62.915 32.52 ;
     RECT  62.867 34.752 62.915 34.776 ;
     RECT  62.237 41.04 62.915 41.064 ;
     RECT  62.867 49.776 62.915 49.8 ;
     RECT  62.867 43.296 62.963 43.32 ;
     RECT  62.857 47.856 62.963 47.88 ;
     RECT  63.241 51.024 63.529 51.144 ;
     RECT  63.529 51.024 63.565 51.336 ;
     RECT  63.565 51.024 63.637 52.008 ;
     RECT  63.637 50.544 63.853 52.008 ;
     RECT  63.853 50.544 64.764 52.104 ;
    LAYER M5 ;
     RECT  6.096 0.037 7.032 0.085 ;
     RECT  32.208 0.016 35.208 0.275 ;
     RECT  6.096 0.085 7.512 0.517 ;
     RECT  32.208 0.275 34.92 0.563 ;
     RECT  10.704 0.016 13.128 1.763 ;
     RECT  32.208 0.563 34.824 1.763 ;
     RECT  32.304 1.763 33 1.811 ;
     RECT  6.096 0.517 7.608 2.137 ;
     RECT  10.896 1.763 13.128 2.137 ;
     RECT  34.8 1.763 34.824 2.137 ;
     RECT  2.4 2.137 2.52 2.151 ;
     RECT  6.096 2.137 7.92 2.151 ;
     RECT  10.896 2.137 13.32 2.151 ;
     RECT  18.6 2.137 18.72 2.151 ;
     RECT  24 2.137 24.12 2.151 ;
     RECT  29.4 2.137 29.52 2.151 ;
     RECT  34.8 2.137 34.92 2.151 ;
     RECT  40.2 2.137 40.32 2.151 ;
     RECT  45.6 2.137 45.72 2.151 ;
     RECT  51 2.137 51.12 2.151 ;
     RECT  56.4 2.137 56.52 2.151 ;
     RECT  61.8 2.137 61.92 2.151 ;
     RECT  2.4 2.151 2.712 2.245 ;
     RECT  6.096 2.151 8.112 2.245 ;
     RECT  9.36 0.037 9.384 2.245 ;
     RECT  10.896 2.151 13.512 2.291 ;
     RECT  11.088 2.291 13.512 2.627 ;
     RECT  24 2.151 24.312 2.773 ;
     RECT  18.6 2.151 18.912 2.821 ;
     RECT  32.592 1.811 33 3.107 ;
     RECT  51 2.151 51.312 3.589 ;
     RECT  45.6 2.151 45.912 3.685 ;
     RECT  28.32 3.637 28.344 3.779 ;
     RECT  15.984 2.773 16.008 3.827 ;
     RECT  56.4 2.151 56.712 3.877 ;
     RECT  6.096 2.245 9.384 3.925 ;
     RECT  10.704 3.301 10.728 3.925 ;
     RECT  11.952 2.627 13.512 3.925 ;
     RECT  24 2.773 24.504 3.971 ;
     RECT  53.184 3.301 53.208 3.971 ;
     RECT  2.4 2.245 2.856 4.019 ;
     RECT  6 3.925 9.384 4.019 ;
     RECT  20.208 2.869 20.232 4.115 ;
     RECT  14.496 3.925 14.52 4.213 ;
     RECT  42.432 3.973 42.456 4.259 ;
     RECT  29.4 2.151 29.712 4.453 ;
     RECT  14.496 4.213 14.952 4.501 ;
     RECT  10.704 3.925 13.512 4.547 ;
     RECT  56.4 3.877 57.048 4.547 ;
     RECT  11.04 4.547 13.512 4.595 ;
     RECT  32.592 3.107 32.904 4.595 ;
     RECT  36.672 3.973 36.696 4.643 ;
     RECT  34.8 2.151 35.112 4.645 ;
     RECT  17.712 2.821 18.912 4.787 ;
     RECT  24 3.971 24.312 5.029 ;
     RECT  40.2 2.151 40.512 5.029 ;
     RECT  50.736 3.589 51.312 5.029 ;
     RECT  45.504 3.685 45.912 5.075 ;
     RECT  6 4.019 8.616 5.077 ;
     RECT  34.176 4.645 35.112 5.077 ;
     RECT  28.944 4.453 29.712 5.123 ;
     RECT  14.496 4.501 15.624 5.171 ;
     RECT  24 5.029 24.504 5.173 ;
     RECT  37.104 5.125 37.128 5.363 ;
     RECT  56.4 4.547 56.712 5.605 ;
     RECT  11.04 4.595 11.064 5.747 ;
     RECT  12.912 4.595 13.512 5.747 ;
     RECT  38.784 5.077 38.808 5.747 ;
     RECT  24 5.173 25.128 6.035 ;
     RECT  29.28 5.123 29.712 6.181 ;
     RECT  43.584 3.733 43.608 6.229 ;
     RECT  50.064 5.029 51.312 6.229 ;
     RECT  49.968 6.229 51.312 6.275 ;
     RECT  36.432 5.653 36.456 6.277 ;
     RECT  33.792 5.077 35.112 6.323 ;
     RECT  36.192 6.277 36.456 6.323 ;
     RECT  40.2 5.029 41.496 6.323 ;
     RECT  18.6 4.787 18.912 6.421 ;
     RECT  29.28 6.181 30.312 6.515 ;
     RECT  14.496 5.171 14.952 6.517 ;
     RECT  42.816 6.229 43.608 6.517 ;
     RECT  49.968 6.275 49.992 6.517 ;
     RECT  48.48 2.869 48.504 6.563 ;
     RECT  11.664 6.709 11.688 6.805 ;
     RECT  21.12 5.989 21.144 6.805 ;
     RECT  42.816 6.517 44.376 6.805 ;
     RECT  24 6.035 24.504 6.851 ;
     RECT  21.12 6.805 21.24 6.853 ;
     RECT  13.2 5.747 13.512 6.901 ;
     RECT  14.496 6.517 15 6.901 ;
     RECT  21.12 6.853 22.056 6.995 ;
     RECT  2.4 4.019 2.712 7.189 ;
     RECT  2.4 7.189 2.808 7.237 ;
     RECT  29.4 6.515 30.312 7.237 ;
     RECT  33.792 6.323 33.816 7.333 ;
     RECT  36.192 6.323 36.216 7.379 ;
     RECT  38.784 6.805 38.808 7.427 ;
     RECT  18.24 6.421 18.912 7.475 ;
     RECT  58.704 6.805 58.728 7.619 ;
     RECT  42.816 6.805 44.52 7.667 ;
     RECT  31.68 5.029 31.704 7.765 ;
     RECT  16.56 6.661 16.584 8.003 ;
     RECT  21.12 6.995 21.24 8.003 ;
     RECT  11.424 6.805 11.688 8.149 ;
     RECT  49.536 6.517 49.992 8.195 ;
     RECT  28.128 7.381 28.152 8.341 ;
     RECT  33.072 7.333 33.816 8.435 ;
     RECT  45.6 5.075 45.912 8.485 ;
     RECT  59.856 6.181 59.88 8.485 ;
     RECT  43.488 7.667 44.52 8.675 ;
     RECT  24 6.851 24.312 8.677 ;
     RECT  53.952 5.893 53.976 8.821 ;
     RECT  55.824 5.605 56.712 8.821 ;
     RECT  5.76 5.077 8.616 9.061 ;
     RECT  61.8 2.151 62.112 9.061 ;
     RECT  5.472 9.061 8.616 9.203 ;
     RECT  2.4 7.237 3.624 9.251 ;
     RECT  59.856 8.485 60.168 9.493 ;
     RECT  61.536 9.061 62.112 9.493 ;
     RECT  33.792 8.435 33.816 9.589 ;
     RECT  11.424 8.149 12.168 9.637 ;
     RECT  38.64 8.821 38.664 9.637 ;
     RECT  45.6 8.485 46.728 9.683 ;
     RECT  23.328 8.677 24.312 9.731 ;
     RECT  27.84 8.341 28.152 9.779 ;
     RECT  43.488 8.675 43.944 9.829 ;
     RECT  13.2 6.901 15 9.923 ;
     RECT  43.488 9.829 44.28 9.925 ;
     RECT  42.624 9.925 44.28 9.971 ;
     RECT  31.68 7.765 31.752 10.115 ;
     RECT  18.6 7.475 18.912 10.165 ;
     RECT  55.824 8.821 56.808 10.165 ;
     RECT  59.856 9.493 62.112 10.213 ;
     RECT  59.616 10.213 62.112 10.307 ;
     RECT  2.4 9.251 2.904 10.693 ;
     RECT  4.368 9.349 4.392 10.693 ;
     RECT  5.472 9.203 8.112 10.693 ;
     RECT  42.624 9.971 43.944 10.739 ;
     RECT  18.24 10.165 18.912 10.741 ;
     RECT  21.12 8.003 21.144 10.789 ;
     RECT  24 9.731 24.312 10.789 ;
     RECT  21.12 10.789 21.48 10.835 ;
     RECT  29.4 7.237 30.408 10.837 ;
     RECT  45.6 9.683 46.488 10.979 ;
     RECT  18.24 10.741 19.272 11.075 ;
     RECT  2.4 10.693 8.112 11.171 ;
     RECT  26.208 10.213 26.232 11.363 ;
     RECT  34.8 6.323 35.112 11.365 ;
     RECT  53.952 8.821 54.648 11.365 ;
     RECT  48.192 10.213 48.216 11.411 ;
     RECT  10.608 9.637 12.168 11.459 ;
     RECT  14.976 9.923 15 11.459 ;
     RECT  18.384 11.075 19.272 11.555 ;
     RECT  10.8 11.459 12.168 11.747 ;
     RECT  3.792 11.171 8.112 11.941 ;
     RECT  28.032 9.779 28.152 11.941 ;
     RECT  36.48 8.533 36.504 12.467 ;
     RECT  52.992 11.365 54.648 12.467 ;
     RECT  2.4 11.171 2.712 12.517 ;
     RECT  3.792 11.941 8.472 12.517 ;
     RECT  31.728 10.115 31.752 12.517 ;
     RECT  33.072 9.589 33.816 12.517 ;
     RECT  38.64 9.637 38.904 12.517 ;
     RECT  40.2 6.323 40.512 12.517 ;
     RECT  27.888 11.941 28.152 12.563 ;
     RECT  49.968 8.195 49.992 12.757 ;
     RECT  51 6.275 51.312 12.757 ;
     RECT  49.968 12.757 51.312 12.803 ;
     RECT  58.464 8.965 58.488 12.805 ;
     RECT  59.616 10.307 60.696 12.805 ;
     RECT  38.64 12.517 40.512 12.853 ;
     RECT  16.32 8.725 16.344 12.901 ;
     RECT  18.6 11.555 19.272 12.947 ;
     RECT  61.8 10.307 62.112 12.997 ;
     RECT  42.864 10.739 43.944 13.045 ;
     RECT  45.6 10.979 45.912 13.045 ;
     RECT  2.4 12.517 8.472 13.091 ;
     RECT  58.464 12.805 60.696 13.091 ;
     RECT  31.728 12.517 33.816 13.093 ;
     RECT  34.8 11.365 35.304 13.093 ;
     RECT  53.952 12.467 54.648 13.093 ;
     RECT  55.824 10.165 57.144 13.093 ;
     RECT  38.16 12.853 40.512 13.523 ;
     RECT  29.28 10.837 30.408 13.525 ;
     RECT  23.664 10.789 24.312 13.571 ;
     RECT  42.768 13.045 43.944 13.621 ;
     RECT  45.6 13.045 46.344 13.621 ;
     RECT  31.728 13.093 36.024 13.715 ;
     RECT  38.16 13.523 38.664 13.715 ;
     RECT  33.072 13.715 36.024 13.859 ;
     RECT  28.032 12.563 28.152 14.005 ;
     RECT  53.952 13.093 57.144 14.005 ;
     RECT  58.464 13.091 58.488 14.005 ;
     RECT  14.928 11.845 14.952 14.053 ;
     RECT  14.784 14.053 14.952 14.099 ;
     RECT  14.784 14.099 14.808 14.197 ;
     RECT  27.888 14.005 28.152 14.197 ;
     RECT  25.824 13.093 25.848 14.243 ;
     RECT  11.424 11.747 12.168 14.245 ;
     RECT  13.2 9.923 13.512 14.245 ;
     RECT  16.32 12.901 16.92 14.291 ;
     RECT  21.456 10.835 21.48 14.341 ;
     RECT  27.264 14.197 28.152 14.389 ;
     RECT  29.184 13.525 30.408 14.389 ;
     RECT  33.072 13.859 35.304 14.627 ;
     RECT  53.952 14.005 58.488 15.061 ;
     RECT  11.424 14.245 13.512 15.157 ;
     RECT  14.736 14.197 14.808 15.157 ;
     RECT  11.424 15.157 14.808 15.299 ;
     RECT  24 13.571 24.312 15.349 ;
     RECT  42.768 13.621 46.344 15.349 ;
     RECT  2.4 13.091 8.112 15.397 ;
     RECT  42.768 15.349 47.304 15.443 ;
     RECT  52.704 14.197 52.728 15.443 ;
     RECT  20.928 14.341 21.48 15.491 ;
     RECT  34.8 14.627 35.304 15.589 ;
     RECT  11.424 15.299 13.512 15.827 ;
     RECT  18.6 12.947 18.912 15.925 ;
     RECT  2.4 15.397 8.808 15.973 ;
     RECT  24 15.349 24.792 16.019 ;
     RECT  50.112 12.803 51.312 16.501 ;
     RECT  21.312 15.491 21.48 16.547 ;
     RECT  43.488 15.443 47.304 16.547 ;
     RECT  34.8 15.589 35.352 16.549 ;
     RECT  45.6 16.547 47.304 16.643 ;
     RECT  39.648 13.523 40.512 16.693 ;
     RECT  16.32 14.291 16.344 16.789 ;
     RECT  17.616 15.925 18.912 16.789 ;
     RECT  16.32 16.789 18.912 16.835 ;
     RECT  13.2 15.827 13.512 16.885 ;
     RECT  14.736 15.299 14.808 16.885 ;
     RECT  13.2 16.885 14.808 16.931 ;
     RECT  16.32 16.835 17.16 16.979 ;
     RECT  27.264 14.389 30.408 17.029 ;
     RECT  49.632 16.501 51.312 17.075 ;
     RECT  2.304 15.973 8.808 17.077 ;
     RECT  37.056 16.981 37.08 17.123 ;
     RECT  53.808 15.061 58.488 17.171 ;
     RECT  2.304 17.077 9.192 17.219 ;
     RECT  20.016 16.885 20.04 17.317 ;
     RECT  26.88 17.029 30.408 17.363 ;
     RECT  11.424 15.827 12.168 17.461 ;
     RECT  13.2 16.931 14.472 17.461 ;
     RECT  42.384 17.029 42.408 17.699 ;
     RECT  53.952 17.171 58.488 17.843 ;
     RECT  21.456 16.547 21.48 17.941 ;
     RECT  20.016 17.317 20.136 18.181 ;
     RECT  21.456 17.941 21.624 18.181 ;
     RECT  43.488 16.547 44.424 18.181 ;
     RECT  45.6 16.643 46.344 18.181 ;
     RECT  18.48 16.835 18.912 18.227 ;
     RECT  31.728 13.715 31.752 18.277 ;
     RECT  33.072 14.627 33.816 18.277 ;
     RECT  25.728 17.317 25.752 18.419 ;
     RECT  20.016 18.181 21.624 18.467 ;
     RECT  39.648 16.693 41.4 18.565 ;
     RECT  59.616 13.091 60.696 18.709 ;
     RECT  61.8 12.997 62.808 18.709 ;
     RECT  31.728 18.277 33.816 18.757 ;
     RECT  34.8 16.549 35.4 18.757 ;
     RECT  49.632 17.075 49.656 18.805 ;
     RECT  51 17.075 51.312 18.805 ;
     RECT  20.016 18.467 21.096 18.851 ;
     RECT  43.488 18.181 46.344 18.851 ;
     RECT  31.728 18.757 35.4 18.899 ;
     RECT  27.264 17.363 30.408 19.331 ;
     RECT  39.648 18.565 41.592 19.427 ;
     RECT  31.728 18.899 35.208 19.523 ;
     RECT  50.88 18.805 51.312 19.525 ;
     RECT  50.88 19.525 51.96 19.571 ;
     RECT  53.952 17.843 58.2 19.669 ;
     RECT  59.616 18.709 62.808 19.669 ;
     RECT  45.6 18.851 46.344 19.909 ;
     RECT  33.072 19.523 35.208 20.003 ;
     RECT  49.344 18.805 49.656 20.003 ;
     RECT  27.36 19.331 30.408 20.339 ;
     RECT  9.6 19.333 9.624 20.579 ;
     RECT  34.8 20.003 35.208 20.579 ;
     RECT  45.6 19.909 47.112 20.579 ;
     RECT  51 19.571 51.96 20.579 ;
     RECT  31.728 19.523 31.752 20.725 ;
     RECT  2.304 17.219 8.112 20.821 ;
     RECT  45.6 20.579 46.344 20.965 ;
     RECT  16.32 16.979 16.344 21.013 ;
     RECT  38.64 13.715 38.664 21.013 ;
     RECT  2.304 20.821 9.048 21.059 ;
     RECT  45.504 20.965 46.344 21.203 ;
     RECT  31.68 20.725 31.752 21.347 ;
     RECT  20.016 18.851 20.184 21.637 ;
     RECT  36.768 20.293 36.792 21.683 ;
     RECT  38.208 21.013 38.664 21.683 ;
     RECT  43.488 18.851 44.52 22.163 ;
     RECT  16.32 21.013 16.872 22.211 ;
     RECT  49.632 20.003 49.656 22.501 ;
     RECT  18.6 18.227 18.912 22.597 ;
     RECT  20.016 21.637 20.232 22.597 ;
     RECT  49.008 22.501 49.656 22.643 ;
     RECT  24 16.019 24.312 22.693 ;
     RECT  20.016 22.597 20.28 23.123 ;
     RECT  49.632 22.643 49.656 23.555 ;
     RECT  33.072 20.003 33.816 23.653 ;
     RECT  17.712 22.597 18.912 23.843 ;
     RECT  23.664 22.693 24.312 23.845 ;
     RECT  31.728 21.347 31.752 23.941 ;
     RECT  33.024 23.653 33.816 23.941 ;
     RECT  43.488 22.163 44.472 23.987 ;
     RECT  42.432 23.317 42.456 24.035 ;
     RECT  26.784 23.173 26.808 24.131 ;
     RECT  20.016 23.123 20.232 24.373 ;
     RECT  37.056 23.317 37.08 24.515 ;
     RECT  11.424 17.461 14.472 24.757 ;
     RECT  16.32 22.211 16.344 24.757 ;
     RECT  28.032 20.339 30.408 24.757 ;
     RECT  31.728 23.941 33.816 24.757 ;
     RECT  20.016 24.373 20.28 24.805 ;
     RECT  43.488 23.987 44.184 25.045 ;
     RECT  45.6 21.203 46.344 25.045 ;
     RECT  22.752 23.845 24.312 25.139 ;
     RECT  39.648 19.427 41.4 25.141 ;
     RECT  16.32 24.757 17.112 25.187 ;
     RECT  20.016 24.805 20.52 25.187 ;
     RECT  42.72 25.045 44.184 25.187 ;
     RECT  49.584 24.901 49.608 25.715 ;
     RECT  20.112 25.187 20.52 25.763 ;
     RECT  11.424 24.757 15.192 26.197 ;
     RECT  16.32 25.187 16.344 26.197 ;
     RECT  38.64 21.683 38.664 26.197 ;
     RECT  39.648 25.141 41.688 26.197 ;
     RECT  53.952 19.669 62.808 26.197 ;
     RECT  11.424 26.197 16.344 26.243 ;
     RECT  28.032 24.757 33.816 26.243 ;
     RECT  38.64 26.197 41.688 26.243 ;
     RECT  48 24.469 48.024 26.243 ;
     RECT  11.424 26.243 14.472 26.291 ;
     RECT  45.6 25.045 46.92 26.531 ;
     RECT  23.664 25.139 24.312 26.725 ;
     RECT  23.664 26.725 24.552 26.821 ;
     RECT  20.112 25.763 20.28 26.965 ;
     RECT  23.664 26.821 25.272 26.965 ;
     RECT  43.488 25.187 44.184 27.155 ;
     RECT  20.112 26.965 20.472 27.301 ;
     RECT  38.64 26.243 41.4 27.301 ;
     RECT  20.112 27.301 21.288 27.347 ;
     RECT  49.056 26.725 49.08 27.395 ;
     RECT  33.072 26.243 33.816 27.397 ;
     RECT  34.8 20.579 35.112 27.397 ;
     RECT  38.64 27.301 42.216 27.443 ;
     RECT  23.664 26.965 25.368 27.635 ;
     RECT  23.664 27.635 25.272 27.779 ;
     RECT  20.112 27.347 20.184 27.877 ;
     RECT  15.84 26.243 16.344 28.163 ;
     RECT  43.488 27.155 43.944 28.357 ;
     RECT  45.6 26.531 46.344 28.357 ;
     RECT  21.264 27.347 21.288 28.405 ;
     RECT  21.264 28.405 21.48 28.451 ;
     RECT  16.32 28.163 16.344 28.453 ;
     RECT  48.048 28.357 48.072 28.453 ;
     RECT  39.648 27.443 42.216 28.499 ;
     RECT  43.488 28.357 46.344 28.499 ;
     RECT  52.992 26.197 62.808 28.499 ;
     RECT  33.072 27.397 35.112 28.837 ;
     RECT  36.288 27.925 36.312 28.837 ;
     RECT  33.072 28.837 36.312 28.885 ;
     RECT  33.072 28.885 36.456 28.931 ;
     RECT  19.968 27.877 20.184 28.979 ;
     RECT  38.64 27.443 38.664 28.981 ;
     RECT  16.32 28.453 17.256 29.365 ;
     RECT  15.936 29.365 17.256 29.411 ;
     RECT  18.6 23.843 18.912 29.605 ;
     RECT  45.6 28.499 46.344 29.605 ;
     RECT  51 20.579 51.312 29.605 ;
     RECT  36.432 28.931 36.456 29.699 ;
     RECT  26.736 27.877 26.76 29.701 ;
     RECT  28.032 26.243 31.752 29.701 ;
     RECT  20.16 28.979 20.184 29.749 ;
     RECT  11.424 26.291 14.088 29.893 ;
     RECT  26.736 29.701 31.752 29.987 ;
     RECT  39.648 28.499 41.4 30.229 ;
     RECT  26.736 29.987 26.808 30.373 ;
     RECT  2.304 21.059 8.112 30.757 ;
     RECT  38.352 28.981 38.664 30.757 ;
     RECT  43.488 28.499 43.944 30.757 ;
     RECT  2.304 30.757 8.424 30.901 ;
     RECT  2.304 30.901 9.336 30.995 ;
     RECT  50.112 29.605 51.312 31.045 ;
     RECT  39.648 30.229 42.12 31.091 ;
     RECT  49.68 31.045 51.312 31.091 ;
     RECT  20.16 29.749 20.328 31.141 ;
     RECT  10.848 29.893 14.088 31.235 ;
     RECT  15.936 29.411 16.344 31.285 ;
     RECT  18.24 29.605 18.912 31.285 ;
     RECT  26.016 30.373 26.808 31.379 ;
     RECT  47.472 28.453 48.072 31.379 ;
     RECT  26.016 31.379 26.76 31.429 ;
     RECT  25.632 31.429 26.76 31.475 ;
     RECT  9.312 30.995 9.336 31.669 ;
     RECT  10.848 31.235 13.992 31.669 ;
     RECT  20.16 31.141 20.424 31.861 ;
     RECT  19.92 31.861 20.424 31.907 ;
     RECT  9.312 31.669 13.992 31.955 ;
     RECT  18 31.285 18.912 31.955 ;
     RECT  39.648 31.091 41.4 32.053 ;
     RECT  23.664 27.779 24.552 32.197 ;
     RECT  25.632 31.475 25.656 32.197 ;
     RECT  47.904 31.379 48.072 32.243 ;
     RECT  28.032 29.987 31.752 32.341 ;
     RECT  43.488 30.757 44.04 32.389 ;
     RECT  45.024 29.605 46.344 32.389 ;
     RECT  43.488 32.389 46.344 32.435 ;
     RECT  36.624 30.469 36.648 32.483 ;
     RECT  53.952 28.499 62.808 32.485 ;
     RECT  21.456 28.451 21.48 32.531 ;
     RECT  2.304 30.995 8.112 32.677 ;
     RECT  9.312 31.955 10.296 32.677 ;
     RECT  18.24 31.955 18.912 32.725 ;
     RECT  19.92 31.907 20.184 32.725 ;
     RECT  11.376 31.955 13.992 32.819 ;
     RECT  2.304 32.677 10.296 32.915 ;
     RECT  15.36 31.285 16.344 32.917 ;
     RECT  33.072 28.931 35.4 33.107 ;
     RECT  14.496 32.917 16.344 33.251 ;
     RECT  39.648 32.053 42.312 33.443 ;
     RECT  38.112 30.757 38.664 33.445 ;
     RECT  51 31.091 51.312 33.493 ;
     RECT  23.664 32.197 25.656 33.539 ;
     RECT  18.24 32.725 20.184 33.635 ;
     RECT  26.736 31.475 26.76 33.637 ;
     RECT  28.032 32.341 31.896 33.637 ;
     RECT  48.048 32.243 48.072 33.683 ;
     RECT  11.376 32.819 13.512 33.875 ;
     RECT  9.312 32.915 10.296 34.117 ;
     RECT  37.488 33.445 38.664 34.165 ;
     RECT  26.736 33.637 31.896 34.211 ;
     RECT  51 33.493 52.056 34.643 ;
     RECT  9.312 34.117 10.344 34.691 ;
     RECT  20.16 33.635 20.184 34.741 ;
     RECT  53.952 32.485 62.904 34.787 ;
     RECT  33.168 33.107 35.4 34.835 ;
     RECT  53.952 34.787 62.856 35.029 ;
     RECT  14.496 33.251 14.52 35.171 ;
     RECT  23.664 33.539 25.416 35.171 ;
     RECT  9.408 34.691 10.344 35.413 ;
     RECT  37.344 34.165 38.664 35.555 ;
     RECT  9.408 35.413 10.44 35.603 ;
     RECT  34.8 34.835 35.4 35.653 ;
     RECT  9.408 35.603 10.344 35.747 ;
     RECT  18.24 33.635 18.912 35.845 ;
     RECT  20.16 34.741 20.424 35.845 ;
     RECT  23.664 35.171 24.552 35.845 ;
     RECT  33.168 34.835 33.816 35.989 ;
     RECT  39.648 33.443 41.4 36.085 ;
     RECT  32.976 35.989 33.816 36.131 ;
     RECT  9.984 35.747 10.344 36.275 ;
     RECT  10.032 36.275 10.344 36.515 ;
     RECT  18.24 35.845 20.424 36.515 ;
     RECT  22.8 35.845 24.552 36.515 ;
     RECT  49.68 31.091 49.704 36.515 ;
     RECT  18.24 36.515 20.184 36.611 ;
     RECT  51 34.643 51.312 36.805 ;
     RECT  45.6 32.435 46.344 36.901 ;
     RECT  15.648 33.251 16.344 36.997 ;
     RECT  50.736 36.805 51.312 36.997 ;
     RECT  39.648 36.085 42.12 37.043 ;
     RECT  15.648 36.997 17.112 37.045 ;
     RECT  18.24 36.611 19.56 37.045 ;
     RECT  15.648 37.045 19.56 37.091 ;
     RECT  15.648 37.091 18.912 37.235 ;
     RECT  43.488 32.435 44.28 37.237 ;
     RECT  15.648 37.235 17.208 37.283 ;
     RECT  37.728 35.555 38.664 37.429 ;
     RECT  39.648 37.043 41.4 37.429 ;
     RECT  53.856 35.029 62.856 37.523 ;
     RECT  42.96 37.237 44.28 37.621 ;
     RECT  47.904 35.173 47.928 37.621 ;
     RECT  45.6 36.901 46.392 37.667 ;
     RECT  47.424 37.621 47.928 37.667 ;
     RECT  2.304 32.915 8.112 37.861 ;
     RECT  37.728 37.429 41.4 38.149 ;
     RECT  42.96 37.621 44.376 38.243 ;
     RECT  37.488 38.149 41.4 38.291 ;
     RECT  2.304 37.861 8.328 38.389 ;
     RECT  44.352 38.243 44.376 38.435 ;
     RECT  47.424 37.667 47.448 38.435 ;
     RECT  10.032 36.515 10.056 38.483 ;
     RECT  37.488 38.291 38.664 38.723 ;
     RECT  2.304 38.389 8.376 39.011 ;
     RECT  2.304 39.011 8.328 39.203 ;
     RECT  26.736 34.211 31.752 39.587 ;
     RECT  38.064 38.723 38.664 39.589 ;
     RECT  39.648 38.291 41.4 39.589 ;
     RECT  23.664 36.515 24.552 39.829 ;
     RECT  11.424 33.875 13.512 39.877 ;
     RECT  18.24 37.235 18.912 39.877 ;
     RECT  38.064 39.589 41.4 39.923 ;
     RECT  23.184 39.829 24.552 39.925 ;
     RECT  23.184 39.925 25.32 40.067 ;
     RECT  23.664 40.067 25.32 40.165 ;
     RECT  26.736 39.587 26.76 40.165 ;
     RECT  11.136 39.877 13.512 40.595 ;
     RECT  18.24 39.877 19.8 40.595 ;
     RECT  23.664 40.165 26.76 40.643 ;
     RECT  28.032 39.587 31.752 40.741 ;
     RECT  53.952 37.523 62.856 40.741 ;
     RECT  42.96 38.243 42.984 40.789 ;
     RECT  27.648 40.741 31.752 40.885 ;
     RECT  53.76 40.741 62.856 41.029 ;
     RECT  52.368 41.077 52.392 41.219 ;
     RECT  42.864 40.789 42.984 41.221 ;
     RECT  23.664 40.643 25.944 41.267 ;
     RECT  18.24 40.595 19.08 41.651 ;
     RECT  23.664 41.267 25.656 41.797 ;
     RECT  50.112 36.997 51.312 41.939 ;
     RECT  22.896 41.797 25.656 42.083 ;
     RECT  53.76 41.029 62.904 42.179 ;
     RECT  42.864 41.221 43.08 42.517 ;
     RECT  42.672 42.517 43.08 42.803 ;
     RECT  9.12 40.309 9.144 42.995 ;
     RECT  25.632 42.083 25.656 43.139 ;
     RECT  2.304 39.203 8.112 43.141 ;
     RECT  33.072 36.131 33.816 43.189 ;
     RECT  34.8 35.653 35.88 43.189 ;
     RECT  42.864 42.803 43.08 43.285 ;
     RECT  53.952 42.179 62.904 43.285 ;
     RECT  18.24 41.651 19.032 43.571 ;
     RECT  22.896 42.083 24.552 43.573 ;
     RECT  15.648 37.283 16.344 44.053 ;
     RECT  33.072 43.189 35.88 44.053 ;
     RECT  45.6 37.667 46.344 44.101 ;
     RECT  2.304 43.141 9.096 44.243 ;
     RECT  18.24 43.571 18.912 44.245 ;
     RECT  33.024 44.053 35.88 44.339 ;
     RECT  15.648 44.053 16.728 44.389 ;
     RECT  42.864 43.285 43.56 44.437 ;
     RECT  33.024 44.339 35.544 44.483 ;
     RECT  42.768 44.437 43.56 44.483 ;
     RECT  27.648 40.885 31.848 44.869 ;
     RECT  14.784 44.389 16.728 45.011 ;
     RECT  18.096 44.245 18.912 45.059 ;
     RECT  22.896 43.573 24.648 45.059 ;
     RECT  18.24 45.059 18.912 45.541 ;
     RECT  21.504 44.245 21.528 45.635 ;
     RECT  27.264 44.869 31.848 45.827 ;
     RECT  38.112 39.923 41.4 45.925 ;
     RECT  42.768 44.483 43.224 45.925 ;
     RECT  22.896 45.059 24.552 46.163 ;
     RECT  34.8 44.483 35.544 46.165 ;
     RECT  15.648 45.011 16.728 46.211 ;
     RECT  33.024 44.483 33.816 46.211 ;
     RECT  50.4 41.939 51.312 46.213 ;
     RECT  16.32 46.211 16.728 46.259 ;
     RECT  53.952 43.285 62.952 46.261 ;
     RECT  23.664 46.163 24.552 46.405 ;
     RECT  38.112 45.925 43.224 46.405 ;
     RECT  38.112 46.405 43.32 46.451 ;
     RECT  53.04 46.261 62.952 46.451 ;
     RECT  18.24 45.541 19.512 46.643 ;
     RECT  21.696 46.117 21.72 46.693 ;
     RECT  33.072 46.211 33.816 46.787 ;
     RECT  21.552 46.693 21.72 46.883 ;
     RECT  18.24 46.643 19.08 47.171 ;
     RECT  16.704 46.259 16.728 47.267 ;
     RECT  10.08 44.341 10.104 47.317 ;
     RECT  11.424 40.595 13.512 47.317 ;
     RECT  2.304 44.243 8.112 47.363 ;
     RECT  34.8 46.165 35.928 47.363 ;
     RECT  27.264 45.827 31.752 47.461 ;
     RECT  33.072 46.787 33.096 47.461 ;
     RECT  0.192 27.157 0.216 47.603 ;
     RECT  53.952 46.451 62.952 47.891 ;
     RECT  43.296 46.451 43.32 47.939 ;
     RECT  27.264 47.461 33.096 47.989 ;
     RECT  50.4 46.213 51.576 48.083 ;
     RECT  53.952 47.891 62.904 48.179 ;
     RECT  27.264 47.989 33.288 48.373 ;
     RECT  27.072 48.373 33.288 48.421 ;
     RECT  38.112 46.451 42.168 48.421 ;
     RECT  45.6 44.101 46.536 48.421 ;
     RECT  6 47.363 8.112 48.515 ;
     RECT  23.664 46.405 25.128 48.611 ;
     RECT  2.304 47.363 4.584 48.659 ;
     RECT  7.344 48.515 8.112 48.755 ;
     RECT  18.24 47.171 18.912 48.805 ;
     RECT  26.208 48.421 33.528 48.901 ;
     RECT  2.304 48.659 3.816 49.043 ;
     RECT  4.8 48.853 4.824 49.043 ;
     RECT  6 48.515 6.072 49.043 ;
     RECT  10.08 47.317 13.512 49.043 ;
     RECT  26.208 48.901 33.768 49.043 ;
     RECT  32.832 49.043 33.768 49.091 ;
     RECT  37.584 48.421 42.168 49.091 ;
     RECT  34.8 47.363 35.544 49.381 ;
     RECT  15.024 48.853 15.048 49.427 ;
     RECT  33.024 49.091 33.768 49.475 ;
     RECT  50.4 48.083 51.312 49.523 ;
     RECT  2.304 49.043 3.672 49.619 ;
     RECT  6.048 49.043 6.072 49.619 ;
     RECT  23.664 48.611 24.456 49.619 ;
     RECT  26.208 49.043 31.752 49.619 ;
     RECT  44.736 48.421 46.536 49.619 ;
     RECT  54.048 48.179 62.904 49.619 ;
     RECT  2.304 49.619 3.144 49.667 ;
     RECT  55.248 49.619 62.904 49.811 ;
     RECT  21.696 46.883 21.72 50.053 ;
     RECT  33.072 49.475 33.768 50.101 ;
     RECT  10.08 49.043 10.44 50.195 ;
     RECT  21.648 50.053 21.72 50.195 ;
     RECT  33.072 50.101 33.816 50.195 ;
     RECT  34.8 49.381 36.504 50.195 ;
     RECT  37.584 49.091 41.4 50.195 ;
     RECT  45.6 49.619 46.248 50.195 ;
     RECT  54.048 49.619 54.072 50.195 ;
     RECT  55.248 49.811 62.52 50.195 ;
     RECT  49.44 49.525 49.464 50.435 ;
     RECT  11.952 49.043 13.512 50.531 ;
     RECT  26.448 49.619 31.752 50.677 ;
     RECT  17.28 48.805 18.912 50.771 ;
     RECT  26.448 50.677 32.52 50.771 ;
     RECT  55.344 50.195 62.52 50.819 ;
     RECT  33.792 50.195 33.816 50.963 ;
     RECT  45.6 50.195 46.104 51.205 ;
     RECT  12.144 50.531 13.512 51.253 ;
     RECT  15.312 50.677 15.336 51.253 ;
     RECT  36.48 50.195 36.504 51.299 ;
     RECT  12.144 51.253 13.896 51.301 ;
     RECT  15.312 51.253 15.528 51.301 ;
     RECT  45.6 51.205 46.344 51.301 ;
     RECT  47.952 48.421 47.976 51.301 ;
     RECT  2.4 49.667 3.144 51.347 ;
     RECT  12.144 51.301 13.992 51.347 ;
     RECT  28.848 50.771 32.52 51.347 ;
     RECT  55.344 50.819 62.28 51.347 ;
     RECT  18.48 50.771 18.912 51.395 ;
     RECT  13.2 51.347 13.992 51.397 ;
     RECT  15.12 51.301 15.72 51.397 ;
     RECT  38.832 50.195 41.208 51.491 ;
     RECT  13.2 51.397 15.72 51.493 ;
     RECT  45.6 51.301 48.168 51.541 ;
     RECT  21.648 50.195 21.672 51.635 ;
     RECT  7.8 48.755 8.112 51.849 ;
     RECT  18.6 51.395 18.912 51.849 ;
     RECT  24 49.619 24.312 51.849 ;
     RECT  34.8 50.195 35.112 51.849 ;
     RECT  38.832 51.491 40.512 51.849 ;
     RECT  51 49.523 51.312 51.849 ;
     RECT  2.4 51.347 2.856 51.863 ;
     RECT  7.8 51.849 7.92 51.863 ;
     RECT  13.2 51.493 16.392 51.863 ;
     RECT  18.6 51.849 18.72 51.863 ;
     RECT  24 51.849 24.12 51.863 ;
     RECT  34.8 51.849 34.92 51.863 ;
     RECT  38.832 51.849 40.32 51.863 ;
     RECT  45.6 51.541 48.648 51.863 ;
     RECT  51 51.849 51.12 51.863 ;
     RECT  55.344 51.347 58.056 51.863 ;
     RECT  59.664 51.347 62.28 51.863 ;
     RECT  55.344 51.863 56.28 51.971 ;
     RECT  62.256 51.863 62.28 53.027 ;
     RECT  26.448 50.771 27.816 53.075 ;
     RECT  38.832 51.863 40.104 53.075 ;
     RECT  55.344 51.971 56.232 53.075 ;
     RECT  28.896 51.347 32.52 53.747 ;
     RECT  57.312 51.863 58.056 53.891 ;
     RECT  2.832 51.863 2.856 53.939 ;
     RECT  10.416 50.195 10.44 53.939 ;
     RECT  26.544 53.075 27.816 53.939 ;
     RECT  39.792 53.075 40.104 53.939 ;
     RECT  57.312 53.891 57.816 53.939 ;
     RECT  59.664 51.863 60.984 53.939 ;
     RECT  13.392 51.863 16.392 53.968 ;
     RECT  29.52 53.747 32.52 53.968 ;
     RECT  45.648 51.863 48.648 53.968 ;
     RECT  9.384 0.037 10.656 0.132 ;
     RECT  9.384 0.132 10.704 1.763 ;
     RECT  9.384 1.763 10.896 2.291 ;
     RECT  7.92 2.137 9.36 2.151 ;
     RECT  8.112 2.151 9.36 2.245 ;
     RECT  9.384 2.291 11.088 2.627 ;
     RECT  9.384 2.627 11.952 3.301 ;
     RECT  18.912 2.869 20.208 4.115 ;
     RECT  9.384 3.301 10.704 4.019 ;
     RECT  10.728 3.301 11.952 3.925 ;
     RECT  28.344 3.637 29.4 3.779 ;
     RECT  28.944 3.779 29.4 4.453 ;
     RECT  13.512 3.925 14.496 6.901 ;
     RECT  24.312 3.971 24.504 5.029 ;
     RECT  42.456 3.973 43.584 4.259 ;
     RECT  45.504 5.075 45.6 6.517 ;
     RECT  38.808 5.077 40.2 5.747 ;
     RECT  14.952 5.171 15 6.517 ;
     RECT  35.112 5.653 36.432 6.277 ;
     RECT  12.912 5.747 13.2 6.709 ;
     RECT  38.784 5.747 40.2 6.805 ;
     RECT  30.312 6.181 31.68 7.237 ;
     RECT  41.496 6.229 42.816 6.323 ;
     RECT  48.504 6.229 49.968 6.517 ;
     RECT  49.992 6.275 51 12.757 ;
     RECT  35.112 6.277 36.192 7.379 ;
     RECT  33.816 6.323 34.8 13.093 ;
     RECT  29.28 6.515 29.4 7.381 ;
     RECT  44.376 6.517 45.6 6.805 ;
     RECT  48.504 6.517 49.536 6.563 ;
     RECT  11.688 6.709 13.2 8.149 ;
     RECT  38.808 6.805 40.2 7.427 ;
     RECT  44.52 6.805 45.6 8.675 ;
     RECT  58.728 6.805 59.856 7.619 ;
     RECT  30.408 7.237 31.68 10.115 ;
     RECT  31.704 7.333 33.072 7.765 ;
     RECT  35.112 7.379 36.216 8.533 ;
     RECT  28.152 7.381 29.4 10.837 ;
     RECT  58.704 7.619 59.856 8.965 ;
     RECT  31.752 7.765 33.072 8.435 ;
     RECT  12.168 8.149 13.2 14.245 ;
     RECT  31.752 8.435 33.792 9.589 ;
     RECT  35.112 8.533 36.48 11.365 ;
     RECT  43.944 8.675 45.6 9.829 ;
     RECT  15 8.725 16.32 11.459 ;
     RECT  54.648 8.821 55.824 13.093 ;
     RECT  58.488 8.965 59.856 10.213 ;
     RECT  60.168 9.061 61.536 9.493 ;
     RECT  2.904 9.251 3.624 9.349 ;
     RECT  2.904 9.349 4.368 10.693 ;
     RECT  4.392 9.349 5.472 10.693 ;
     RECT  31.752 9.589 33.072 12.517 ;
     RECT  38.904 9.637 40.2 12.517 ;
     RECT  23.664 9.731 24 10.789 ;
     RECT  44.28 9.829 45.6 9.971 ;
     RECT  13.512 9.923 14.976 11.459 ;
     RECT  30.408 10.115 31.728 20.725 ;
     RECT  57.144 10.165 58.464 14.005 ;
     RECT  58.488 10.213 59.616 12.805 ;
     RECT  60.696 10.307 61.8 18.709 ;
     RECT  28.152 10.837 29.28 13.525 ;
     RECT  2.712 11.171 3.792 12.517 ;
     RECT  35.304 11.365 36.48 12.467 ;
     RECT  13.512 11.459 16.32 11.845 ;
     RECT  13.512 11.845 14.928 14.053 ;
     RECT  14.952 11.845 16.32 14.099 ;
     RECT  35.304 12.467 36.024 13.093 ;
     RECT  27.888 12.563 28.032 14.005 ;
     RECT  58.488 13.091 59.616 17.843 ;
     RECT  24.312 13.093 25.824 14.243 ;
     RECT  38.664 13.523 39.648 26.197 ;
     RECT  28.152 13.525 29.184 14.389 ;
     RECT  31.752 13.715 33.072 18.277 ;
     RECT  13.512 14.053 14.784 14.197 ;
     RECT  14.808 14.099 16.32 16.931 ;
     RECT  13.512 14.197 14.736 15.157 ;
     RECT  25.848 14.197 27.264 14.243 ;
     RECT  51.312 14.197 52.704 15.443 ;
     RECT  52.728 14.197 53.952 15.061 ;
     RECT  24.312 14.243 24.792 15.349 ;
     RECT  33.816 14.627 34.8 18.757 ;
     RECT  52.728 15.061 53.808 15.443 ;
     RECT  13.512 15.299 14.736 16.885 ;
     RECT  20.928 15.491 21.312 16.547 ;
     RECT  12.168 15.827 13.2 17.461 ;
     RECT  16.344 15.925 17.616 16.789 ;
     RECT  24.312 16.019 24.792 17.317 ;
     RECT  20.928 16.547 21.456 16.885 ;
     RECT  44.424 16.547 45.6 18.181 ;
     RECT  17.16 16.835 18.48 16.979 ;
     RECT  18.912 16.885 20.016 25.187 ;
     RECT  20.04 16.885 21.456 17.317 ;
     RECT  41.4 17.029 42.384 17.699 ;
     RECT  42.408 17.029 43.488 17.699 ;
     RECT  49.656 17.075 51 18.805 ;
     RECT  20.136 17.317 21.456 18.181 ;
     RECT  24.312 17.317 25.728 18.419 ;
     RECT  25.752 17.317 26.88 17.363 ;
     RECT  25.752 17.363 27.264 18.419 ;
     RECT  41.4 17.699 41.592 18.565 ;
     RECT  58.2 17.843 59.616 19.669 ;
     RECT  49.656 18.805 50.88 19.571 ;
     RECT  44.52 18.851 45.6 20.965 ;
     RECT  8.112 19.333 9.6 20.579 ;
     RECT  31.752 19.523 33.072 23.653 ;
     RECT  49.656 19.571 51 23.555 ;
     RECT  33.816 20.003 34.8 27.397 ;
     RECT  8.112 20.579 9.048 20.821 ;
     RECT  30.408 20.725 31.68 21.347 ;
     RECT  44.52 20.965 45.504 21.203 ;
     RECT  36.792 21.013 38.208 21.683 ;
     RECT  44.52 21.203 45.6 22.163 ;
     RECT  30.408 21.347 31.728 24.757 ;
     RECT  44.472 22.163 45.6 23.987 ;
     RECT  16.344 22.211 16.872 22.597 ;
     RECT  16.344 22.597 17.712 23.843 ;
     RECT  20.232 23.123 20.28 24.373 ;
     RECT  26.808 23.173 28.032 24.131 ;
     RECT  41.4 23.317 42.432 24.035 ;
     RECT  42.456 23.317 43.488 24.035 ;
     RECT  49.632 23.555 51 24.901 ;
     RECT  31.752 23.653 33.024 23.941 ;
     RECT  16.344 23.843 18.6 24.757 ;
     RECT  44.184 23.987 45.6 27.155 ;
     RECT  41.4 24.035 43.488 25.045 ;
     RECT  15.192 24.757 16.32 26.197 ;
     RECT  17.112 24.757 18.6 25.187 ;
     RECT  49.608 24.901 51 25.715 ;
     RECT  41.4 25.045 42.72 25.141 ;
     RECT  46.92 25.045 48 26.243 ;
     RECT  41.688 25.141 42.72 25.187 ;
     RECT  18.912 25.187 20.112 27.877 ;
     RECT  20.28 25.763 20.472 26.965 ;
     RECT  14.472 26.243 15.84 26.291 ;
     RECT  31.752 26.243 33.072 32.341 ;
     RECT  41.4 26.243 41.688 27.301 ;
     RECT  43.944 27.155 45.6 28.357 ;
     RECT  42.216 27.301 43.488 28.499 ;
     RECT  20.184 27.347 21.264 28.451 ;
     RECT  38.664 27.443 39.648 37.429 ;
     RECT  18.912 27.877 19.968 28.979 ;
     RECT  26.76 27.877 28.032 29.701 ;
     RECT  35.112 27.925 36.288 28.837 ;
     RECT  15.936 28.163 16.32 29.365 ;
     RECT  20.184 28.451 21.456 29.749 ;
     RECT  17.256 28.453 18.6 29.411 ;
     RECT  46.344 28.453 47.472 31.379 ;
     RECT  43.944 28.499 45.6 29.605 ;
     RECT  35.4 28.931 36.432 29.699 ;
     RECT  18.912 28.979 20.16 31.861 ;
     RECT  18.24 29.411 18.6 29.605 ;
     RECT  43.944 29.605 45.024 30.757 ;
     RECT  35.4 29.699 36.456 30.469 ;
     RECT  20.328 29.749 21.456 31.141 ;
     RECT  26.808 29.987 28.032 31.379 ;
     RECT  42.12 30.229 43.488 31.091 ;
     RECT  24.552 30.373 26.016 31.429 ;
     RECT  35.4 30.469 36.624 32.483 ;
     RECT  36.648 30.757 38.112 32.483 ;
     RECT  44.04 30.757 45.024 32.389 ;
     RECT  9.336 30.901 10.848 31.669 ;
     RECT  8.112 30.995 9.312 32.677 ;
     RECT  41.4 31.091 43.488 32.053 ;
     RECT  49.704 31.091 51 36.515 ;
     RECT  20.424 31.141 21.456 31.907 ;
     RECT  13.992 31.235 14.088 31.285 ;
     RECT  13.992 31.285 15.36 32.819 ;
     RECT  26.76 31.379 28.032 33.637 ;
     RECT  24.552 31.429 25.632 32.197 ;
     RECT  25.656 31.475 26.736 33.539 ;
     RECT  18.912 31.861 19.92 32.725 ;
     RECT  20.184 31.907 21.456 32.531 ;
     RECT  10.296 31.955 11.376 33.875 ;
     RECT  42.312 32.053 43.488 33.443 ;
     RECT  31.896 32.341 33.072 33.107 ;
     RECT  44.28 32.435 45.6 37.621 ;
     RECT  37.488 32.483 38.112 33.445 ;
     RECT  13.512 32.819 15.36 32.917 ;
     RECT  8.112 32.915 9.312 34.691 ;
     RECT  13.512 32.917 14.496 35.171 ;
     RECT  31.896 33.107 33.168 34.211 ;
     RECT  14.52 33.251 15.648 35.171 ;
     RECT  25.416 33.539 26.736 35.171 ;
     RECT  18.912 33.635 20.16 35.845 ;
     RECT  10.296 33.875 11.424 34.117 ;
     RECT  10.344 34.117 11.424 35.413 ;
     RECT  31.752 34.211 33.168 35.989 ;
     RECT  8.112 34.691 9.408 35.747 ;
     RECT  33.816 34.835 34.8 43.189 ;
     RECT  10.44 35.413 11.424 35.603 ;
     RECT  10.344 35.603 11.424 36.515 ;
     RECT  31.752 35.989 32.976 36.131 ;
     RECT  42.12 36.085 43.488 37.043 ;
     RECT  31.752 36.131 33.072 40.885 ;
     RECT  10.056 36.515 11.424 38.483 ;
     RECT  50.112 36.515 51 36.805 ;
     RECT  50.112 36.805 50.736 36.997 ;
     RECT  46.392 36.901 47.904 37.621 ;
     RECT  17.112 36.997 18.24 37.045 ;
     RECT  42.96 37.043 43.488 37.237 ;
     RECT  17.208 37.235 18.24 37.283 ;
     RECT  44.376 37.621 45.6 38.435 ;
     RECT  46.392 37.621 47.424 37.667 ;
     RECT  46.344 37.667 47.424 38.435 ;
     RECT  42.984 38.243 44.352 38.435 ;
     RECT  38.664 38.291 39.648 39.589 ;
     RECT  11.136 38.483 11.424 39.877 ;
     RECT  8.328 39.011 8.376 39.203 ;
     RECT  8.112 39.203 8.376 40.309 ;
     RECT  26.76 39.587 28.032 40.643 ;
     RECT  25.32 39.925 26.736 40.165 ;
     RECT  8.112 40.309 9.12 42.995 ;
     RECT  27.648 40.643 28.032 40.741 ;
     RECT  41.4 40.789 42.864 42.517 ;
     RECT  31.848 40.885 33.072 44.053 ;
     RECT  51.312 41.077 52.368 41.219 ;
     RECT  52.392 41.077 53.76 41.219 ;
     RECT  24.552 42.083 25.632 43.139 ;
     RECT  41.4 42.517 42.672 42.803 ;
     RECT  41.4 42.803 42.864 44.437 ;
     RECT  8.112 42.995 9.096 43.141 ;
     RECT  24.552 43.139 24.648 43.573 ;
     RECT  16.728 44.053 18.24 44.245 ;
     RECT  31.848 44.053 33.024 45.827 ;
     RECT  16.728 44.245 18.096 45.059 ;
     RECT  21.528 44.245 22.896 45.635 ;
     RECT  10.104 44.341 11.424 47.317 ;
     RECT  13.512 44.389 14.784 45.011 ;
     RECT  41.4 44.437 42.768 45.925 ;
     RECT  33.816 44.483 34.8 46.787 ;
     RECT  16.728 45.059 18.24 47.267 ;
     RECT  24.552 45.059 24.648 46.405 ;
     RECT  21.552 45.635 22.896 46.117 ;
     RECT  31.752 45.827 33.024 46.211 ;
     RECT  21.552 46.117 21.696 46.693 ;
     RECT  21.72 46.117 22.896 46.163 ;
     RECT  31.752 46.211 33.072 47.461 ;
     RECT  51.576 46.261 53.04 46.451 ;
     RECT  42.168 46.451 43.296 47.939 ;
     RECT  33.096 46.787 34.8 47.989 ;
     RECT  4.584 47.363 6 48.659 ;
     RECT  33.288 47.989 34.8 48.421 ;
     RECT  25.128 48.421 26.208 48.611 ;
     RECT  33.528 48.421 34.8 48.901 ;
     RECT  46.536 48.421 47.952 49.619 ;
     RECT  6.072 48.515 7.344 48.755 ;
     RECT  3.816 48.659 6 48.853 ;
     RECT  3.816 48.853 4.8 49.043 ;
     RECT  4.824 48.853 6 49.043 ;
     RECT  13.512 48.853 15.024 49.427 ;
     RECT  33.768 48.901 34.8 50.101 ;
     RECT  10.44 49.043 11.952 50.531 ;
     RECT  31.752 49.043 32.832 49.091 ;
     RECT  31.752 49.091 33.024 49.475 ;
     RECT  36.504 49.381 37.584 50.195 ;
     RECT  31.752 49.475 33.072 50.195 ;
     RECT  47.976 49.525 49.44 50.435 ;
     RECT  54.072 49.619 55.248 50.195 ;
     RECT  33.816 50.101 34.8 50.963 ;
     RECT  31.752 50.195 33.792 50.677 ;
     RECT  35.112 50.195 36.48 51.299 ;
     RECT  46.104 50.195 46.248 51.205 ;
     RECT  47.976 50.435 48.648 51.301 ;
     RECT  32.52 50.677 33.792 50.963 ;
     RECT  27.816 50.771 28.848 51.347 ;
     RECT  13.896 51.253 15.312 51.301 ;
     RECT  13.992 51.301 15.12 51.397 ;
     RECT  48.168 51.301 48.648 51.541 ;
     RECT  27.816 51.347 28.896 53.747 ;
     RECT  56.28 51.863 57.312 51.971 ;
     RECT  60.984 51.863 62.256 53.027 ;
     RECT  56.232 51.971 57.312 53.075 ;
  END
END ot_hgi_idx_ix2_kc
END LIBRARY
